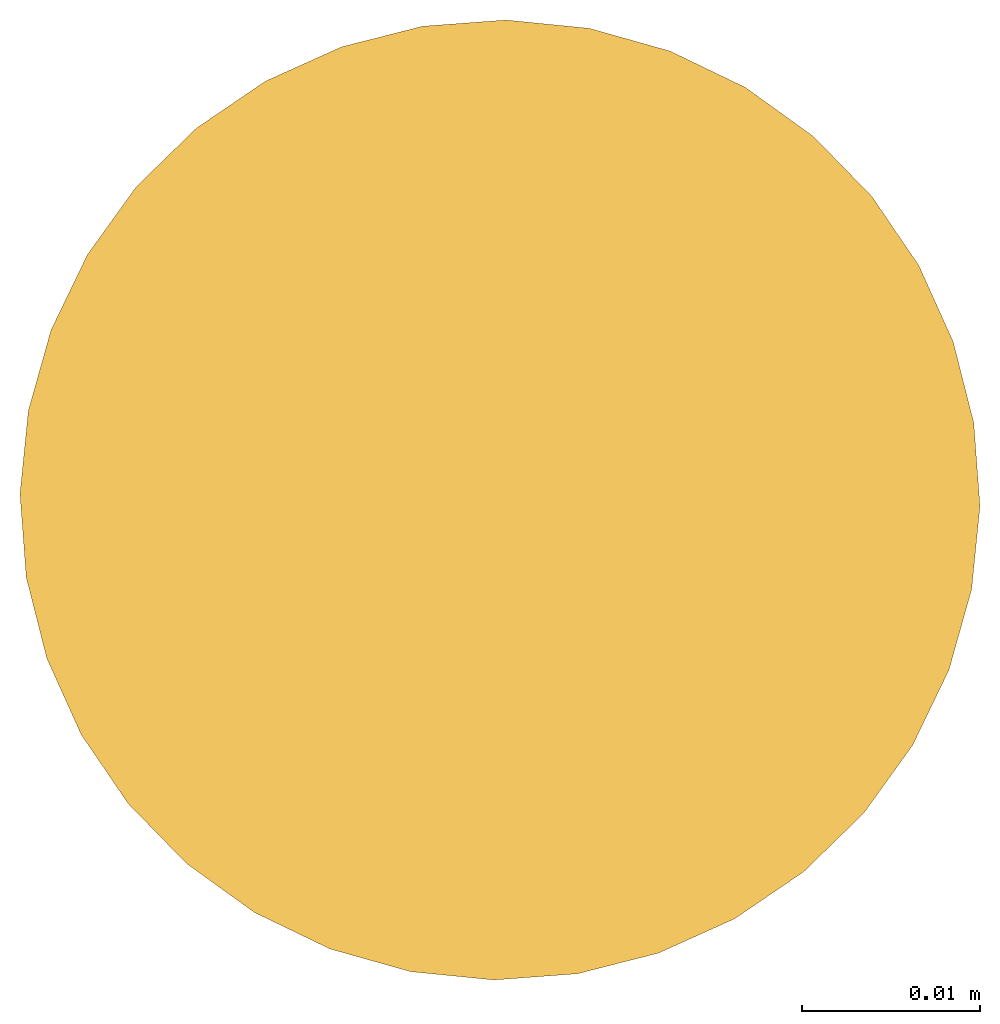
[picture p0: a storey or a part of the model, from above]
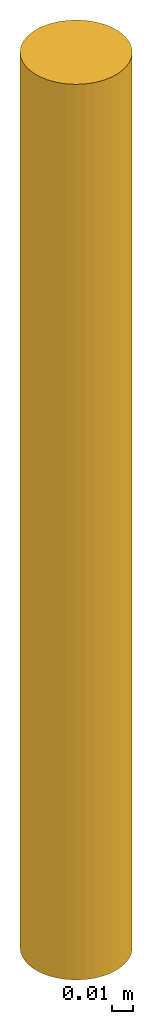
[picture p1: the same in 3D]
Properties of the parts of a building model (IFC2X3), part 1 of 3

# File
Description: ViewDefinition [CoordinationView_V2.0]
File name: BR001-350-202.1 (EDITED).ifc (Edited by Naviate Simple BIM 2022 version 6)
Time: 2026-03-27T10:06:01+01:00
Written by: ODA SDAI 24.12
Made in: Autodesk Revit 25.4.41.14 (ENU) - IFC 25.4.0.27

# IfcProject, 01. Avinor Drift
LongName: Terminal 2 . Satellitt; Phase: Som Bygget

# IfcSite (5)
RefElevation: 0 mm
Name | RefLatitude | RefLongitude
4 x Default | 60, 17, 20, 899658 | 5, 13, 37, 654037
Default | 42, 24, 53, 508911 | -71, -15, -29, -58837

# IfcBuilding (5)
Name | LongName
br001-a-200-1-0001 | br001-a-200-1-0001

3 x Bygning (endres i Project Information) | Bygning (endres i Project Information)

# IfcBuildingStorey: Level:Level - BR001_ARK (3)
In: br001-a-200-1-0001
Name | LongName | Elevation (mm)
H01-Nivå D+0,36 | H01-Nivå D+0,36 | 51360
H02-Nivå F-3,5 m | H02-Nivå F-3,5 m | 55500
H03-Nivå G-5m | H03-Nivå G-5m | 59000

# IfcBuildingStorey: Level:Level Elektro, H01-Nivå D+0,36
In: Bygning (endres i Project Information)
LongName: H01-Nivå D+0,36; Elevation: 51360 mm

# IfcBuildingStorey: Level:NO_Nivå_Meter-VVS (4)
In: Bygning (endres i Project Information)
Name | LongName | Elevation (mm)
2 x H01-Nivå D+0,36 | H01-Nivå D+0,36 | 51360
H02-Nivå F-3,5 m | H02-Nivå F-3,5 m | 55500
U01-Nivå B+3,1m | U01-Nivå B+3,1m | 47800

# IfcBuildingStorey: Level:NSW Kote - Triangel med navn og kote, Arial 2 mm KP (3)
Name | LongName | Elevation (mm)
U01-Nivå B+3,1m | U01-Nivå B+3,1m | 47800
H01-Nivå D+0,36 | H01-Nivå D+0,36 | 51360
H02-Nivå F-3,5 m | H02-Nivå F-3,5 m | 55500

# IfcBeam: 315*100, PLASSTØPTDEKKE
In: H01-Nivå D+0,36
Description: 315*100
ePset_Simplebim - Assembly Level: Leaf
ePset_LocationTool - Splitting: RESULT
ePset_SimplebimBasicQuantities - Weight, as steel (Simplebim): 629.389 kg; Volume, net (Simplebim): 0.0801769 m3; Area, sides, net (Simplebim): 2.20169 m2; Height (Simplebim): 315 mm; Width (Simplebim): 1800 mm; Length (Simplebim): 1941 mm
Pset_BeamCommon - Reference: 315*100

# IfcBeam: 500*250, PLASSTØPTBJELKE
In: H01-Nivå D+0,36
Description: 500*250
ePset_SimplebimBasicQuantities - Volume, net (Simplebim): 0.0735892 m3; Weight, as steel (Simplebim): 577.675 kg; Area, sides, net (Simplebim): 1.13307 m2; Width (Simplebim): 250 mm; Height (Simplebim): 500 mm; Length (Simplebim): 589 mm
Pset_BeamCommon - Reference: 500*250
ePset_Simplebim - Assembly Level: Leaf
ePset_LocationTool - Splitting: RESULT

# IfcBeam: 650*400 (13)
Description: 650*400
ePset_Simplebim - Assembly Level: Leaf
Pset_BeamCommon - Reference: 650*400
Name | In | Material | Width (Simplebim) (mm) | Volume, net (Simplebim) (m3) | Weight, as steel (Simplebim) (kg) | Area, sides, net (Simplebim) (m2) | Length (Simplebim) (mm) | Height (Simplebim) (mm) | Splitting
4 x PLASSTØPTBJELKE | H02-Nivå F-3,5 m | CONCRETE/C55/67 171016 | 400.026 | 1.56 | 12246 | 13.12 | 6000 | 650 | ORIGINAL
PLASSTØPTBJELKE | H01-Nivå D+0,36 | CONCRETE/C55/67 171016 | 400.024 | 1.456 | 11429.6 | 12.28 | 5600 | 650 | ORIGINAL
PLASSTØPTBJELKE | H02-Nivå F-3,5 m | CONCRETE/C55/67 171016 | 6282.82 | 2.20617 | 17318.5 | 18.3391 | 6282.87 | 650 | ORIGINAL
PLASSTØPTBJELKE | H01-Nivå D+0,36 | CONCRETE/C55/67 171016 | 400.024 | 1.4294 | 11220.8 | 12.139 | 5590 | 650 | ORIGINAL
PLASSTØPTBJELKE | H01-Nivå D+0,36 | CONCRETE/C55/67 171016 | 400.023 | 1.4034 | 11016.7 | 11.929 | 5490 | 650 | ORIGINAL
PLASSTØPTBJELKE | H01-Nivå D+0,36 | CONCRETE/C55/67 171016 | 400.025 | 1.508 | 11837.8 | 12.7 | 5800 | 650 | ORIGINAL
PLASSTØPTBJELKE | H02-Nivå F-3,5 m |  | 328 | 0.0854129 | 670.492 | 1.20987 | 400 | 650 | RESULT
PLASSTØPTBJELKE | H02-Nivå F-3,5 m |  | 340 | 0.0731105 | 573.917 | 1.2182 | 623 | 650 | RESULT
PLASSTØPTBJELKE | H02-Nivå F-3,5 m |  | 328 | 0.0854267 | 670.6 | 1.20999 | 400 | 650 | RESULT
PLASSTØPTBJELKE | H01-Nivå D+0,36 |  | 5922 | 1.24086 | 9740.74 | 12.8968 | 5922 | 390 | RESULT

# IfcBeam: DT450*2400-100-50-1200-0-200-0.3 (12)
In: H01-Nivå D+0,36
Description: DT450*2400-100-50-1200-0-200-0.3
ePset_Simplebim - Assembly Level: Leaf
ePset_SimplebimBasicQuantities - Height (Simplebim): 450 mm
Pset_BeamCommon - Reference: DT450*2400-100-50-1200-0-200-0.3
Name | Volume, net (Simplebim) (m3) | Weight, as steel (Simplebim) (kg) | Area, sides, net (Simplebim) (m2) | Length (Simplebim) (mm) | Width (Simplebim) (mm) | Splitting
2 x DT | 2.80784 | 22041.5 | 79.3586 | 12535 | 2400.06 | ORIGINAL | Material: CONCRETE/C45/55
DT | 2.52784 | 19843.5 | 71.5824 | 12485 | 2400.06 | ORIGINAL | Material: CONCRETE/C45/55
2 x DT | 2.79475 | 21938.8 | 78.8674 | 12535 | 2400.06 | ORIGINAL | Material: CONCRETE/C45/55
DT | 1.52352 | 11959.6 | 45.8835 | 11985 | 1529 | RESULT
DT | 2.6846 | 21074.1 | 75.8952 | 11984 | 2400 | RESULT
2 x DT | 2.67679 | 21012.8 | 75.5827 | 11985 | 2400 | RESULT
DT | 1.58364 | 12431.6 | 47.6803 | 12535 | 1529 | RESULT
DT | 1.12787 | 8853.78 | 33.2882 | 10085 | 1399 | RESULT
DT | 1.44633 | 11353.7 | 42.7471 | 11970 | 1399 | RESULT

# IfcBeam: HD265 (2)
In: H01-Nivå D+0,36
Description: HD265
ePset_Simplebim - Assembly Level: Leaf
Pset_BeamCommon - Reference: HD265
ePset_SimplebimBasicQuantities - Height (Simplebim): 265 mm
Name | Splitting | Volume, net (Simplebim) (m3) | Width (Simplebim) (mm) | Area, sides, net (Simplebim) (m2) | Length (Simplebim) (mm) | Weight, as steel (Simplebim) (kg)
HULLDEKKE | ORIGINAL | 0.302374 | 1196.01 | 10.5438 | 2346.58 | 2373.64 | Material: CONCRETE/C45/55 4257
HULLDEKKE | RESULT | 0.225103 | 598 | 7.971 | 2948 | 1767.06

# IfcBeam: IPE400 (2)
In: H01-Nivå D+0,36
Description: IPE400
ePset_Simplebim - Assembly Level: Leaf
ePset_LocationTool - Splitting: RESULT
Pset_BeamCommon - Reference: IPE400
Name | Volume, net (Simplebim) (m3) | Weight, as steel (Simplebim) (kg) | Area, sides, net (Simplebim) (m2) | Width (Simplebim) (mm) | Height (Simplebim) (mm) | Length (Simplebim) (mm)
STÅLBJELKE | 0.00207902 | 16.3203 | 0.425815 | 120 | 235 | 590
STÅLBJELKE | 0.0461678 | 362.417 | 8.64705 | 180 | 400 | 6173

# IfcBuildingElementProxy: LKR-600:LKR-160-600, LKR-600:LKR-160-600:5845895
In: H01-Nivå D+0,36
Type - Material: 3601.001 Avtrekk
ePset_SimplebimBasicQuantities - Area, largest surface, net (Simplebim): 0.126 m2; Length (Simplebim): 630 mm; Volume, net (Simplebim): 0.000116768 m3; Thickness (Simplebim): 200.2 mm; Height (Simplebim): 200.2 mm
ePset_Simplebim - Assembly Level: Leaf
ePset_LocationTool - Splitting: ORIGINAL
Pset_BuildingElementProxyCommon - Reference: LKR-600:LKR-160-600
Group: 36.02 Avtrekk 1.etg syd og vest: 5

# IfcBuildingElementProxy: LKR-600:LKR-160-600, LKR-600:LKR-160-600:5846157
In: H01-Nivå D+0,36
Type - Material: 3601.001 Tilluft
ePset_LocationTool - Splitting: ORIGINAL
ePset_SimplebimBasicQuantities - Area, largest surface, net (Simplebim): 0.126 m2; Length (Simplebim): 630 mm; Volume, net (Simplebim): 0.000116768 m3; Thickness (Simplebim): 200.2 mm; Height (Simplebim): 200.2 mm
ePset_Simplebim - Assembly Level: Leaf
Pset_BuildingElementProxyCommon - Reference: LKR-600:LKR-160-600
Group: 36.02 Tilluft 1.etg syd og vest: 9

# IfcBuildingElementProxy: RA4303 Dome Kamera SNC-RZ25P i tak:RA4303, RA4303 Dome Kamera SNC-RZ25P i tak:RA4303:2982597
In: H01-Nivå D+0,36
Type - Material: Plastic - White
Classification: RA001 (Uniformat)
ePset_LocationTool - Splitting: ORIGINAL
ePset_SimplebimBasicQuantities - Volume, net (Simplebim): 0.00247107 m3; Thickness (Simplebim): 140 mm; Length (Simplebim): 148 mm; Height (Simplebim): 206 mm; Area, largest surface, net (Simplebim): 0.0438648 m2
Pset_BuildingElementProxyCommon - Reference: RA4303 Dome Kamera SNC-RZ25P i tak:RA4303
ePset_Simplebim - Assembly Level: Leaf

# IfcBuildingElementProxy: REACT V-SR GMBa VAV:REACT V-SR GMBa-160 (2)
In: H01-Nivå D+0,36
Type - Material: MC_255_255_255_0_50, MC_0_0_0_0_50, MC_191_191_191_0_50
Pset_BuildingElementProxyCommon - Reference: REACT V-SR GMBa VAV:REACT V-SR GMBa-160
ePset_Simplebim - Assembly Level: Leaf
ePset_SimplebimBasicQuantities - Volume, net (Simplebim): 0.00126622 m3; Area, largest surface, net (Simplebim): 0.189784 m2
ePset_LocationTool - Splitting: ORIGINAL
Name (REACT V-SR GMBa VAV:REACT V-SR GMBa-160:...) | Height (Simplebim) (mm) | Length (Simplebim) (mm) | Thickness (Simplebim) (mm) | Group
5845898 | 290.687 | 398.724 | 197.261 | 36.02 Avtrekk 1.etg syd og vest: 5
5846158 | 253.772 | 396.977 | 247.819 | 36.02 Tilluft 1.etg syd og vest: 9

# IfcColumn: 120*190, STÅLSØYLE
In: H01-Nivå D+0,36
Description: 120*190
ePset_SimplebimBasicQuantities - Area, sides, net (Simplebim): 0.00992928 m2; Depth (Simplebim): 120.001 mm; Width (Simplebim): 16 mm; Volume, net (Simplebim): 0.0003648 m3; Weight, as steel (Simplebim): 2.86368 kg; Height (Simplebim): 190.001 mm
ePset_Simplebim - Assembly Level: Leaf
ePset_LocationTool - Splitting: ORIGINAL
Pset_ColumnCommon - Reference: 120*190

# IfcColumn: 185*300 (2)
In: H01-Nivå D+0,36
Description: 185*300
Pset_ColumnCommon - Reference: 185*300
ePset_Simplebim - Assembly Level: Leaf
ePset_SimplebimBasicQuantities - Weight, as steel (Simplebim): 4.35675 kg; Width (Simplebim): 10 mm; Height (Simplebim): 342.947 mm; Depth (Simplebim): 342.946 mm; Area, sides, net (Simplebim): 0.00971243 m2; Volume, net (Simplebim): 0.000555 m3
ePset_LocationTool - Splitting: ORIGINAL

# IfcColumn: 20*860, STÅLSØYLE
In: H01-Nivå D+0,36
Description: 20*860
ePset_SimplebimBasicQuantities - Area, sides, net (Simplebim): 0.527981 m2; Volume, net (Simplebim): 0.00516 m3; Weight, as steel (Simplebim): 40.506 kg; Depth (Simplebim): 300 mm; Width (Simplebim): 20.0038 mm; Height (Simplebim): 860 mm
ePset_Simplebim - Assembly Level: Leaf
Pset_ColumnCommon - Reference: 20*860
ePset_LocationTool - Splitting: ORIGINAL

# IfcColumn: 200*150, STÅLSØYLE
In: H02-Nivå F-3,5 m
Description: 200*150
ePset_SimplebimBasicQuantities - Height (Simplebim): 247.488 mm; Area, sides, net (Simplebim): 0.00701916 m2; Depth (Simplebim): 247.487 mm; Volume, net (Simplebim): 0.0003 m3; Width (Simplebim): 10 mm; Weight, as steel (Simplebim): 2.355 kg
ePset_Simplebim - Assembly Level: Leaf
Pset_ColumnCommon - Reference: 200*150
ePset_LocationTool - Splitting: ORIGINAL

# IfcColumn: 300*400 (2)
In: H02-Nivå F-3,5 m
Description: 300*400
ePset_LocationTool - Splitting: ORIGINAL
ePset_Simplebim - Assembly Level: Leaf
Pset_ColumnCommon - Reference: 300*400
ePset_SimplebimBasicQuantities - Volume, net (Simplebim): 0.036 m3; Weight, as steel (Simplebim): 282.6 kg; Height (Simplebim): 400.002 mm; Depth (Simplebim): 300.002 mm; Width (Simplebim): 300 mm
Name | Area, sides, net (Simplebim) (m2)
PLASSTØPTSØYLE | 0.419997
PLASSTØPTSØYLE | 0.419989

# IfcColumn: 400*400 (6)
Description: 400*400
ePset_LocationTool - Splitting: RESULT
ePset_Simplebim - Assembly Level: Leaf
ePset_SimplebimBasicQuantities - Depth (Simplebim): 400 mm; Width (Simplebim): 400 mm
Pset_ColumnCommon - Reference: 400*400
Name | In | Volume, net (Simplebim) (m3) | Weight, as steel (Simplebim) (kg) | Area, sides, net (Simplebim) (m2) | Height (Simplebim) (mm)
2 x PLASSTØPTSØYLE | H02-Nivå F-3,5 m | 0.6192 | 4860.72 | 6.19199 | 3870
PLASSTØPTSØYLE | H02-Nivå F-3,5 m | 0.6192 | 4860.72 | 6.19198 | 3870
2 x PLASSTØPTSØYLE | U01-Nivå B+3,1m | 0.1488 | 1168.08 | 1.48799 | 930
PLASSTØPTSØYLE | U01-Nivå B+3,1m | 0.1488 | 1168.08 | 1.48798 | 930

# IfcColumn: Columns T10:Columns T2, Columns T10:Columns T2:11666152
In: H02-Nivå F-3,5 m
Type - PredefinedType: COLUMN; Material: <Unnamed>
ePset_Simplebim - Assembly Level: Leaf
ePset_SimplebimBasicQuantities - Area, sides, net (Simplebim): 8.43072 m2; Width (Simplebim): 400 mm; Weight, as steel (Simplebim): 1413 kg; Height (Simplebim): 3000 mm; Depth (Simplebim): 949.317 mm; Volume, net (Simplebim): 0.18 m3
ePset_LocationTool - Splitting: ORIGINAL
Pset_ColumnCommon - Reference: Columns T10:Columns T2

# IfcColumn: Columns T11:Columns T2, Columns T11:Columns T2:11666168
In: H02-Nivå F-3,5 m
Type - PredefinedType: COLUMN; Material: <Unnamed>
Pset_ColumnCommon - Reference: Columns T11:Columns T2
ePset_Simplebim - Assembly Level: Leaf
ePset_SimplebimBasicQuantities - Area, sides, net (Simplebim): 8.43072 m2; Width (Simplebim): 400 mm; Weight, as steel (Simplebim): 1413 kg; Height (Simplebim): 3000 mm; Depth (Simplebim): 949.317 mm; Volume, net (Simplebim): 0.18 m3
ePset_LocationTool - Splitting: ORIGINAL

# IfcColumn: D500 (4)
In: H02-Nivå F-3,5 m
Description: D500
ePset_LocationTool - Splitting: ORIGINAL
ePset_Simplebim - Assembly Level: Leaf
ePset_SimplebimBasicQuantities - Weight, as steel (Simplebim): 4620.39 kg; Volume, net (Simplebim): 0.588585 m3; Height (Simplebim): 3010 mm; Width (Simplebim): 500 mm; Depth (Simplebim): 500 mm
Pset_ColumnCommon - Reference: D500
Name | Area, sides, net (Simplebim) (m2)
2 x PLASSTØPTSØYLE | 4.72324
PLASSTØPTSØYLE | 4.72326
PLASSTØPTSØYLE | 4.72323

# IfcColumn: D600 (8)
Description: D600
ePset_SimplebimBasicQuantities - Width (Simplebim): 600 mm; Depth (Simplebim): 600 mm
ePset_Simplebim - Assembly Level: Leaf
Pset_ColumnCommon - Reference: D600
Name | In | Area, sides, net (Simplebim) (m2) | Height (Simplebim) (mm) | Weight, as steel (Simplebim) (kg) | Volume, net (Simplebim) (m3) | Splitting
3 x PLASSTØPTSØYLE | H01-Nivå D+0,36 | 2.24079 | 1190 | 2630.4 | 0.335083 | ORIGINAL
PLASSTØPTSØYLE | H01-Nivå D+0,36 | 2.24078 | 1190 | 2630.4 | 0.335083 | ORIGINAL
2 x PLASSTØPTSØYLE | H02-Nivå F-3,5 m | 1.61939 | 860 | 1900.96 | 0.242161 | RESULT
2 x PLASSTØPTSØYLE | H02-Nivå F-3,5 m | 1.6194 | 860 | 1900.96 | 0.242161 | RESULT

# IfcColumn: NSW Søyle - Betong rektangulær:300 x 300 mm, NSW Søyle - Betong rektangulær:300 x 300 mm:1708831
In: H01-Nivå D+0,36
Type - PredefinedType: COLUMN; Material: _NSW Betong
ePset_SimplebimBasicQuantities - Volume, net (Simplebim): 0.08082 m3; Weight, as steel (Simplebim): 634.437 kg; Depth (Simplebim): 300 mm; Width (Simplebim): 300 mm; Height (Simplebim): 900 mm; Area, sides, net (Simplebim): 1.05891 m2
ePset_LocationTool - Splitting: RESULT
ePset_Simplebim - Assembly Level: Leaf
Pset_ColumnCommon - Reference: NSW Søyle - Betong rektangulær:300 x 300 mm

# IfcColumn: NSW Søyle - Betong rektangulær:400 x 400 mm (6)
Type - PredefinedType: COLUMN; Material: _NSW Betong
ePset_Simplebim - Assembly Level: Leaf
ePset_SimplebimBasicQuantities - Depth (Simplebim): 400 mm
Pset_ColumnCommon - Reference: NSW Søyle - Betong rektangulær:400 x 400 mm
Name (NSW Søyle - Betong rektangulær:400 x 400 mm:...) | In | Splitting | Volume, net (Simplebim) (m3) | Area, sides, net (Simplebim) (m2) | Width (Simplebim) (mm) | Height (Simplebim) (mm) | Weight, as steel (Simplebim) (kg)
865032 | H02-Nivå F-3,5 m | ORIGINAL | 0.01598 | 0.157657 | 100 | 400 | 125.443
865033 | H02-Nivå F-3,5 m | ORIGINAL | 0.01598 | 0.157657 | 100 | 400 | 125.443
865034 | H02-Nivå F-3,5 m | ORIGINAL | 0.01598 | 0.157657 | 100 | 400 | 125.443
263693 | H01-Nivå D+0,36 | RESULT | 0.1598 | 1.57657 | 400 | 1000 | 1254.43
263692 | H01-Nivå D+0,36 | RESULT | 0.1598 | 1.57657 | 400 | 1000 | 1254.43
263691 | H01-Nivå D+0,36 | RESULT | 0.1598 | 1.57657 | 400 | 1000 | 1254.43

# IfcColumn: NSW Søyle - Betong rund:ø500 mm (10)
Type - PredefinedType: COLUMN; Material: _NSW Betong
ePset_Simplebim - Assembly Level: Leaf
Pset_ColumnCommon - Reference: NSW Søyle - Betong rund:ø500 mm
ePset_SimplebimBasicQuantities - Depth (Simplebim): 500 mm
Name (NSW Søyle - Betong rund:ø500 mm:...) | In | Splitting | Area, sides, net (Simplebim) (m2) | Height (Simplebim) (mm) | Volume, net (Simplebim) (m3) | Width (Simplebim) (mm) | Weight, as steel (Simplebim) (kg)
865003 | H02-Nivå F-3,5 m | ORIGINAL | 0.15688 | 500 | 0.0195354 | 100 | 153.353
865016 | H02-Nivå F-3,5 m | ORIGINAL | 0.15688 | 500 | 0.0195354 | 100 | 153.353
865017 | H02-Nivå F-3,5 m | ORIGINAL | 0.15688 | 500 | 0.0195354 | 100 | 153.353
2017729 | H02-Nivå F-3,5 m | ORIGINAL | 5.56925 | 3550 | 0.693507 | 500 | 5444.03
263734 | H01-Nivå D+0,36 | RESULT | 1.5688 | 1000 | 0.195354 | 500 | 1533.53
263733 | H01-Nivå D+0,36 | RESULT | 1.5688 | 1000 | 0.195354 | 500 | 1533.53
263735 | H01-Nivå D+0,36 | RESULT | 1.5688 | 1000 | 0.195354 | 500 | 1533.53
263675 | H01-Nivå D+0,36 | RESULT | 1.5688 | 1000 | 0.195354 | 500 | 1533.53
263676 | H01-Nivå D+0,36 | RESULT | 1.5688 | 1000 | 0.195354 | 500 | 1533.53
263662 | H01-Nivå D+0,36 | RESULT | 1.5688 | 1000 | 0.195354 | 500 | 1533.53

# IfcColumn: RHS100*60*5, STÅLSØYLE
In: H01-Nivå D+0,36
Description: RHS100*60*5
ePset_LocationTool - Splitting: ORIGINAL
ePset_Simplebim - Assembly Level: Leaf
ePset_SimplebimBasicQuantities - Volume, net (Simplebim): 0.000882 m3; Depth (Simplebim): 100 mm; Weight, as steel (Simplebim): 6.9237 kg; Area, sides, net (Simplebim): 0.352791 m2; Width (Simplebim): 60.0004 mm; Height (Simplebim): 588 mm
Pset_ColumnCommon - Reference: RHS100*60*5

# IfcColumn: RHS150*100*6.3 (3)
Description: RHS150*100*6.3
ePset_Simplebim - Assembly Level: Leaf
Pset_ColumnCommon - Reference: RHS150*100*6.3
Name | In | Depth (Simplebim) (mm) | Area, sides, net (Simplebim) (m2) | Weight, as steel (Simplebim) (kg) | Volume, net (Simplebim) (m3) | Width (Simplebim) (mm) | Height (Simplebim) (mm) | Splitting
STÅLSØYLE | H02-Nivå F-3,5 m | 176.777 | 3.78417 | 93.5727 | 0.0119201 | 176.777 | 3985 | ORIGINAL
STÅLSØYLE | H01-Nivå D+0,36 | 177 | 0.612506 | 15.1454 | 0.00192935 | 177 | 645 | RESULT
STÅLSØYLE | H01-Nivå D+0,36 | 177 | 0.612506 | 15.1454 | 0.00192935 | 176 | 645 | RESULT

# IfcCovering: Pipe Insulation:GLAVA Rørskål ClimPipe Alu2, isol.kl.4, 45°C (12)
In: H01-Nivå D+0,36
Type - PredefinedType: INSULATION
ePset_Simplebim - Assembly Level: Leaf
Pset_CoveringCommon - Reference: Pipe Insulation:GLAVA Rørskål ClimPipe Alu2, isol.kl.4, 45°C
Name (Pipe Insulation:GLAVA Rørskål ClimPipe Alu2, isol.kl.4, 45°C:...) | Material | Splitting | Length (Simplebim) (mm) | Volume, net (Simplebim) (m3) | Area, largest surface, net (Simplebim) (m2) | Width (Simplebim) (mm) = Height (Simplebim) (mm)
5647646 | 3200.002 Retur | ORIGINAL | 381.468 | 0.00532851 | 0.160131 | 134
5647676 | 3200.003 Tur | ORIGINAL | 380 | 0.005308 | 0.159514 | 134
5647769 | 3200.003 Tur | ORIGINAL | 1563.5 | 0.0218573 | 0.656431 | 134
5647965 | 3200.003 Tur | ORIGINAL | 137 | 0.00398234 | 0.0545841 | 133.5
5647966 |  | ORIGINAL | 170 | 0.00237909 | 0.0713168 | 134
5647971 | 3200.003 Tur | ORIGINAL | 137 | 0.00398234 | 0.0545841 | 133.5
5648007 | 3200.002 Retur | ORIGINAL | 137 | 0.00398234 | 0.0545841 | 133.5
5648008 |  | ORIGINAL | 170 | 0.00237909 | 0.0713168 | 134
5648013 | 3200.002 Retur | ORIGINAL | 137 | 0.00398234 | 0.0545841 | 133.5
5648832 |  | RESULT | 10492 | 0.146559 | 0.0139787 | 134
5648856 |  | RESULT | 10502 | 0.146736 | 0.0139844 | 134
5647727 |  | RESULT | 1321 | 0.0184776 | 0.0139749 | 134

# IfcCovering: Pipe Insulation:GLAVA avløpsisol. slange økende 19mm (15,5-25,0) (18)
In: H01-Nivå D+0,36
Type - PredefinedType: INSULATION
ePset_Simplebim - Assembly Level: Leaf
Pset_CoveringCommon - Reference: Pipe Insulation:GLAVA avløpsisol. slange økende 19mm (15,5-25,0)
Name (Pipe Insulation:GLAVA avløpsisol. slange økende 19mm (15,5-25,0):...) | Material | Splitting | Length (Simplebim) (mm) | Area, largest surface, net (Simplebim) (m2) | Volume, net (Simplebim) (m3) | Height (Simplebim) (mm) | Width (Simplebim) (mm)
5597703 | 3700.001 Retur | ORIGINAL | 657.357 | 0.247394 | 0.0073879 | 120.1 | 120.1
5598242 | 3700.001 Retur | ORIGINAL | 186.738 | 0.0542593 | 0.00162291 | 186.738 | 120.1
5598259 | 3700.001 Retur | ORIGINAL | 131.604 | 0.0293422 | 0.000870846 | 120.1 | 112.698
5598268 | 3700.001 Retur | ORIGINAL | 131.604 | 0.0293422 | 0.000870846 | 120.1 | 112.698
5598296 | 3700.001 Retur | ORIGINAL | 156.55 | 0.057121 | 0.00169602 | 156.55 | 120.1
5598297 | 3700.001 Retur | ORIGINAL | 120.1 | 0.0403207 | 0.00120602 | 107.001 | 120.1
5598306 | 3700.001 Retur | ORIGINAL | 156.55 | 0.057121 | 0.00169602 | 156.55 | 120.1
5598397 | 3700.001 Tur | ORIGINAL | 630.858 | 0.237421 | 0.00709001 | 120.1 | 120.1
5598681 | 3700.001 Tur | ORIGINAL | 120.1 | 0.0542593 | 0.00162291 | 186.738 | 186.738
5598707 | 3700.001 Tur | ORIGINAL | 131.604 | 0.0293422 | 0.000870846 | 120.1 | 112.698
5598803 | 3700.001 Tur | ORIGINAL | 120.1 | 0.0403207 | 0.00120602 | 107.001 | 120.1
5598821 | 3700.001 Tur | ORIGINAL | 131.604 | 0.0293422 | 0.000870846 | 120.1 | 112.698
5598830 | 3700.001 Tur | ORIGINAL | 156.55 | 0.057121 | 0.00169602 | 156.55 | 120.1
5598928 | 3700.001 Tur | ORIGINAL | 156.55 | 0.057121 | 0.00169602 | 156.55 | 120.1
5598130 |  | RESULT | 10623 | 0.0112268 | 0.119131 | 120 | 120
5598526 |  | RESULT | 10608 | 0.0112312 | 0.119026 | 120 | 120
5595826 |  | RESULT | 812 | 0.0112529 | 0.00912295 | 120 | 120
5596265 |  | RESULT | 853 | 0.0112316 | 0.00958401 | 120 | 120

# IfcCovering: Pipe Insulation:GLAVA kondensisol. slange økende 13mm (11,0-16,0) (5)
Type - PredefinedType: INSULATION
Pset_CoveringCommon - Reference: Pipe Insulation:GLAVA kondensisol. slange økende 13mm (11,0-16,0)
ePset_Simplebim - Assembly Level: Leaf
Name (Pipe Insulation:GLAVA kondensisol. slange økende 13mm (11,0-16,0):...) | In | Material | Splitting | Area, largest surface, net (Simplebim) (m2) | Volume, net (Simplebim) (m3) | Width (Simplebim) (mm) | Height (Simplebim) (mm) | Length (Simplebim) (mm)
5642019 | H01-Nivå D+0,36 | 3103.001 KV | ORIGINAL | 1.91816 | 0.0257409 | 54 | 54 | 11332
5642043 | H01-Nivå D+0,36 | 3103.001 KV | ORIGINAL | 0.00920124 | 0.00014901 | 57 | 62.5 | 62.5
5642102 | H01-Nivå D+0,36 | 3103.001 KV | ORIGINAL | 0.00920124 | 0.00014901 | 57 | 62.5 | 62.5
5642042 | U01-Nivå B+3,1m |  | RESULT | 0.00249899 | 0.00119855 | 54 | 54 | 526
5642101 | H01-Nivå D+0,36 |  | RESULT | 0.00249899 | 0.00119855 | 54 | 54 | 526

# IfcCurtainWall: Curtain Wall:A243 Innvendig glassvegg, Curtain Wall:A243 Innvendig glassvegg:12073057
In: H02-Nivå F-3,5 m
ePset_SimplebimBasicQuantities - Width: 136 mm; Height: 3200 mm; Length: 11270 mm; Volume, net (Simplebim): 1.0263 m3
ePset_Simplebim - Assembly Level: Topmost
Pset_CurtainWallCommon - Reference: Curtain Wall:A243 Innvendig glassvegg

# IfcCurtainWall: Curtain Wall:Flesland int curt wall (2)
In: H02-Nivå F-3,5 m
Pset_CurtainWallCommon - Reference: Curtain Wall:Flesland int curt wall
ePset_Simplebim - Assembly Level: Topmost
ePset_SimplebimBasicQuantities - Width: 125 mm; Height: 10690 mm
Name (Curtain Wall:Flesland int curt wall:...) | Length (mm) | Volume, net (Simplebim) (m3)
867524 | 34825 | 20.2489
2090176 | 23124.5 | 12.09

# IfcDistributionPort (732)
Description: Flow
ePset_Simplebim - Assembly Level: Leaf
Name | FlowDirection | Group
Port_2982597_1 | SOURCEANDSINK
Port_2982597_2 | SOURCEANDSINK
Port_2982597_3 | SOURCEANDSINK
Port_2982597_4 | SOURCEANDSINK
Port_3027100_1 | SOURCEANDSINK
Port_5596789_1 | SOURCEANDSINK | 36.03 Tilluft 1.etg nord og øst + nordfløy: 1
Port_5560016_1 | SOURCEANDSINK | 36.03 Tilluft 1.etg nord og øst + nordfløy: 1
Port_5476159_0 | SOURCEANDSINK | 36.03 Tilluft 1.etg nord og øst + nordfløy: 1
Port_5559984_1 | SOURCEANDSINK | 36.03 Tilluft 1.etg nord og øst + nordfløy: 1
Port_5476159_1 | SOURCEANDSINK | 36.03 Tilluft 1.etg nord og øst + nordfløy: 1
Port_5480154_0 | SOURCEANDSINK | 36.01 Tilluft Passasjerhall og kjeller: 2
Port_5553866_1 | SOURCEANDSINK | 36.01 Tilluft Passasjerhall og kjeller: 2
Port_5480154_1 | SOURCEANDSINK | 36.01 Tilluft Passasjerhall og kjeller: 2
Port_5480172_0 | SOURCEANDSINK | 36.01 Tilluft Passasjerhall og kjeller: 2
Port_5553873_1 | SOURCEANDSINK | 36.01 Tilluft Passasjerhall og kjeller: 2
Port_5480172_1 | SOURCEANDSINK | 36.01 Tilluft Passasjerhall og kjeller: 2
Port_5480190_0 | SOURCEANDSINK | 36.01 Tilluft Passasjerhall og kjeller: 2
Port_5553880_1 | SOURCEANDSINK | 36.01 Tilluft Passasjerhall og kjeller: 2
Port_5480190_1 | SOURCEANDSINK | 36.01 Tilluft Passasjerhall og kjeller: 2
Port_5480208_0 | SOURCEANDSINK | 36.01 Tilluft Passasjerhall og kjeller: 2
Port_5553887_1 | SOURCEANDSINK | 36.01 Tilluft Passasjerhall og kjeller: 2
Port_5480208_1 | SOURCEANDSINK | 36.01 Tilluft Passasjerhall og kjeller: 2
Port_5480226_0 | SOURCEANDSINK | 36.01 Tilluft Passasjerhall og kjeller: 2
Port_5553894_1 | SOURCEANDSINK | 36.01 Tilluft Passasjerhall og kjeller: 2
Port_5480226_1 | SOURCEANDSINK | 36.01 Tilluft Passasjerhall og kjeller: 2
Port_5480244_0 | SOURCEANDSINK | 36.01 Tilluft Passasjerhall og kjeller: 2
Port_5553901_1 | SOURCEANDSINK | 36.01 Tilluft Passasjerhall og kjeller: 2
Port_5480244_1 | SOURCEANDSINK | 36.01 Tilluft Passasjerhall og kjeller: 2
Port_5480262_0 | SOURCEANDSINK | 36.01 Tilluft Passasjerhall og kjeller: 2
Port_5553908_1 | SOURCEANDSINK | 36.01 Tilluft Passasjerhall og kjeller: 2
Port_5480262_1 | SOURCEANDSINK | 36.01 Tilluft Passasjerhall og kjeller: 2
Port_5480280_0 | SOURCEANDSINK | 36.01 Tilluft Passasjerhall og kjeller: 2
Port_5553915_1 | SOURCEANDSINK | 36.01 Tilluft Passasjerhall og kjeller: 2
Port_5480280_1 | SOURCEANDSINK | 36.01 Tilluft Passasjerhall og kjeller: 2
Port_5553958_1 | SOURCEANDSINK | 36.01 Tilluft Passasjerhall og kjeller: 2
Port_5553961_1 | SOURCEANDSINK | 36.01 Tilluft Passasjerhall og kjeller: 2
Port_5553964_1 | SOURCEANDSINK | 36.01 Tilluft Passasjerhall og kjeller: 2
Port_5553967_1 | SOURCEANDSINK | 36.01 Tilluft Passasjerhall og kjeller: 2
Port_5553970_1 | SOURCEANDSINK | 36.01 Tilluft Passasjerhall og kjeller: 2
Port_5553973_1 | SOURCEANDSINK | 36.01 Tilluft Passasjerhall og kjeller: 2
Port_5553976_1 | SOURCEANDSINK | 36.01 Tilluft Passasjerhall og kjeller: 2
Port_5553979_1 | SOURCEANDSINK | 36.01 Tilluft Passasjerhall og kjeller: 2
Port_5490934_0 | SOURCEANDSINK | 36.03 Avtrekk 1.etg nord og øst + nordfløy: 1
Port_5553194_1 | SOURCEANDSINK | 36.03 Avtrekk 1.etg nord og øst + nordfløy: 1
Port_5490934_1 | SOURCEANDSINK | 36.03 Avtrekk 1.etg nord og øst + nordfløy: 1
Port_5490944_2 | SOURCEANDSINK | 36.03 Avtrekk 1.etg nord og øst + nordfløy: 1
Port_5490944_3 | SOURCEANDSINK | 36.03 Avtrekk 1.etg nord og øst + nordfløy: 1
Port_5490944_1 | SOURCEANDSINK | 36.03 Avtrekk 1.etg nord og øst + nordfløy: 1
Port_5490950_1 | SOURCEANDSINK | 36.03 Avtrekk 1.etg nord og øst + nordfløy: 1
Port_5490948_3 | SOURCEANDSINK | 36.03 Avtrekk 1.etg nord og øst + nordfløy: 1
InPort_5490948_1 | SINK | 36.03 Avtrekk 1.etg nord og øst + nordfløy: 1
OutPort_5490952_0 | SOURCE | 36.03 Avtrekk 1.etg nord og øst + nordfløy: 1
Port_5490948_2 | SOURCEANDSINK | 36.03 Avtrekk 1.etg nord og øst + nordfløy: 1
Port_5490950_0 | SOURCEANDSINK | 36.03 Avtrekk 1.etg nord og øst + nordfløy: 1
InPort_5490952_1 | SINK | 36.03 Avtrekk 1.etg nord og øst + nordfløy: 1
OutPort_5490954_1 | SOURCE | 36.03 Avtrekk 1.etg nord og øst + nordfløy: 1
Port_5490967_0 | SOURCEANDSINK | 36.03 Avtrekk 1.etg nord og øst + nordfløy: 1
Port_5553133_1 | SOURCEANDSINK | 36.03 Avtrekk 1.etg nord og øst + nordfløy: 1
Port_5490967_1 | SOURCEANDSINK | 36.03 Avtrekk 1.etg nord og øst + nordfløy: 1
Port_5490977_2 | SOURCEANDSINK | 36.03 Avtrekk 1.etg nord og øst + nordfløy: 1
Port_5490977_3 | SOURCEANDSINK | 36.03 Avtrekk 1.etg nord og øst + nordfløy: 1
Port_5490977_1 | SOURCEANDSINK | 36.03 Avtrekk 1.etg nord og øst + nordfløy: 1
Port_5490983_1 | SOURCEANDSINK | 36.03 Avtrekk 1.etg nord og øst + nordfløy: 1
Port_5490981_3 | SOURCEANDSINK | 36.03 Avtrekk 1.etg nord og øst + nordfløy: 1
InPort_5490981_1 | SINK | 36.03 Avtrekk 1.etg nord og øst + nordfløy: 1
OutPort_5490985_0 | SOURCE | 36.03 Avtrekk 1.etg nord og øst + nordfløy: 1
Port_5490981_2 | SOURCEANDSINK | 36.03 Avtrekk 1.etg nord og øst + nordfløy: 1
Port_5490983_0 | SOURCEANDSINK | 36.03 Avtrekk 1.etg nord og øst + nordfløy: 1
InPort_5490985_1 | SINK | 36.03 Avtrekk 1.etg nord og øst + nordfløy: 1
OutPort_5490987_1 | SOURCE | 36.03 Avtrekk 1.etg nord og øst + nordfløy: 1
Port_5596818_1 | SOURCEANDSINK | 36.03 Avtrekk 1.etg nord og øst + nordfløy: 1
Port_5510923_1 | SOURCEANDSINK | 36.26 Tilluft Bagasjehall 1.etg: 1
Port_5510921_0 | SOURCEANDSINK | 36.26 Tilluft Bagasjehall 1.etg: 1
Port_5510923_3 | SOURCEANDSINK | 36.26 Tilluft Bagasjehall 1.etg: 1
Port_5510921_1 | SOURCEANDSINK | 36.26 Tilluft Bagasjehall 1.etg: 1
Port_5510927_1 | SOURCEANDSINK | 36.26 Tilluft Bagasjehall 1.etg: 1
Port_5510923_2 | SOURCEANDSINK | 36.26 Tilluft Bagasjehall 1.etg: 1
Port_5510929_0 | SOURCEANDSINK | 36.26 Tilluft Bagasjehall 1.etg: 1
Port_5510925_0 | SOURCEANDSINK | 36.26 Tilluft Bagasjehall 1.etg: 1
Port_5510927_2 | SOURCEANDSINK | 36.26 Tilluft Bagasjehall 1.etg: 1
Port_5510925_1 | SOURCEANDSINK | 36.26 Tilluft Bagasjehall 1.etg: 1
Port_5510929_1 | SOURCEANDSINK | 36.26 Tilluft Bagasjehall 1.etg: 1
Port_5510931_1 | SOURCEANDSINK | 36.26 Tilluft Bagasjehall 1.etg: 1
Port_5510931_2 | SOURCEANDSINK | 36.26 Tilluft Bagasjehall 1.etg: 1
Port_5510933_0 | SOURCEANDSINK | 36.26 Tilluft Bagasjehall 1.etg: 1
Port_5510933_1 | SOURCEANDSINK | 36.26 Tilluft Bagasjehall 1.etg: 1
Port_5510937_1 | SOURCEANDSINK | 36.26 Tilluft Bagasjehall 1.etg: 1
Port_5510935_0 | SOURCEANDSINK | 36.26 Tilluft Bagasjehall 1.etg: 1
Port_5510937_2 | SOURCEANDSINK | 36.26 Tilluft Bagasjehall 1.etg: 1
Port_5510935_1 | SOURCEANDSINK | 36.26 Tilluft Bagasjehall 1.etg: 1
Port_5510941_1 | SOURCEANDSINK | 36.26 Tilluft Bagasjehall 1.etg: 1
Port_5510939_0 | SOURCEANDSINK | 36.26 Tilluft Bagasjehall 1.etg: 1
Port_5510941_2 | SOURCEANDSINK | 36.26 Tilluft Bagasjehall 1.etg: 1
Port_5510939_1 | SOURCEANDSINK | 36.26 Tilluft Bagasjehall 1.etg: 1
Port_5510945_1 | SOURCEANDSINK | 36.26 Tilluft Bagasjehall 1.etg: 1
Port_5510943_0 | SOURCEANDSINK | 36.26 Tilluft Bagasjehall 1.etg: 1
Port_5510945_2 | SOURCEANDSINK | 36.26 Tilluft Bagasjehall 1.etg: 1
Port_5510943_1 | SOURCEANDSINK | 36.26 Tilluft Bagasjehall 1.etg: 1
Port_5512122_1 | SOURCEANDSINK | 36.26 Tilluft Bagasjehall 1.etg: 1
Port_5511035_0 | SOURCEANDSINK | 36.26 Tilluft Bagasjehall 1.etg: 1
Port_5512118_1 | SOURCEANDSINK | 36.26 Tilluft Bagasjehall 1.etg: 1
Port_5511035_1 | SOURCEANDSINK | 36.26 Tilluft Bagasjehall 1.etg: 1
Port_5511043_1 | SOURCEANDSINK | 36.26 Tilluft Bagasjehall 1.etg: 1
Port_5511041_0 | SOURCEANDSINK | 36.26 Tilluft Bagasjehall 1.etg: 1
Port_5511043_2 | SOURCEANDSINK | 36.26 Tilluft Bagasjehall 1.etg: 1
Port_5511041_1 | SOURCEANDSINK | 36.26 Tilluft Bagasjehall 1.etg: 1
Port_5511047_1 | SOURCEANDSINK | 36.26 Tilluft Bagasjehall 1.etg: 1
Port_5511045_0 | SOURCEANDSINK | 36.26 Tilluft Bagasjehall 1.etg: 1
Port_5511047_2 | SOURCEANDSINK | 36.26 Tilluft Bagasjehall 1.etg: 1
Port_5511045_1 | SOURCEANDSINK | 36.26 Tilluft Bagasjehall 1.etg: 1
Port_5511051_1 | SOURCEANDSINK | 36.26 Tilluft Bagasjehall 1.etg: 1
Port_5511049_0 | SOURCEANDSINK | 36.26 Tilluft Bagasjehall 1.etg: 1
Port_5511051_2 | SOURCEANDSINK | 36.26 Tilluft Bagasjehall 1.etg: 1
Port_5511049_1 | SOURCEANDSINK | 36.26 Tilluft Bagasjehall 1.etg: 1
Port_5512103_0 | SOURCEANDSINK | 36.26 Tilluft Bagasjehall 1.etg: 1
Port_5512118_2 | SOURCEANDSINK | 36.26 Tilluft Bagasjehall 1.etg: 1
Port_5512103_1 | SOURCEANDSINK | 36.26 Tilluft Bagasjehall 1.etg: 1
Port_5512122_2 | SOURCEANDSINK | 36.26 Tilluft Bagasjehall 1.etg: 1
Port_5513688_1 | SOURCEANDSINK | 36.26 Tilluft Bagasjehall 1.etg: 1
Port_5513688_3 | SOURCEANDSINK | 36.26 Tilluft Bagasjehall 1.etg: 1
Port_5513688_2 | SOURCEANDSINK | 36.26 Tilluft Bagasjehall 1.etg: 1
Port_5513786_0 | SOURCEANDSINK | 36.26 Tilluft Bagasjehall 1.etg: 1
Port_5513786_1 | SOURCEANDSINK | 36.26 Tilluft Bagasjehall 1.etg: 1
Port_5513817_1 | SOURCEANDSINK | 36.26 Tilluft Bagasjehall 1.etg: 1
Port_5513796_0 | SOURCEANDSINK | 36.26 Tilluft Bagasjehall 1.etg: 1
Port_5513817_2 | SOURCEANDSINK | 36.26 Tilluft Bagasjehall 1.etg: 1
Port_5513796_1 | SOURCEANDSINK | 36.26 Tilluft Bagasjehall 1.etg: 1
Port_5513827_1 | SOURCEANDSINK | 36.26 Tilluft Bagasjehall 1.etg: 1
Port_5513827_2 | SOURCEANDSINK | 36.26 Tilluft Bagasjehall 1.etg: 1
Port_5553130_0 | SOURCEANDSINK | 36.03 Avtrekk 1.etg nord og øst + nordfløy: 1
Port_5596836_2 | SOURCEANDSINK | 36.03 Avtrekk 1.etg nord og øst + nordfløy: 1
Port_5553130_1 | SOURCEANDSINK | 36.03 Avtrekk 1.etg nord og øst + nordfløy: 1
Port_5553133_2 | SOURCEANDSINK | 36.03 Avtrekk 1.etg nord og øst + nordfløy: 1
Port_5553191_0 | SOURCEANDSINK | 36.03 Avtrekk 1.etg nord og øst + nordfløy: 1
Port_5596834_2 | SOURCEANDSINK | 36.03 Avtrekk 1.etg nord og øst + nordfløy: 1
Port_5553191_1 | SOURCEANDSINK | 36.03 Avtrekk 1.etg nord og øst + nordfløy: 1
Port_5553194_2 | SOURCEANDSINK | 36.03 Avtrekk 1.etg nord og øst + nordfløy: 1
Port_5553863_0 | SOURCEANDSINK | 36.01 Tilluft Passasjerhall og kjeller: 2
Port_5553958_2 | SOURCEANDSINK | 36.01 Tilluft Passasjerhall og kjeller: 2
Port_5553863_1 | SOURCEANDSINK | 36.01 Tilluft Passasjerhall og kjeller: 2
Port_5553866_2 | SOURCEANDSINK | 36.01 Tilluft Passasjerhall og kjeller: 2
Port_5553870_0 | SOURCEANDSINK | 36.01 Tilluft Passasjerhall og kjeller: 2
Port_5553961_2 | SOURCEANDSINK | 36.01 Tilluft Passasjerhall og kjeller: 2
Port_5553870_1 | SOURCEANDSINK | 36.01 Tilluft Passasjerhall og kjeller: 2
Port_5553873_2 | SOURCEANDSINK | 36.01 Tilluft Passasjerhall og kjeller: 2
Port_5553877_0 | SOURCEANDSINK | 36.01 Tilluft Passasjerhall og kjeller: 2
Port_5553964_2 | SOURCEANDSINK | 36.01 Tilluft Passasjerhall og kjeller: 2
Port_5553877_1 | SOURCEANDSINK | 36.01 Tilluft Passasjerhall og kjeller: 2
Port_5553880_2 | SOURCEANDSINK | 36.01 Tilluft Passasjerhall og kjeller: 2
Port_5553884_0 | SOURCEANDSINK | 36.01 Tilluft Passasjerhall og kjeller: 2
Port_5553967_2 | SOURCEANDSINK | 36.01 Tilluft Passasjerhall og kjeller: 2
Port_5553884_1 | SOURCEANDSINK | 36.01 Tilluft Passasjerhall og kjeller: 2
Port_5553887_2 | SOURCEANDSINK | 36.01 Tilluft Passasjerhall og kjeller: 2
Port_5553891_0 | SOURCEANDSINK | 36.01 Tilluft Passasjerhall og kjeller: 2
Port_5553970_2 | SOURCEANDSINK | 36.01 Tilluft Passasjerhall og kjeller: 2
Port_5553891_1 | SOURCEANDSINK | 36.01 Tilluft Passasjerhall og kjeller: 2
Port_5553894_2 | SOURCEANDSINK | 36.01 Tilluft Passasjerhall og kjeller: 2
Port_5553898_0 | SOURCEANDSINK | 36.01 Tilluft Passasjerhall og kjeller: 2
Port_5553973_2 | SOURCEANDSINK | 36.01 Tilluft Passasjerhall og kjeller: 2
Port_5553898_1 | SOURCEANDSINK | 36.01 Tilluft Passasjerhall og kjeller: 2
Port_5553901_2 | SOURCEANDSINK | 36.01 Tilluft Passasjerhall og kjeller: 2
Port_5553905_0 | SOURCEANDSINK | 36.01 Tilluft Passasjerhall og kjeller: 2
Port_5553976_2 | SOURCEANDSINK | 36.01 Tilluft Passasjerhall og kjeller: 2
Port_5553905_1 | SOURCEANDSINK | 36.01 Tilluft Passasjerhall og kjeller: 2
Port_5553908_2 | SOURCEANDSINK | 36.01 Tilluft Passasjerhall og kjeller: 2
Port_5553912_0 | SOURCEANDSINK | 36.01 Tilluft Passasjerhall og kjeller: 2
Port_5553979_2 | SOURCEANDSINK | 36.01 Tilluft Passasjerhall og kjeller: 2
Port_5553912_1 | SOURCEANDSINK | 36.01 Tilluft Passasjerhall og kjeller: 2
Port_5553915_2 | SOURCEANDSINK | 36.01 Tilluft Passasjerhall og kjeller: 2
Port_5559981_0 | SOURCEANDSINK | 36.03 Tilluft 1.etg nord og øst + nordfløy: 1
Port_5560016_2 | SOURCEANDSINK | 36.03 Tilluft 1.etg nord og øst + nordfløy: 1
Port_5559981_1 | SOURCEANDSINK | 36.03 Tilluft 1.etg nord og øst + nordfløy: 1
Port_5559984_2 | SOURCEANDSINK | 36.03 Tilluft 1.etg nord og øst + nordfløy: 1
Port_5596789_0 | SOURCEANDSINK | 36.03 Tilluft 1.etg nord og øst + nordfløy: 1
Port_5596818_0 | SOURCEANDSINK | 36.03 Avtrekk 1.etg nord og øst + nordfløy: 1
Port_5596834_1 | SOURCEANDSINK | 36.03 Avtrekk 1.etg nord og øst + nordfløy: 1
Port_5596836_1 | SOURCEANDSINK | 36.03 Avtrekk 1.etg nord og øst + nordfløy: 1
OutPort_5847477_1 | SOURCE | 360.041 Avtrekk Nytt system Nord: 6
OutPort_5846023_1 | SOURCE | 360.041 Avtrekk Nytt system Nord: 6
InPort_5847465_1 | SINK | 360.041 Tilluft Nytt system Nord: 4
InPort_5846449_1 | SINK | 36.02 Tilluft 1.etg syd og vest: 9
InPort_5612071_0 | SINK | 360.041 Tilluft Nytt system Nord: 3
OutPort_5848615_2 | SOURCE | 360.041 Tilluft Nytt system Nord: 3
InPort_5848617_1 | SINK | 360.041 Tilluft Nytt system Nord: 3
OutPort_5612071_1 | SOURCE | 360.041 Tilluft Nytt system Nord: 3
InPort_5845893_1 | SINK | 36.02 Avtrekk 1.etg syd og vest: 5
InPort_5845895_2 | SINK | 36.02 Avtrekk 1.etg syd og vest: 5
OutPort_5845893_0 | SOURCE | 36.02 Avtrekk 1.etg syd og vest: 5
InPort_5845896_1 | SINK | 36.02 Avtrekk 1.etg syd og vest: 5
OutPort_5845895_1 | SOURCE | 36.02 Avtrekk 1.etg syd og vest: 5
InPort_5845898_1 | SINK | 36.02 Avtrekk 1.etg syd og vest: 5
OutPort_5845896_0 | SOURCE | 36.02 Avtrekk 1.etg syd og vest: 5
InPort_5845899_0 | SINK | 36.02 Avtrekk 1.etg syd og vest: 5
OutPort_5845898_2 | SOURCE | 36.02 Avtrekk 1.etg syd og vest: 5
Port_5845898_3 | SOURCEANDSINK
InPort_5846025_1 | SINK | 36.02 Avtrekk 1.etg syd og vest: 5
OutPort_5845899_1 | SOURCE | 36.02 Avtrekk 1.etg syd og vest: 5
InPort_5846023_2 | SINK | 36.02 Avtrekk 1.etg syd og vest: 5
OutPort_5846010_0 | SOURCE | 36.02 Avtrekk 1.etg syd og vest: 5
InPort_5846010_1 | SINK | 36.02 Avtrekk 1.etg syd og vest: 5
OutPort_5846025_2 | SOURCE | 36.02 Avtrekk 1.etg syd og vest: 5
OutPort_5846144_0 | SOURCE | 36.02 Tilluft 1.etg syd og vest: 9
InPort_5846144_1 | SINK | 36.02 Tilluft 1.etg syd og vest: 9
OutPort_5846368_2 | SOURCE | 36.02 Tilluft 1.etg syd og vest: 9
OutPort_5846147_0 | SOURCE | 36.02 Tilluft 1.etg syd og vest: 9
InPort_5846147_0 | SINK | 36.02 Tilluft 1.etg syd og vest: 9
InPort_5846400_2 | SINK | 36.02 Tilluft 1.etg syd og vest: 9
OutPort_5846147_1 | SOURCE | 36.02 Tilluft 1.etg syd og vest: 9
InPort_5846159_2 | SINK | 36.02 Tilluft 1.etg syd og vest: 9
OutPort_5846149_0 | SOURCE | 36.02 Tilluft 1.etg syd og vest: 9
InPort_5846151_1 | SINK | 36.02 Tilluft 1.etg syd og vest: 9
OutPort_5846149_1 | SOURCE | 36.02 Tilluft 1.etg syd og vest: 9
InPort_5846368_1 | SINK | 36.02 Tilluft 1.etg syd og vest: 9
OutPort_5846149_2 | SOURCE | 36.02 Tilluft 1.etg syd og vest: 9
InPort_5846149_3 | SINK | 36.02 Tilluft 1.etg syd og vest: 9
OutPort_5846400_1 | SOURCE | 36.02 Tilluft 1.etg syd og vest: 9
InPort_5846153_0 | SINK | 36.02 Tilluft 1.etg syd og vest: 9
OutPort_5846157_2 | SOURCE | 36.02 Tilluft 1.etg syd og vest: 9
InPort_5846158_2 | SINK | 36.02 Tilluft 1.etg syd og vest: 9
OutPort_5846153_1 | SOURCE | 36.02 Tilluft 1.etg syd og vest: 9
InPort_5846155_0 | SINK | 36.02 Tilluft 1.etg syd og vest: 9
OutPort_5846159_1 | SOURCE | 36.02 Tilluft 1.etg syd og vest: 9
InPort_5846157_1 | SINK | 36.02 Tilluft 1.etg syd og vest: 9
OutPort_5846155_1 | SOURCE | 36.02 Tilluft 1.etg syd og vest: 9
InPort_5846161_0 | SINK | 36.02 Tilluft 1.etg syd og vest: 9
OutPort_5846158_1 | SOURCE | 36.02 Tilluft 1.etg syd og vest: 9
Port_5846158_3 | SOURCEANDSINK
InPort_5846451_2 | SINK | 36.02 Tilluft 1.etg syd og vest: 9
OutPort_5846161_1 | SOURCE | 36.02 Tilluft 1.etg syd og vest: 9
InPort_5846449_2 | SINK | 36.02 Tilluft 1.etg syd og vest: 9
OutPort_5846441_0 | SOURCE | 36.02 Tilluft 1.etg syd og vest: 9
InPort_5846441_1 | SINK | 36.02 Tilluft 1.etg syd og vest: 9
OutPort_5846451_1 | SOURCE | 36.02 Tilluft 1.etg syd og vest: 9
OutPort_5847973_1 | SOURCE | 36.02 Tilluft 1.etg syd og vest: 14
InPort_5847794_2 | SINK | 360.041 Tilluft Nytt system Nord: 3
OutPort_5847791_0 | SOURCE | 360.041 Tilluft Nytt system Nord: 3
InPort_5847791_1 | SINK | 360.041 Tilluft Nytt system Nord: 3
InPort_5848581_0 | SINK | 360.041 Tilluft Nytt system Nord: 3
OutPort_5847794_1 | SOURCE | 360.041 Tilluft Nytt system Nord: 3
InPort_5848617_2 | SINK | 360.041 Tilluft Nytt system Nord: 3
OutPort_5847973_0 | SOURCE | 360.041 Tilluft Nytt system Nord: 3
OutPort_5848035_0 | SOURCE | 36.02 Tilluft 1.etg syd og vest: 16
InPort_5848035_0 | SINK | 36.02 Tilluft 1.etg syd og vest: 16
InPort_5848537_2 | SINK | 36.02 Tilluft 1.etg syd og vest: 16
OutPort_5848035_1 | SOURCE | 36.02 Tilluft 1.etg syd og vest: 16
InPort_5848581_2 | SINK | 360.041 Tilluft Nytt system Nord: 3
OutPort_5848537_1 | SOURCE | 360.041 Tilluft Nytt system Nord: 3
InPort_5848615_1 | SINK | 360.041 Tilluft Nytt system Nord: 3
OutPort_5848581_1 | SOURCE | 360.041 Tilluft Nytt system Nord: 3
InPort_5514180_1 | SINK | 3320.001.01 Brannslokking Sprinkler våt 182
OutPort_5514183_2 | SOURCE | 3320.001.01 Brannslokking Sprinkler våt 182
Port_5514181_0 | SOURCEANDSINK | 3320.001.01 Brannslokking Sprinkler våt 182
Port_5514200_2 | SOURCEANDSINK | 3320.001.01 Brannslokking Sprinkler våt 182
Port_5514181_1 | SOURCEANDSINK | 3320.001.01 Brannslokking Sprinkler våt 182
Port_5514183_1 | SOURCEANDSINK | 3320.001.01 Brannslokking Sprinkler våt 182
Port_5514202_2 | SOURCEANDSINK | 3320.001.01 Brannslokking Sprinkler våt 182
Port_5514198_2 | SOURCEANDSINK | 3320.001.01 Brannslokking Sprinkler våt 182
Port_5514202_1 | SOURCEANDSINK | 3320.001.01 Brannslokking Sprinkler våt 182
Port_5514198_3 | SOURCEANDSINK | 3320.001.01 Brannslokking Sprinkler våt 182
Port_5514200_1 | SOURCEANDSINK | 3320.001.01 Brannslokking Sprinkler våt 182
Port_5514198_4 | SOURCEANDSINK | 3320.001.01 Brannslokking Sprinkler våt 182
Port_5514230_1 | SOURCEANDSINK | 3320.001.01 Brannslokking Sprinkler våt 182
InPort_5514204_1 | SINK | 3320.001.01 Brannslokking Sprinkler våt 182
OutPort_5514207_2 | SOURCE | 3320.001.01 Brannslokking Sprinkler våt 182
Port_5514205_0 | SOURCEANDSINK | 3320.001.01 Brannslokking Sprinkler våt 182
Port_5514228_2 | SOURCEANDSINK | 3320.001.01 Brannslokking Sprinkler våt 182
Port_5514205_1 | SOURCEANDSINK | 3320.001.01 Brannslokking Sprinkler våt 182
Port_5514207_1 | SOURCEANDSINK | 3320.001.01 Brannslokking Sprinkler våt 182
Port_5514226_2 | SOURCEANDSINK | 3320.001.01 Brannslokking Sprinkler våt 182
Port_5514222_0 | SOURCEANDSINK | 3320.001.01 Brannslokking Sprinkler våt 182
Port_5514224_4 | SOURCEANDSINK | 3320.001.01 Brannslokking Sprinkler våt 182
Port_5514222_1 | SOURCEANDSINK | 3320.001.01 Brannslokking Sprinkler våt 182
Port_5514250_5 | SOURCEANDSINK | 3320.001.01 Brannslokking Sprinkler våt 182
Port_5514224_1 | SOURCEANDSINK | 3320.001.01 Brannslokking Sprinkler våt 182
Port_5514226_1 | SOURCEANDSINK | 3320.001.01 Brannslokking Sprinkler våt 182
Port_5514224_3 | SOURCEANDSINK | 3320.001.01 Brannslokking Sprinkler våt 182
Port_5514228_1 | SOURCEANDSINK | 3320.001.01 Brannslokking Sprinkler våt 182
Port_5514224_5 | SOURCEANDSINK | 3320.001.01 Brannslokking Sprinkler våt 182
Port_5514230_0 | SOURCEANDSINK | 3320.001.01 Brannslokking Sprinkler våt 182
InPort_5514232_1 | SINK | 3320.001.01 Brannslokking Sprinkler våt 182
OutPort_5514235_2 | SOURCE | 3320.001.01 Brannslokking Sprinkler våt 182
Port_5514233_0 | SOURCEANDSINK | 3320.001.01 Brannslokking Sprinkler våt 182
Port_5514254_2 | SOURCEANDSINK | 3320.001.01 Brannslokking Sprinkler våt 182
Port_5514233_1 | SOURCEANDSINK | 3320.001.01 Brannslokking Sprinkler våt 182
Port_5514235_1 | SOURCEANDSINK | 3320.001.01 Brannslokking Sprinkler våt 182
Port_5514252_2 | SOURCEANDSINK | 3320.001.01 Brannslokking Sprinkler våt 182
Port_5514250_1 | SOURCEANDSINK | 3320.001.01 Brannslokking Sprinkler våt 182
Port_5514252_1 | SOURCEANDSINK | 3320.001.01 Brannslokking Sprinkler våt 182
Port_5514250_3 | SOURCEANDSINK | 3320.001.01 Brannslokking Sprinkler våt 182
Port_5514254_1 | SOURCEANDSINK | 3320.001.01 Brannslokking Sprinkler våt 182
Port_5514250_4 | SOURCEANDSINK | 3320.001.01 Brannslokking Sprinkler våt 182
Port_5514266_0 | SOURCEANDSINK | 3320.001.01 Brannslokking Sprinkler våt 182
Port_5514589_2 | SOURCEANDSINK | 3320.001.01 Brannslokking Sprinkler våt 182
Port_5514261_0 | SOURCEANDSINK | 3320.001.01 Brannslokking Sprinkler våt 182
Port_5514589_1 | SOURCEANDSINK | 3320.001.01 Brannslokking Sprinkler våt 182
Port_5514261_1 | SOURCEANDSINK | 3320.001.01 Brannslokking Sprinkler våt 182
Port_5514265_4 | SOURCEANDSINK | 3320.001.01 Brannslokking Sprinkler våt 182
Port_5514265_2 | SOURCEANDSINK | 3320.001.01 Brannslokking Sprinkler våt 182
Port_5514290_0 | SOURCEANDSINK | 3320.001.01 Brannslokking Sprinkler våt 182
Port_5514265_3 | SOURCEANDSINK | 3320.001.01 Brannslokking Sprinkler våt 182
Port_5514273_1 | SOURCEANDSINK | 3320.001.01 Brannslokking Sprinkler våt 182
Port_5514266_1 | SOURCEANDSINK | 3320.001.01 Brannslokking Sprinkler våt 182
Port_5514273_2 | SOURCEANDSINK | 3320.001.01 Brannslokking Sprinkler våt 182
Port_5514670_2 | SOURCEANDSINK | 3320.001.01 Brannslokking Sprinkler våt 182
Port_5514280_0 | SOURCEANDSINK | 3320.001.01 Brannslokking Sprinkler våt 182
Port_5514670_1 | SOURCEANDSINK | 3320.001.01 Brannslokking Sprinkler våt 182
Port_5514280_1 | SOURCEANDSINK | 3320.001.01 Brannslokking Sprinkler våt 182
Port_5514284_4 | SOURCEANDSINK | 3320.001.01 Brannslokking Sprinkler våt 182
Port_5514284_2 | SOURCEANDSINK | 3320.001.01 Brannslokking Sprinkler våt 182
Port_5514292_0 | SOURCEANDSINK | 3320.001.01 Brannslokking Sprinkler våt 182
Port_5514284_3 | SOURCEANDSINK | 3320.001.01 Brannslokking Sprinkler våt 182
Port_5514290_1 | SOURCEANDSINK | 3320.001.01 Brannslokking Sprinkler våt 182
Port_5514292_1 | SOURCEANDSINK | 3320.001.01 Brannslokking Sprinkler våt 182
Port_5514309_2 | SOURCEANDSINK | 3320.001.01 Brannslokking Sprinkler våt 191
Port_5514307_0 | SOURCEANDSINK | 3320.001.01 Brannslokking Sprinkler våt 191
Port_5514309_1 | SOURCEANDSINK | 3320.001.01 Brannslokking Sprinkler våt 191
Port_5514307_1 | SOURCEANDSINK | 3320.001.01 Brannslokking Sprinkler våt 191
InPort_5514732_1 | SINK | 3320.001.01 Brannslokking Sprinkler våt 183
OutPort_5514735_2 | SOURCE | 3320.001.01 Brannslokking Sprinkler våt 183
Port_5514733_0 | SOURCEANDSINK | 3320.001.01 Brannslokking Sprinkler våt 183
Port_5514752_2 | SOURCEANDSINK | 3320.001.01 Brannslokking Sprinkler våt 183
Port_5514733_1 | SOURCEANDSINK | 3320.001.01 Brannslokking Sprinkler våt 183
Port_5514735_1 | SOURCEANDSINK | 3320.001.01 Brannslokking Sprinkler våt 183
Port_5514754_2 | SOURCEANDSINK | 3320.001.01 Brannslokking Sprinkler våt 183
Port_5514750_2 | SOURCEANDSINK | 3320.001.01 Brannslokking Sprinkler våt 183
Port_5514754_1 | SOURCEANDSINK | 3320.001.01 Brannslokking Sprinkler våt 183
Port_5514750_3 | SOURCEANDSINK | 3320.001.01 Brannslokking Sprinkler våt 183
Port_5514752_1 | SOURCEANDSINK | 3320.001.01 Brannslokking Sprinkler våt 183
Port_5514750_4 | SOURCEANDSINK | 3320.001.01 Brannslokking Sprinkler våt 183
Port_5514782_1 | SOURCEANDSINK | 3320.001.01 Brannslokking Sprinkler våt 183
InPort_5514756_1 | SINK | 3320.001.01 Brannslokking Sprinkler våt 183
OutPort_5514759_2 | SOURCE | 3320.001.01 Brannslokking Sprinkler våt 183
Port_5514757_0 | SOURCEANDSINK | 3320.001.01 Brannslokking Sprinkler våt 183
Port_5514780_2 | SOURCEANDSINK | 3320.001.01 Brannslokking Sprinkler våt 183
Port_5514757_1 | SOURCEANDSINK | 3320.001.01 Brannslokking Sprinkler våt 183
Port_5514759_1 | SOURCEANDSINK | 3320.001.01 Brannslokking Sprinkler våt 183
Port_5514778_2 | SOURCEANDSINK | 3320.001.01 Brannslokking Sprinkler våt 183
Port_5514774_0 | SOURCEANDSINK | 3320.001.01 Brannslokking Sprinkler våt 183
Port_5514776_4 | SOURCEANDSINK | 3320.001.01 Brannslokking Sprinkler våt 183
Port_5514774_1 | SOURCEANDSINK | 3320.001.01 Brannslokking Sprinkler våt 183
Port_5514802_5 | SOURCEANDSINK | 3320.001.01 Brannslokking Sprinkler våt 183
Port_5514776_1 | SOURCEANDSINK | 3320.001.01 Brannslokking Sprinkler våt 183
Port_5514778_1 | SOURCEANDSINK | 3320.001.01 Brannslokking Sprinkler våt 183
Port_5514776_3 | SOURCEANDSINK | 3320.001.01 Brannslokking Sprinkler våt 183
Port_5514780_1 | SOURCEANDSINK | 3320.001.01 Brannslokking Sprinkler våt 183
Port_5514776_5 | SOURCEANDSINK | 3320.001.01 Brannslokking Sprinkler våt 183
Port_5514782_0 | SOURCEANDSINK | 3320.001.01 Brannslokking Sprinkler våt 183
InPort_5514784_1 | SINK | 3320.001.01 Brannslokking Sprinkler våt 183
OutPort_5514787_2 | SOURCE | 3320.001.01 Brannslokking Sprinkler våt 183
Port_5514785_0 | SOURCEANDSINK | 3320.001.01 Brannslokking Sprinkler våt 183
Port_5514806_2 | SOURCEANDSINK | 3320.001.01 Brannslokking Sprinkler våt 183
Port_5514785_1 | SOURCEANDSINK | 3320.001.01 Brannslokking Sprinkler våt 183
Port_5514787_1 | SOURCEANDSINK | 3320.001.01 Brannslokking Sprinkler våt 183
Port_5514804_2 | SOURCEANDSINK | 3320.001.01 Brannslokking Sprinkler våt 183
Port_5514802_1 | SOURCEANDSINK | 3320.001.01 Brannslokking Sprinkler våt 183
Port_5514804_1 | SOURCEANDSINK | 3320.001.01 Brannslokking Sprinkler våt 183
Port_5514802_3 | SOURCEANDSINK | 3320.001.01 Brannslokking Sprinkler våt 183
Port_5514806_1 | SOURCEANDSINK | 3320.001.01 Brannslokking Sprinkler våt 183
Port_5514802_4 | SOURCEANDSINK | 3320.001.01 Brannslokking Sprinkler våt 183
Port_5514816_0 | SOURCEANDSINK | 3320.001.01 Brannslokking Sprinkler våt 183
Port_5514851_2 | SOURCEANDSINK | 3320.001.01 Brannslokking Sprinkler våt 183
Port_5514813_0 | SOURCEANDSINK | 3320.001.01 Brannslokking Sprinkler våt 183
Port_5514851_1 | SOURCEANDSINK | 3320.001.01 Brannslokking Sprinkler våt 183
Port_5514813_1 | SOURCEANDSINK | 3320.001.01 Brannslokking Sprinkler våt 183
Port_5514815_4 | SOURCEANDSINK | 3320.001.01 Brannslokking Sprinkler våt 183
Port_5514815_2 | SOURCEANDSINK | 3320.001.01 Brannslokking Sprinkler våt 183
Port_5514830_0 | SOURCEANDSINK | 3320.001.01 Brannslokking Sprinkler våt 183
Port_5514815_3 | SOURCEANDSINK | 3320.001.01 Brannslokking Sprinkler våt 183
Port_5514819_1 | SOURCEANDSINK | 3320.001.01 Brannslokking Sprinkler våt 183
Port_5514816_1 | SOURCEANDSINK | 3320.001.01 Brannslokking Sprinkler våt 183
Port_5514819_2 | SOURCEANDSINK | 3320.001.01 Brannslokking Sprinkler våt 183
Port_5514853_2 | SOURCEANDSINK | 3320.001.01 Brannslokking Sprinkler våt 183
Port_5514826_0 | SOURCEANDSINK | 3320.001.01 Brannslokking Sprinkler våt 183
Port_5514853_1 | SOURCEANDSINK | 3320.001.01 Brannslokking Sprinkler våt 183
Port_5514826_1 | SOURCEANDSINK | 3320.001.01 Brannslokking Sprinkler våt 183
Port_5514828_4 | SOURCEANDSINK | 3320.001.01 Brannslokking Sprinkler våt 183
Port_5514828_2 | SOURCEANDSINK | 3320.001.01 Brannslokking Sprinkler våt 183
Port_5514832_0 | SOURCEANDSINK | 3320.001.01 Brannslokking Sprinkler våt 183
Port_5514828_3 | SOURCEANDSINK | 3320.001.01 Brannslokking Sprinkler våt 183
Port_5514830_1 | SOURCEANDSINK | 3320.001.01 Brannslokking Sprinkler våt 183
Port_5514832_1 | SOURCEANDSINK | 3320.001.01 Brannslokking Sprinkler våt 183
Port_5514849_2 | SOURCEANDSINK | 3320.001.01 Brannslokking Sprinkler våt 193
Port_5514847_0 | SOURCEANDSINK | 3320.001.01 Brannslokking Sprinkler våt 193
Port_5514849_1 | SOURCEANDSINK | 3320.001.01 Brannslokking Sprinkler våt 193
Port_5514847_1 | SOURCEANDSINK | 3320.001.01 Brannslokking Sprinkler våt 193
InPort_5514875_1 | SINK | 3320.001.01 Brannslokking Sprinkler våt 184
OutPort_5514878_2 | SOURCE | 3320.001.01 Brannslokking Sprinkler våt 184
Port_5514876_0 | SOURCEANDSINK | 3320.001.01 Brannslokking Sprinkler våt 184
Port_5514895_2 | SOURCEANDSINK | 3320.001.01 Brannslokking Sprinkler våt 184
Port_5514876_1 | SOURCEANDSINK | 3320.001.01 Brannslokking Sprinkler våt 184
Port_5514878_1 | SOURCEANDSINK | 3320.001.01 Brannslokking Sprinkler våt 184
Port_5514897_2 | SOURCEANDSINK | 3320.001.01 Brannslokking Sprinkler våt 184
Port_5514893_2 | SOURCEANDSINK | 3320.001.01 Brannslokking Sprinkler våt 184
Port_5514897_1 | SOURCEANDSINK | 3320.001.01 Brannslokking Sprinkler våt 184
Port_5514893_3 | SOURCEANDSINK | 3320.001.01 Brannslokking Sprinkler våt 184
Port_5514895_1 | SOURCEANDSINK | 3320.001.01 Brannslokking Sprinkler våt 184
Port_5514893_4 | SOURCEANDSINK | 3320.001.01 Brannslokking Sprinkler våt 184
Port_5514925_1 | SOURCEANDSINK | 3320.001.01 Brannslokking Sprinkler våt 184
InPort_5514899_1 | SINK | 3320.001.01 Brannslokking Sprinkler våt 184
OutPort_5514902_2 | SOURCE | 3320.001.01 Brannslokking Sprinkler våt 184
Port_5514900_0 | SOURCEANDSINK | 3320.001.01 Brannslokking Sprinkler våt 184
Port_5514923_2 | SOURCEANDSINK | 3320.001.01 Brannslokking Sprinkler våt 184
Port_5514900_1 | SOURCEANDSINK | 3320.001.01 Brannslokking Sprinkler våt 184
Port_5514902_1 | SOURCEANDSINK | 3320.001.01 Brannslokking Sprinkler våt 184
Port_5514921_2 | SOURCEANDSINK | 3320.001.01 Brannslokking Sprinkler våt 184
Port_5514917_0 | SOURCEANDSINK | 3320.001.01 Brannslokking Sprinkler våt 184
Port_5514919_4 | SOURCEANDSINK | 3320.001.01 Brannslokking Sprinkler våt 184
Port_5514917_1 | SOURCEANDSINK | 3320.001.01 Brannslokking Sprinkler våt 184
Port_5514945_5 | SOURCEANDSINK | 3320.001.01 Brannslokking Sprinkler våt 184
Port_5514919_1 | SOURCEANDSINK | 3320.001.01 Brannslokking Sprinkler våt 184
Port_5514921_1 | SOURCEANDSINK | 3320.001.01 Brannslokking Sprinkler våt 184
Port_5514919_3 | SOURCEANDSINK | 3320.001.01 Brannslokking Sprinkler våt 184
Port_5514923_1 | SOURCEANDSINK | 3320.001.01 Brannslokking Sprinkler våt 184
Port_5514919_5 | SOURCEANDSINK | 3320.001.01 Brannslokking Sprinkler våt 184
Port_5514925_0 | SOURCEANDSINK | 3320.001.01 Brannslokking Sprinkler våt 184
InPort_5514927_1 | SINK | 3320.001.01 Brannslokking Sprinkler våt 184
OutPort_5514930_2 | SOURCE | 3320.001.01 Brannslokking Sprinkler våt 184
Port_5514928_0 | SOURCEANDSINK | 3320.001.01 Brannslokking Sprinkler våt 184
Port_5514949_2 | SOURCEANDSINK | 3320.001.01 Brannslokking Sprinkler våt 184
Port_5514928_1 | SOURCEANDSINK | 3320.001.01 Brannslokking Sprinkler våt 184
Port_5514930_1 | SOURCEANDSINK | 3320.001.01 Brannslokking Sprinkler våt 184
Port_5514947_2 | SOURCEANDSINK | 3320.001.01 Brannslokking Sprinkler våt 184
Port_5514945_1 | SOURCEANDSINK | 3320.001.01 Brannslokking Sprinkler våt 184
Port_5514947_1 | SOURCEANDSINK | 3320.001.01 Brannslokking Sprinkler våt 184
Port_5514945_3 | SOURCEANDSINK | 3320.001.01 Brannslokking Sprinkler våt 184
Port_5514949_1 | SOURCEANDSINK | 3320.001.01 Brannslokking Sprinkler våt 184
Port_5514945_4 | SOURCEANDSINK | 3320.001.01 Brannslokking Sprinkler våt 184
Port_5514959_0 | SOURCEANDSINK | 3320.001.01 Brannslokking Sprinkler våt 184
Port_5514994_2 | SOURCEANDSINK | 3320.001.01 Brannslokking Sprinkler våt 184
Port_5514956_0 | SOURCEANDSINK | 3320.001.01 Brannslokking Sprinkler våt 184
Port_5514994_1 | SOURCEANDSINK | 3320.001.01 Brannslokking Sprinkler våt 184
Port_5514956_1 | SOURCEANDSINK | 3320.001.01 Brannslokking Sprinkler våt 184
Port_5514958_4 | SOURCEANDSINK | 3320.001.01 Brannslokking Sprinkler våt 184
Port_5514958_2 | SOURCEANDSINK | 3320.001.01 Brannslokking Sprinkler våt 184
Port_5514973_0 | SOURCEANDSINK | 3320.001.01 Brannslokking Sprinkler våt 184
Port_5514958_3 | SOURCEANDSINK | 3320.001.01 Brannslokking Sprinkler våt 184
Port_5514962_1 | SOURCEANDSINK | 3320.001.01 Brannslokking Sprinkler våt 184
Port_5514959_1 | SOURCEANDSINK | 3320.001.01 Brannslokking Sprinkler våt 184
Port_5514962_2 | SOURCEANDSINK | 3320.001.01 Brannslokking Sprinkler våt 184
Port_5514996_2 | SOURCEANDSINK | 3320.001.01 Brannslokking Sprinkler våt 184
Port_5514969_0 | SOURCEANDSINK | 3320.001.01 Brannslokking Sprinkler våt 184
Port_5514996_1 | SOURCEANDSINK | 3320.001.01 Brannslokking Sprinkler våt 184
Port_5514969_1 | SOURCEANDSINK | 3320.001.01 Brannslokking Sprinkler våt 184
Port_5514971_4 | SOURCEANDSINK | 3320.001.01 Brannslokking Sprinkler våt 184
Port_5514971_2 | SOURCEANDSINK | 3320.001.01 Brannslokking Sprinkler våt 184
Port_5514975_0 | SOURCEANDSINK | 3320.001.01 Brannslokking Sprinkler våt 184
Port_5514971_3 | SOURCEANDSINK | 3320.001.01 Brannslokking Sprinkler våt 184
Port_5514973_1 | SOURCEANDSINK | 3320.001.01 Brannslokking Sprinkler våt 184
Port_5514975_1 | SOURCEANDSINK | 3320.001.01 Brannslokking Sprinkler våt 184
Port_5514992_2 | SOURCEANDSINK | 3320.001.01 Brannslokking Sprinkler våt 195
Port_5514990_0 | SOURCEANDSINK | 3320.001.01 Brannslokking Sprinkler våt 195
Port_5514992_1 | SOURCEANDSINK | 3320.001.01 Brannslokking Sprinkler våt 195
Port_5514990_1 | SOURCEANDSINK | 3320.001.01 Brannslokking Sprinkler våt 195
InPort_5515016_1 | SINK | 3320.001.01 Brannslokking Sprinkler våt 185
OutPort_5515019_2 | SOURCE | 3320.001.01 Brannslokking Sprinkler våt 185
Port_5515017_0 | SOURCEANDSINK | 3320.001.01 Brannslokking Sprinkler våt 185
Port_5515036_2 | SOURCEANDSINK | 3320.001.01 Brannslokking Sprinkler våt 185
Port_5515017_1 | SOURCEANDSINK | 3320.001.01 Brannslokking Sprinkler våt 185
Port_5515019_1 | SOURCEANDSINK | 3320.001.01 Brannslokking Sprinkler våt 185
Port_5515038_2 | SOURCEANDSINK | 3320.001.01 Brannslokking Sprinkler våt 185
Port_5515034_2 | SOURCEANDSINK | 3320.001.01 Brannslokking Sprinkler våt 185
Port_5515038_1 | SOURCEANDSINK | 3320.001.01 Brannslokking Sprinkler våt 185
Port_5515034_3 | SOURCEANDSINK | 3320.001.01 Brannslokking Sprinkler våt 185
Port_5515036_1 | SOURCEANDSINK | 3320.001.01 Brannslokking Sprinkler våt 185
Port_5515034_4 | SOURCEANDSINK | 3320.001.01 Brannslokking Sprinkler våt 185
Port_5515066_1 | SOURCEANDSINK | 3320.001.01 Brannslokking Sprinkler våt 185
InPort_5515040_1 | SINK | 3320.001.01 Brannslokking Sprinkler våt 185
OutPort_5515043_2 | SOURCE | 3320.001.01 Brannslokking Sprinkler våt 185
Port_5515041_0 | SOURCEANDSINK | 3320.001.01 Brannslokking Sprinkler våt 185
Port_5515064_2 | SOURCEANDSINK | 3320.001.01 Brannslokking Sprinkler våt 185
Port_5515041_1 | SOURCEANDSINK | 3320.001.01 Brannslokking Sprinkler våt 185
Port_5515043_1 | SOURCEANDSINK | 3320.001.01 Brannslokking Sprinkler våt 185
Port_5515062_2 | SOURCEANDSINK | 3320.001.01 Brannslokking Sprinkler våt 185
Port_5515058_0 | SOURCEANDSINK | 3320.001.01 Brannslokking Sprinkler våt 185
Port_5515060_4 | SOURCEANDSINK | 3320.001.01 Brannslokking Sprinkler våt 185
Port_5515058_1 | SOURCEANDSINK | 3320.001.01 Brannslokking Sprinkler våt 185
Port_5515086_5 | SOURCEANDSINK | 3320.001.01 Brannslokking Sprinkler våt 185
Port_5515060_1 | SOURCEANDSINK | 3320.001.01 Brannslokking Sprinkler våt 185
Port_5515062_1 | SOURCEANDSINK | 3320.001.01 Brannslokking Sprinkler våt 185
Port_5515060_3 | SOURCEANDSINK | 3320.001.01 Brannslokking Sprinkler våt 185
Port_5515064_1 | SOURCEANDSINK | 3320.001.01 Brannslokking Sprinkler våt 185
Port_5515060_5 | SOURCEANDSINK | 3320.001.01 Brannslokking Sprinkler våt 185
Port_5515066_0 | SOURCEANDSINK | 3320.001.01 Brannslokking Sprinkler våt 185
InPort_5515068_1 | SINK | 3320.001.01 Brannslokking Sprinkler våt 185
OutPort_5515071_2 | SOURCE | 3320.001.01 Brannslokking Sprinkler våt 185
Port_5515069_0 | SOURCEANDSINK | 3320.001.01 Brannslokking Sprinkler våt 185
Port_5515090_2 | SOURCEANDSINK | 3320.001.01 Brannslokking Sprinkler våt 185
Port_5515069_1 | SOURCEANDSINK | 3320.001.01 Brannslokking Sprinkler våt 185
Port_5515071_1 | SOURCEANDSINK | 3320.001.01 Brannslokking Sprinkler våt 185
Port_5515088_2 | SOURCEANDSINK | 3320.001.01 Brannslokking Sprinkler våt 185
Port_5515086_1 | SOURCEANDSINK | 3320.001.01 Brannslokking Sprinkler våt 185
Port_5515088_1 | SOURCEANDSINK | 3320.001.01 Brannslokking Sprinkler våt 185
Port_5515086_3 | SOURCEANDSINK | 3320.001.01 Brannslokking Sprinkler våt 185
Port_5515090_1 | SOURCEANDSINK | 3320.001.01 Brannslokking Sprinkler våt 185
Port_5515086_4 | SOURCEANDSINK | 3320.001.01 Brannslokking Sprinkler våt 185
Port_5515100_0 | SOURCEANDSINK | 3320.001.01 Brannslokking Sprinkler våt 185
Port_5515135_2 | SOURCEANDSINK | 3320.001.01 Brannslokking Sprinkler våt 185
Port_5515097_0 | SOURCEANDSINK | 3320.001.01 Brannslokking Sprinkler våt 185
Port_5515135_1 | SOURCEANDSINK | 3320.001.01 Brannslokking Sprinkler våt 185
Port_5515097_1 | SOURCEANDSINK | 3320.001.01 Brannslokking Sprinkler våt 185
Port_5515099_4 | SOURCEANDSINK | 3320.001.01 Brannslokking Sprinkler våt 185
Port_5515099_2 | SOURCEANDSINK | 3320.001.01 Brannslokking Sprinkler våt 185
Port_5515114_0 | SOURCEANDSINK | 3320.001.01 Brannslokking Sprinkler våt 185
Port_5515099_3 | SOURCEANDSINK | 3320.001.01 Brannslokking Sprinkler våt 185
Port_5515103_1 | SOURCEANDSINK | 3320.001.01 Brannslokking Sprinkler våt 185
Port_5515100_1 | SOURCEANDSINK | 3320.001.01 Brannslokking Sprinkler våt 185
Port_5515103_2 | SOURCEANDSINK | 3320.001.01 Brannslokking Sprinkler våt 185
Port_5515137_2 | SOURCEANDSINK | 3320.001.01 Brannslokking Sprinkler våt 185
Port_5515110_0 | SOURCEANDSINK | 3320.001.01 Brannslokking Sprinkler våt 185
Port_5515137_1 | SOURCEANDSINK | 3320.001.01 Brannslokking Sprinkler våt 185
Port_5515110_1 | SOURCEANDSINK | 3320.001.01 Brannslokking Sprinkler våt 185
Port_5515112_4 | SOURCEANDSINK | 3320.001.01 Brannslokking Sprinkler våt 185
Port_5515112_2 | SOURCEANDSINK | 3320.001.01 Brannslokking Sprinkler våt 185
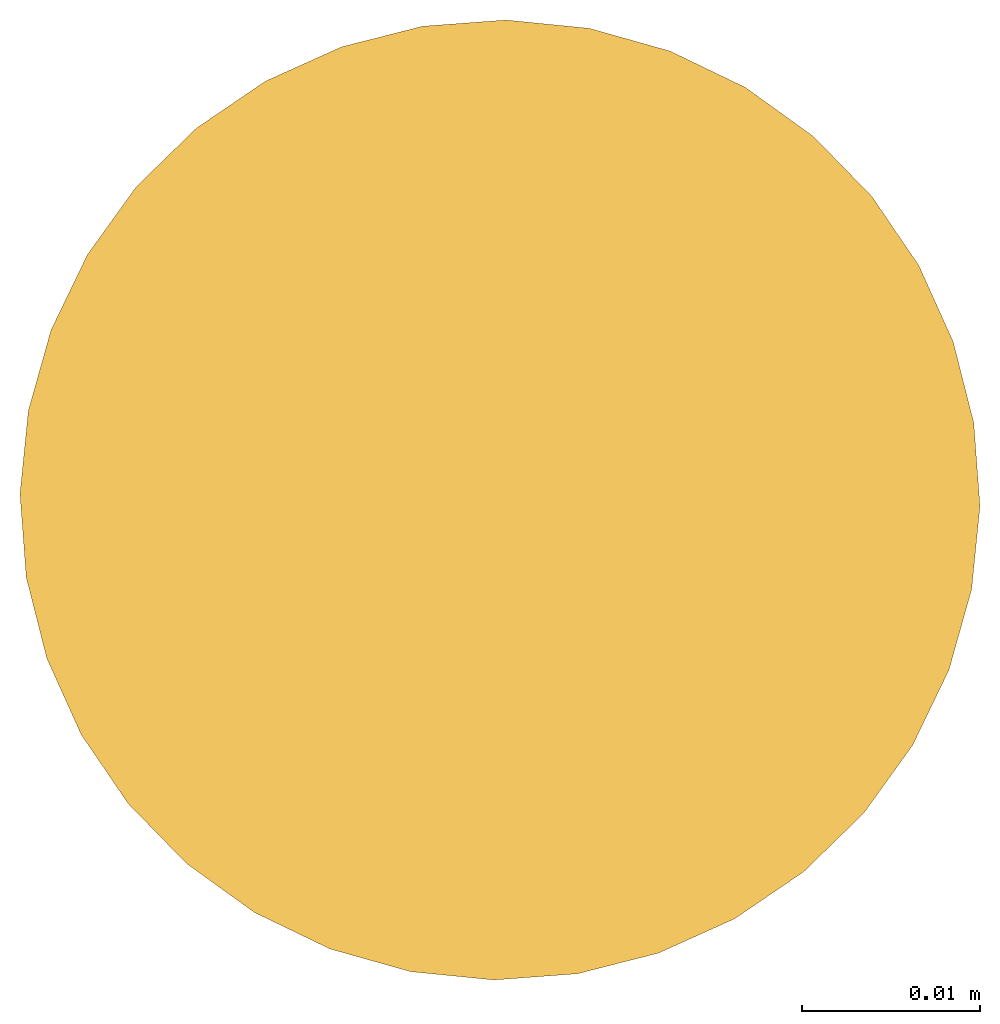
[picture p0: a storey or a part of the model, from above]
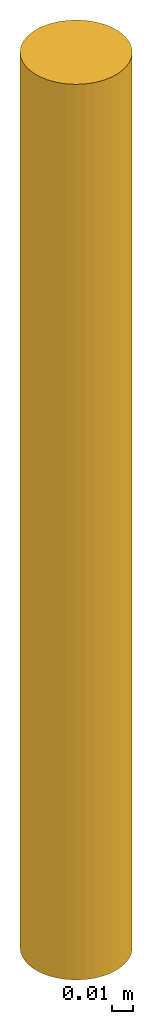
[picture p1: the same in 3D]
Properties of the parts of a building model (IFC2X3), part 2 of 3

# IfcDistributionPort (732)
Name | FlowDirection | Group
Port_5515116_0 | SOURCEANDSINK | 3320.001.01 Brannslokking Sprinkler våt 185
Port_5515112_3 | SOURCEANDSINK | 3320.001.01 Brannslokking Sprinkler våt 185
Port_5515114_1 | SOURCEANDSINK | 3320.001.01 Brannslokking Sprinkler våt 185
Port_5515116_1 | SOURCEANDSINK | 3320.001.01 Brannslokking Sprinkler våt 185
Port_5515133_2 | SOURCEANDSINK | 3320.001.01 Brannslokking Sprinkler våt 197
Port_5515131_0 | SOURCEANDSINK | 3320.001.01 Brannslokking Sprinkler våt 197
Port_5515133_1 | SOURCEANDSINK | 3320.001.01 Brannslokking Sprinkler våt 197
Port_5515131_1 | SOURCEANDSINK | 3320.001.01 Brannslokking Sprinkler våt 197
Port_5517237_2 | SOURCEANDSINK | 3320.001.01 Brannslokking Sprinkler våt 2
Port_5517231_0 | SOURCEANDSINK | 3320.001.01 Brannslokking Sprinkler våt 2
Port_5517237_1 | SOURCEANDSINK | 3320.001.01 Brannslokking Sprinkler våt 2
Port_5517231_1 | SOURCEANDSINK | 3320.001.01 Brannslokking Sprinkler våt 2
Port_5517251_1 | SOURCEANDSINK | 3320.001.01 Brannslokking Sprinkler våt 2
Port_5517251_2 | SOURCEANDSINK | 3320.001.01 Brannslokking Sprinkler våt 2
Port_5520873_2 | SOURCEANDSINK | 3320.001.01 Brannslokking Sprinkler våt 210
Port_5520869_0 | SOURCEANDSINK | 3320.001.01 Brannslokking Sprinkler våt 210
Port_5520871_4 | SOURCEANDSINK | 3320.001.01 Brannslokking Sprinkler våt 210
Port_5520869_1 | SOURCEANDSINK | 3320.001.01 Brannslokking Sprinkler våt 210
Port_5520873_1 | SOURCEANDSINK | 3320.001.01 Brannslokking Sprinkler våt 210
Port_5520871_2 | SOURCEANDSINK | 3320.001.01 Brannslokking Sprinkler våt 210
Port_5520916_1 | SOURCEANDSINK | 3320.001.01 Brannslokking Sprinkler våt 210
Port_5520871_3 | SOURCEANDSINK | 3320.001.01 Brannslokking Sprinkler våt 210
Port_5521235_0 | SOURCEANDSINK | 3320.001.01 Brannslokking Sprinkler våt 210
Port_5520886_2 | SOURCEANDSINK | 3320.001.01 Brannslokking Sprinkler våt 210
Port_5520882_0 | SOURCEANDSINK | 3320.001.01 Brannslokking Sprinkler våt 210
Port_5520884_4 | SOURCEANDSINK | 3320.001.01 Brannslokking Sprinkler våt 210
Port_5520882_1 | SOURCEANDSINK | 3320.001.01 Brannslokking Sprinkler våt 210
Port_5520886_1 | SOURCEANDSINK | 3320.001.01 Brannslokking Sprinkler våt 210
Port_5520884_2 | SOURCEANDSINK | 3320.001.01 Brannslokking Sprinkler våt 210
Port_5521225_1 | SOURCEANDSINK | 3320.001.01 Brannslokking Sprinkler våt 210
Port_5520884_3 | SOURCEANDSINK | 3320.001.01 Brannslokking Sprinkler våt 210
Port_5520916_0 | SOURCEANDSINK | 3320.001.01 Brannslokking Sprinkler våt 210
Port_5521225_2 | SOURCEANDSINK | 3320.001.01 Brannslokking Sprinkler våt 210
Port_5521235_1 | SOURCEANDSINK | 3320.001.01 Brannslokking Sprinkler våt 210
Port_5521252_2 | SOURCEANDSINK | 3320.001.01 Brannslokking Sprinkler våt 210
Port_5521241_0 | SOURCEANDSINK | 3320.001.01 Brannslokking Sprinkler våt 210
Port_5521252_1 | SOURCEANDSINK | 3320.001.01 Brannslokking Sprinkler våt 210
Port_5521241_1 | SOURCEANDSINK | 3320.001.01 Brannslokking Sprinkler våt 210
Port_5521336_2 | SOURCEANDSINK | 3320.001.01 Brannslokking Sprinkler våt 212
Port_5521332_0 | SOURCEANDSINK | 3320.001.01 Brannslokking Sprinkler våt 212
Port_5521334_4 | SOURCEANDSINK | 3320.001.01 Brannslokking Sprinkler våt 212
Port_5521332_1 | SOURCEANDSINK | 3320.001.01 Brannslokking Sprinkler våt 212
Port_5521336_1 | SOURCEANDSINK | 3320.001.01 Brannslokking Sprinkler våt 212
Port_5521334_2 | SOURCEANDSINK | 3320.001.01 Brannslokking Sprinkler våt 212
Port_5521375_1 | SOURCEANDSINK | 3320.001.01 Brannslokking Sprinkler våt 212
Port_5521334_3 | SOURCEANDSINK | 3320.001.01 Brannslokking Sprinkler våt 212
Port_5521409_0 | SOURCEANDSINK | 3320.001.01 Brannslokking Sprinkler våt 212
Port_5521347_2 | SOURCEANDSINK | 3320.001.01 Brannslokking Sprinkler våt 212
Port_5521343_0 | SOURCEANDSINK | 3320.001.01 Brannslokking Sprinkler våt 212
Port_5521345_4 | SOURCEANDSINK | 3320.001.01 Brannslokking Sprinkler våt 212
Port_5521343_1 | SOURCEANDSINK | 3320.001.01 Brannslokking Sprinkler våt 212
Port_5521347_1 | SOURCEANDSINK | 3320.001.01 Brannslokking Sprinkler våt 212
Port_5521345_2 | SOURCEANDSINK | 3320.001.01 Brannslokking Sprinkler våt 212
Port_5521407_1 | SOURCEANDSINK | 3320.001.01 Brannslokking Sprinkler våt 212
Port_5521345_3 | SOURCEANDSINK | 3320.001.01 Brannslokking Sprinkler våt 212
Port_5521375_0 | SOURCEANDSINK | 3320.001.01 Brannslokking Sprinkler våt 212
Port_5521407_2 | SOURCEANDSINK | 3320.001.01 Brannslokking Sprinkler våt 212
Port_5521409_1 | SOURCEANDSINK | 3320.001.01 Brannslokking Sprinkler våt 212
Port_5521413_2 | SOURCEANDSINK | 3320.001.01 Brannslokking Sprinkler våt 212
Port_5521411_0 | SOURCEANDSINK | 3320.001.01 Brannslokking Sprinkler våt 212
Port_5521413_1 | SOURCEANDSINK | 3320.001.01 Brannslokking Sprinkler våt 212
Port_5521411_1 | SOURCEANDSINK | 3320.001.01 Brannslokking Sprinkler våt 212
Port_5521488_2 | SOURCEANDSINK | 3320.001.01 Brannslokking Sprinkler våt 214
Port_5521484_0 | SOURCEANDSINK | 3320.001.01 Brannslokking Sprinkler våt 214
Port_5521586_2 | SOURCEANDSINK | 3320.001.01 Brannslokking Sprinkler våt 214
Port_5521484_1 | SOURCEANDSINK | 3320.001.01 Brannslokking Sprinkler våt 214
Port_5521488_1 | SOURCEANDSINK | 3320.001.01 Brannslokking Sprinkler våt 214
Port_5521499_2 | SOURCEANDSINK | 3320.001.01 Brannslokking Sprinkler våt 214
Port_5521495_0 | SOURCEANDSINK | 3320.001.01 Brannslokking Sprinkler våt 214
Port_5521497_4 | SOURCEANDSINK | 3320.001.01 Brannslokking Sprinkler våt 214
Port_5521495_1 | SOURCEANDSINK | 3320.001.01 Brannslokking Sprinkler våt 214
Port_5521499_1 | SOURCEANDSINK | 3320.001.01 Brannslokking Sprinkler våt 214
Port_5521497_2 | SOURCEANDSINK | 3320.001.01 Brannslokking Sprinkler våt 214
Port_5521497_3 | SOURCEANDSINK | 3320.001.01 Brannslokking Sprinkler våt 214
Port_5521608_1 | SOURCEANDSINK | 3320.001.01 Brannslokking Sprinkler våt 214
Port_5521527_0 | SOURCEANDSINK | 3320.001.01 Brannslokking Sprinkler våt 214
Port_5521608_2 | SOURCEANDSINK | 3320.001.01 Brannslokking Sprinkler våt 214
Port_5521527_1 | SOURCEANDSINK | 3320.001.01 Brannslokking Sprinkler våt 214
Port_5521586_1 | SOURCEANDSINK | 3320.001.01 Brannslokking Sprinkler våt 214
Port_5521705_2 | SOURCEANDSINK | 3320.001.01 Brannslokking Sprinkler våt 215
Port_5521703_0 | SOURCEANDSINK | 3320.001.01 Brannslokking Sprinkler våt 215
Port_5521772_2 | SOURCEANDSINK | 3320.001.01 Brannslokking Sprinkler våt 215
Port_5521703_1 | SOURCEANDSINK | 3320.001.01 Brannslokking Sprinkler våt 215
Port_5521705_1 | SOURCEANDSINK | 3320.001.01 Brannslokking Sprinkler våt 215
Port_5521716_2 | SOURCEANDSINK | 3320.001.01 Brannslokking Sprinkler våt 215
Port_5521712_0 | SOURCEANDSINK | 3320.001.01 Brannslokking Sprinkler våt 215
Port_5521714_4 | SOURCEANDSINK | 3320.001.01 Brannslokking Sprinkler våt 215
Port_5521712_1 | SOURCEANDSINK | 3320.001.01 Brannslokking Sprinkler våt 215
Port_5521716_1 | SOURCEANDSINK | 3320.001.01 Brannslokking Sprinkler våt 215
Port_5521714_2 | SOURCEANDSINK | 3320.001.01 Brannslokking Sprinkler våt 215
Port_5521714_3 | SOURCEANDSINK | 3320.001.01 Brannslokking Sprinkler våt 215
Port_5521774_1 | SOURCEANDSINK | 3320.001.01 Brannslokking Sprinkler våt 215
Port_5521744_0 | SOURCEANDSINK | 3320.001.01 Brannslokking Sprinkler våt 215
Port_5521774_2 | SOURCEANDSINK | 3320.001.01 Brannslokking Sprinkler våt 215
Port_5521744_1 | SOURCEANDSINK | 3320.001.01 Brannslokking Sprinkler våt 215
Port_5521772_1 | SOURCEANDSINK | 3320.001.01 Brannslokking Sprinkler våt 215
Port_5598298_2 | SOURCEANDSINK | 3700.001.05 Kjøle Retur 18° 2
Port_5598128_0 | SOURCEANDSINK | 3700.001.05 Kjøle Retur 18° 2
Port_5598288_1 | SOURCEANDSINK | 3700.001.05 Kjøle Retur 18° 2
Port_5598128_1 | SOURCEANDSINK | 3700.001.05 Kjøle Retur 18° 2
Port_5598251_1 | SOURCEANDSINK | 3700.001.05 Kjøle Retur 18° 2
Port_5598226_0 | SOURCEANDSINK | 3700.001.05 Kjøle Retur 18° 2
Port_5598251_2 | SOURCEANDSINK | 3700.001.05 Kjøle Retur 18° 2
Port_5598226_1 | SOURCEANDSINK | 3700.001.05 Kjøle Retur 18° 2
Port_5598260_2 | SOURCEANDSINK | 3700.001.05 Kjøle Retur 18° 2
Port_5598260_1 | SOURCEANDSINK | 3700.001.05 Kjøle Retur 18° 2
Port_5598286_0 | SOURCEANDSINK | 3700.001.05 Kjøle Retur 18° 2
Port_5598288_2 | SOURCEANDSINK | 3700.001.05 Kjøle Retur 18° 2
Port_5598286_1 | SOURCEANDSINK | 3700.001.05 Kjøle Retur 18° 2
Port_5598298_1 | SOURCEANDSINK | 3700.001.05 Kjøle Retur 18° 2
Port_5598920_2 | SOURCEANDSINK | 3700.001.04 Kjøle Tur 14° 1
Port_5598524_0 | SOURCEANDSINK | 3700.001.04 Kjøle Tur 14° 1
Port_5598813_2 | SOURCEANDSINK | 3700.001.04 Kjøle Tur 14° 1
Port_5598524_1 | SOURCEANDSINK | 3700.001.04 Kjøle Tur 14° 1
Port_5598822_2 | SOURCEANDSINK | 3700.001.04 Kjøle Tur 14° 1
Port_5598665_0 | SOURCEANDSINK | 3700.001.04 Kjøle Tur 14° 1
Port_5598813_1 | SOURCEANDSINK | 3700.001.04 Kjøle Tur 14° 1
Port_5598665_1 | SOURCEANDSINK | 3700.001.04 Kjøle Tur 14° 1
Port_5598699_2 | SOURCEANDSINK | 3700.001.04 Kjøle Tur 14° 1
Port_5598699_1 | SOURCEANDSINK | 3700.001.04 Kjøle Tur 14° 1
Port_5598792_0 | SOURCEANDSINK | 3700.001.04 Kjøle Tur 14° 1
Port_5598920_1 | SOURCEANDSINK | 3700.001.04 Kjøle Tur 14° 1
Port_5598792_1 | SOURCEANDSINK | 3700.001.04 Kjøle Tur 14° 1
Port_5598822_1 | SOURCEANDSINK | 3700.001.04 Kjøle Tur 14° 1
Port_5627301_1 | SOURCEANDSINK | 3200.005.01 Varme Tur 50° 13
Port_5627301_2 | SOURCEANDSINK | 3200.005.01 Varme Tur 50° 13
Port_5627305_1 | SOURCEANDSINK | 3200.005.01 Varme Tur 50° 13
Port_5627303_0 | SOURCEANDSINK | 3200.005.01 Varme Retur 40° 14
Port_5627315_2 | SOURCEANDSINK | 3200.005.01 Varme Retur 40° 14
Port_5627303_1 | SOURCEANDSINK | 3200.005.01 Varme Retur 40° 14
Port_5627305_0 | SOURCEANDSINK | 3200.005.01 Varme Tur 50° 13
Port_5627310_2 | SOURCEANDSINK | 3200.005.01 Varme Tur 50° 13
Port_5627307_1 | SOURCEANDSINK | 3200.005.01 Varme Tur 50° 13
Port_5627308_1 | SOURCEANDSINK | 3200.005.01 Varme Tur 50° 13
Port_5627307_2 | SOURCEANDSINK | 3200.005.01 Varme Tur 50° 13
Port_5627310_1 | SOURCEANDSINK | 3200.005.01 Varme Tur 50° 13
Port_5627308_2 | SOURCEANDSINK | 3200.005.01 Varme Tur 50° 13
Port_5627317_0 | SOURCEANDSINK | 3200.005.01 Varme Tur 50° 13
Port_5627312_0 | SOURCEANDSINK | 3200.005.01 Varme Retur 40° 14
Port_5627362_2 | SOURCEANDSINK | 3200.005.01 Varme Retur 40° 14
Port_5627312_1 | SOURCEANDSINK | 3200.005.01 Varme Retur 40° 14
Port_5627364_1 | SOURCEANDSINK | 3200.005.01 Varme Retur 40° 14
Port_5627314_1 | SOURCEANDSINK | 3200.005.01 Varme Retur 40° 14
Port_5627315_1 | SOURCEANDSINK | 3200.005.01 Varme Retur 40° 14
Port_5627314_2 | SOURCEANDSINK | 3200.005.01 Varme Retur 40° 14
Port_5627364_2 | SOURCEANDSINK | 3200.005.01 Varme Retur 40° 14
Port_5627317_1 | SOURCEANDSINK | 3200.005.01 Varme Tur 50° 13
Port_5627336_1 | SOURCEANDSINK | 3200.005.01 Varme Tur 50° 16
Port_5627338_1 | SOURCEANDSINK | 3200.005.01 Varme Retur 40° 17
Port_5627336_2 | SOURCEANDSINK | 3200.005.01 Varme Tur 50° 16
Port_5627340_1 | SOURCEANDSINK | 3200.005.01 Varme Tur 50° 16
Port_5627338_2 | SOURCEANDSINK | 3200.005.01 Varme Retur 40° 17
Port_5627347_1 | SOURCEANDSINK | 3200.005.01 Varme Retur 40° 17
Port_5627340_0 | SOURCEANDSINK | 3200.005.01 Varme Tur 50° 16
Port_5627345_2 | SOURCEANDSINK | 3200.005.01 Varme Tur 50° 16
Port_5627342_1 | SOURCEANDSINK | 3200.005.01 Varme Tur 50° 16
Port_5627343_1 | SOURCEANDSINK | 3200.005.01 Varme Tur 50° 16
Port_5627342_2 | SOURCEANDSINK | 3200.005.01 Varme Tur 50° 16
Port_5627345_1 | SOURCEANDSINK | 3200.005.01 Varme Tur 50° 16
Port_5627343_2 | SOURCEANDSINK | 3200.005.01 Varme Tur 50° 16
Port_5627352_0 | SOURCEANDSINK | 3200.005.01 Varme Tur 50° 16
Port_5627347_0 | SOURCEANDSINK | 3200.005.01 Varme Retur 40° 17
Port_5627350_2 | SOURCEANDSINK | 3200.005.01 Varme Retur 40° 17
Port_5627349_1 | SOURCEANDSINK | 3200.005.01 Varme Retur 40° 17
Port_5627356_1 | SOURCEANDSINK | 3200.005.01 Varme Retur 40° 17
Port_5627349_2 | SOURCEANDSINK | 3200.005.01 Varme Retur 40° 17
Port_5627350_1 | SOURCEANDSINK | 3200.005.01 Varme Retur 40° 17
Port_5627352_1 | SOURCEANDSINK | 3200.005.01 Varme Tur 50° 16
Port_5627354_0 | SOURCEANDSINK | 3200.005.01 Varme Retur 40° 17
Port_5627356_2 | SOURCEANDSINK | 3200.005.01 Varme Retur 40° 17
Port_5627354_1 | SOURCEANDSINK | 3200.005.01 Varme Retur 40° 17
Port_5627362_1 | SOURCEANDSINK | 3200.005.01 Varme Retur 40° 14
Port_5627781_1 | SOURCEANDSINK | 3200.005.01 Varme Tur 50° 15
Port_5627783_1 | SOURCEANDSINK | 3200.005.01 Varme Retur 40° 16
Port_5627781_2 | SOURCEANDSINK | 3200.005.01 Varme Tur 50° 15
Port_5627785_1 | SOURCEANDSINK | 3200.005.01 Varme Tur 50° 15
Port_5627783_2 | SOURCEANDSINK | 3200.005.01 Varme Retur 40° 16
Port_5627792_1 | SOURCEANDSINK | 3200.005.01 Varme Retur 40° 16
Port_5627785_0 | SOURCEANDSINK | 3200.005.01 Varme Tur 50° 15
Port_5627790_2 | SOURCEANDSINK | 3200.005.01 Varme Tur 50° 15
Port_5627787_1 | SOURCEANDSINK | 3200.005.01 Varme Tur 50° 15
Port_5627788_1 | SOURCEANDSINK | 3200.005.01 Varme Tur 50° 15
Port_5627787_2 | SOURCEANDSINK | 3200.005.01 Varme Tur 50° 15
Port_5627790_1 | SOURCEANDSINK | 3200.005.01 Varme Tur 50° 15
Port_5627788_2 | SOURCEANDSINK | 3200.005.01 Varme Tur 50° 15
Port_5627797_0 | SOURCEANDSINK | 3200.005.01 Varme Tur 50° 15
Port_5627792_0 | SOURCEANDSINK | 3200.005.01 Varme Retur 40° 16
Port_5627795_2 | SOURCEANDSINK | 3200.005.01 Varme Retur 40° 16
Port_5627794_1 | SOURCEANDSINK | 3200.005.01 Varme Retur 40° 16
Port_5627801_1 | SOURCEANDSINK | 3200.005.01 Varme Retur 40° 16
Port_5627794_2 | SOURCEANDSINK | 3200.005.01 Varme Retur 40° 16
Port_5627795_1 | SOURCEANDSINK | 3200.005.01 Varme Retur 40° 16
Port_5627797_1 | SOURCEANDSINK | 3200.005.01 Varme Tur 50° 15
Port_5627799_0 | SOURCEANDSINK | 3200.005.01 Varme Retur 40° 16
Port_5627801_2 | SOURCEANDSINK | 3200.005.01 Varme Retur 40° 16
Port_5627799_1 | SOURCEANDSINK | 3200.005.01 Varme Retur 40° 16
Port_5648003_1 | SOURCEANDSINK | 3200.00x.xx Varme Retur 35° 3
Port_5637678_0 | SOURCEANDSINK | 3200.00x.xx Varme Tur 55° 4
Port_5647961_1 | SOURCEANDSINK | 3200.00x.xx Varme Tur 55° 4
Port_5642011_0 | SOURCEANDSINK | 3103.001.01 KV Forbruksvann 3
Port_5642038_1 | SOURCEANDSINK | 3103.001.01 KV Forbruksvann 3
Port_5642011_1 | SOURCEANDSINK | 3103.001.01 KV Forbruksvann 3
Port_5642097_1 | SOURCEANDSINK | 3103.001.01 KV Forbruksvann 3
Port_5642038_2 | SOURCEANDSINK | 3103.001.01 KV Forbruksvann 3
Port_5642097_2 | SOURCEANDSINK | 3103.001.01 KV Forbruksvann 3
Port_5647725_0 | SOURCEANDSINK | 3200.00x.xx Varme Retur 35° 3
Port_5648009_2 | SOURCEANDSINK | 3200.00x.xx Varme Retur 35° 3
Port_5647725_1 | SOURCEANDSINK | 3200.00x.xx Varme Retur 35° 3
Port_5647767_0 | SOURCEANDSINK | 3200.00x.xx Varme Tur 55° 4
Port_5647967_2 | SOURCEANDSINK | 3200.00x.xx Varme Tur 55° 4
Port_5647767_1 | SOURCEANDSINK | 3200.00x.xx Varme Tur 55° 4
Port_5647959_0 | SOURCEANDSINK | 3200.00x.xx Varme Tur 55° 1
Port_5647961_2 | SOURCEANDSINK | 3200.00x.xx Varme Tur 55° 1
Port_5647959_1 | SOURCEANDSINK | 3200.00x.xx Varme Tur 55° 4
Port_5647967_1 | SOURCEANDSINK | 3200.00x.xx Varme Tur 55° 4
Port_5648001_0 | SOURCEANDSINK | 3200.00x.xx Varme Retur 35° 1
Port_5648003_2 | SOURCEANDSINK | 3200.00x.xx Varme Retur 35° 1
Port_5648001_1 | SOURCEANDSINK | 3200.00x.xx Varme Retur 35° 3
Port_5648009_1 | SOURCEANDSINK | 3200.00x.xx Varme Retur 35° 3

# IfcDoor: NSW Innvendig slagdør, enkel:9M x 21M (3)
In: H02-Nivå F-3,5 m
Type - ParameterTakesPrecedence: no; Sizeable: no; Material: <Unnamed>, _NSW Dør - dørblad, hvit, _NSW Dør - terskel, tre, _NSW Dør - listverk, hvit
OverallHeight: 2100 mm; OverallWidth: 910 mm
ePset_Simplebim - Assembly Level: Leaf
ePset_LocationTool - Splitting: ORIGINAL
Pset_DoorCommon - Reference: NSW Innvendig slagdør, enkel:9M x 21M
ePset_SimplebimBasicQuantities - Area (Simplebim): 2.05826 m2; Area, opening (Simplebim): 1.911 m2; Width, opening (Simplebim): 910 mm; Width (Simplebim): 967 mm; Height (Simplebim): 2128.5 mm; Height, opening (Simplebim): 2100 mm; Length, frame (Simplebim): 5224 mm
Name (NSW Innvendig slagdør, enkel:9M x 21M:...) | 05_ID-nummer
11871154 | +BR001=244.02096
11871209 | +BR001=244.02098
11871268 | +BR001=244.02094

# IfcDoor: NSW Innvendig slagdør, par:15M x 21M, NSW Innvendig slagdør, par:15M x 21M:12073371
In: H02-Nivå F-3,5 m
Type - OperationType: DOUBLE_DOOR_SINGLE_SWING; ParameterTakesPrecedence: no; Sizeable: no; Material: <Unnamed>, _NSW Dør - dørblad, hvit, _NSW Dør - terskel, tre, _NSW Dør - listverk, hvit
Type - IfcDoorPanelProperties - PanelOperation: SWINGING
OverallHeight: 2100 mm; OverallWidth: 1510 mm
Pset_DoorCommon - Reference: NSW Innvendig slagdør, par:15M x 21M
ePset_Simplebim - Assembly Level: Leaf
ePset_SimplebimBasicQuantities - Area (Simplebim): 3.33536 m2; Width, opening (Simplebim): 1510 mm; Width (Simplebim): 1567 mm; Height (Simplebim): 2128.5 mm; Height, opening (Simplebim): 2100 mm; Length, frame (Simplebim): 5824 mm; Area, opening (Simplebim): 3.171 m2
ePset_LocationTool - Splitting: ORIGINAL

# IfcDoor: Sgl Glass (1):IDG 11x21 M, Sgl Glass (1):IDG 11x21 M:12568215
In: H02-Nivå F-3,5 m
Type - ParameterTakesPrecedence: no; Sizeable: no; Material: Metal - Aluminum, Glass
OverallHeight: 2480 mm; OverallWidth: 1060 mm
ePset_SimplebimBasicQuantities - Area (Simplebim): 2.6288 m2; Width (Simplebim): 1060 mm; Height (Simplebim): 2480 mm; Length, frame (Simplebim): 6020 mm
ePset_Simplebim - Assembly Level: Leaf
ePset_LocationTool - Splitting: ORIGINAL
Pset_DoorCommon - Reference: Sgl Glass (1):IDG 11x21 M

# IfcFlowController: BALL-VALVE-THREAD:ball-valve-thead-DN15 (6)
In: H01-Nivå D+0,36
Type - Material: 3200.005 Tur
ePset_LocationTool - Splitting: ORIGINAL
ePset_Simplebim - Assembly Level: Leaf
Name (BALL-VALVE-THREAD:ball-valve-thead-DN15:...) | Group
5627307 | 3200.005.01 Varme Tur 50° 13
5627314 | 3200.005.01 Varme Retur 40° 14
5627342 | 3200.005.01 Varme Tur 50° 16
5627349 | 3200.005.01 Varme Retur 40° 17
5627787 | 3200.005.01 Varme Tur 50° 15
5627794 | 3200.005.01 Varme Retur 40° 16

# IfcFlowFitting: Bend sveist:EN 10253-1 S235 3D ISO (2)
In: H01-Nivå D+0,36
Type - Material: 3320.001
ePset_LocationTool - Splitting: ORIGINAL
ePset_Simplebim - Assembly Level: Leaf
Group: 3320.001.01 Brannslokking Sprinkler våt 2
Name (Bend sveist:EN 10253-1 S235 3D ISO:...)
5517237
5517251

# IfcFlowFitting: Bend sveist:EN 10253-1 S235 3D ISO (8)
In: H01-Nivå D+0,36
Type - Material: 3700.001 Retur
ePset_LocationTool - Splitting: ORIGINAL
ePset_Simplebim - Assembly Level: Leaf
Name (Bend sveist:EN 10253-1 S235 3D ISO:...) | Group
5598251 | 3700.001.05 Kjøle Retur 18° 2
5598260 | 3700.001.05 Kjøle Retur 18° 2
5598288 | 3700.001.05 Kjøle Retur 18° 2
5598298 | 3700.001.05 Kjøle Retur 18° 2
5598699 | 3700.001.04 Kjøle Tur 14° 1
5598813 | 3700.001.04 Kjøle Tur 14° 1
5598822 | 3700.001.04 Kjøle Tur 14° 1
5598920 | 3700.001.04 Kjøle Tur 14° 1

# IfcFlowFitting: Lindab ESU:ESU (5)
In: H01-Nivå D+0,36
Type - Material: DF_Material1
ePset_Simplebim - Assembly Level: Leaf
ePset_LocationTool - Splitting: ORIGINAL
Name (Lindab ESU:ESU:...) | Group
5490954 | 36.03 Avtrekk 1.etg nord og øst + nordfløy: 1
5490987 | 36.03 Avtrekk 1.etg nord og øst + nordfløy: 1
5846151 | 36.02 Tilluft 1.etg syd og vest: 9
5847465 | 360.041 Tilluft Nytt system Nord: 4
5847477 | 360.041 Avtrekk Nytt system Nord: 6

# IfcFlowFitting: Lindab NPU:NPU (2)
In: H01-Nivå D+0,36
Type - Material: DF_Material1
ePset_LocationTool - Splitting: ORIGINAL
ePset_Simplebim - Assembly Level: Leaf
Name (Lindab NPU:NPU:...) | Group
5596789 | 36.03 Tilluft 1.etg nord og øst + nordfløy: 1
5596818 | 36.03 Avtrekk 1.etg nord og øst + nordfløy: 1

# IfcFlowFitting: Lindab TCPU:TCPU (6)
In: H01-Nivå D+0,36
Type - Material: DF_Material1
ePset_LocationTool - Splitting: ORIGINAL
ePset_Simplebim - Assembly Level: Leaf
Name (Lindab TCPU:TCPU:...) | Group
5490944 | 36.03 Avtrekk 1.etg nord og øst + nordfløy: 1
5490948 | 36.03 Avtrekk 1.etg nord og øst + nordfløy: 1
5490977 | 36.03 Avtrekk 1.etg nord og øst + nordfløy: 1
5490981 | 36.03 Avtrekk 1.etg nord og øst + nordfløy: 1
5510923 | 36.26 Tilluft Bagasjehall 1.etg: 1
5513688 | 36.26 Tilluft Bagasjehall 1.etg: 1

# IfcFlowFitting: PRO_103183:DN10-100 / d12-108 - OD (12)
In: H01-Nivå D+0,36
Type - Description: Geberit Mapress El-Forsinket Stål reduksjon med spissende; PredefinedType: TRANSITION; Material: Geberit_Plastic_Red, Geberit_Mapress_C-Steel
ePset_LocationTool - Splitting: ORIGINAL
ePset_Simplebim - Assembly Level: Leaf
Name (PRO_103183:DN10-100 / d12-108 - OD:...) | Group
5627308 | 3200.005.01 Varme Tur 50° 13
5627310 | 3200.005.01 Varme Tur 50° 13
5627315 | 3200.005.01 Varme Retur 40° 14
5627343 | 3200.005.01 Varme Tur 50° 16
5627345 | 3200.005.01 Varme Tur 50° 16
5627350 | 3200.005.01 Varme Retur 40° 17
5627356 | 3200.005.01 Varme Retur 40° 17
5627364 | 3200.005.01 Varme Retur 40° 14
5627788 | 3200.005.01 Varme Tur 50° 15
5627790 | 3200.005.01 Varme Tur 50° 15
5627795 | 3200.005.01 Varme Retur 40° 16
5627801 | 3200.005.01 Varme Retur 40° 16

# IfcFlowFitting: PRO_103184:DN10-100 / d12-108 - OD (10)
In: H01-Nivå D+0,36
Type - Description: Geberit Mapress El-Forsinket Stål bend; PredefinedType: BEND; Material: Geberit_Plastic_Red, Geberit_Mapress_C-Steel
ePset_Simplebim - Assembly Level: Leaf
ePset_LocationTool - Splitting: ORIGINAL
Name (PRO_103184:DN10-100 / d12-108 - OD:...) | Group
5627301 | 3200.005.01 Varme Tur 50° 13
5627336 | 3200.005.01 Varme Tur 50° 16
5627338 | 3200.005.01 Varme Retur 40° 17
5627362 | 3200.005.01 Varme Retur 40° 14
5627781 | 3200.005.01 Varme Tur 50° 15
5627783 | 3200.005.01 Varme Retur 40° 16
5647961 | 3200.00x.xx Varme Tur 55° 4; 3200.00x.xx Varme Tur 55° 1
5647967 | 3200.00x.xx Varme Tur 55° 4
5648003 | 3200.00x.xx Varme Retur 35° 3; 3200.00x.xx Varme Retur 35° 1
5648009 | 3200.00x.xx Varme Retur 35° 3

# IfcFlowFitting: RS_53_PF_UN_Bend-Mapress-Cu-In_gen_MC:Mapress Bend (2)
In: H01-Nivå D+0,36
Type - Material: 3103.001 KV
ePset_LocationTool - Splitting: ORIGINAL
ePset_Simplebim - Assembly Level: Leaf
Group: 3103.001.01 KV Forbruksvann 3
Name (RS_53_PF_UN_Bend-Mapress-Cu-In_gen_MC:Mapress Bend:...)
5642038
5642097

# IfcFlowFitting: RS_53_PIF_UN_Cross-EN10241_MC_gen:RS_53_PIF_UN_Cross-EN10241_MC_gen (8)
In: H01-Nivå D+0,36
Type - Material: 3320.001
ePset_LocationTool - Splitting: ORIGINAL
ePset_Simplebim - Assembly Level: Leaf
Name (RS_53_PIF_UN_Cross-EN10241_MC_gen:RS_53_PIF_UN_Cross-EN10241_MC_gen:...) | Group
5514224 | 3320.001.01 Brannslokking Sprinkler våt 182
5514250 | 3320.001.01 Brannslokking Sprinkler våt 182
5514776 | 3320.001.01 Brannslokking Sprinkler våt 183
5514802 | 3320.001.01 Brannslokking Sprinkler våt 183
5514919 | 3320.001.01 Brannslokking Sprinkler våt 184
5514945 | 3320.001.01 Brannslokking Sprinkler våt 184
5515060 | 3320.001.01 Brannslokking Sprinkler våt 185
5515086 | 3320.001.01 Brannslokking Sprinkler våt 185

# IfcFlowFitting: RS_53_PIF_UN_Elbow-EN10241_NOR:RS_53_PIF_UN_Elbow-EN10241_NOR (24)
In: H01-Nivå D+0,36
Type - Material: 3320.001
ePset_LocationTool - Splitting: ORIGINAL
ePset_Simplebim - Assembly Level: Leaf
Name (RS_53_PIF_UN_Elbow-EN10241_NOR:RS_53_PIF_UN_Elbow-EN10241_NOR:...) | Group
5514309 | 3320.001.01 Brannslokking Sprinkler våt 191
5514589 | 3320.001.01 Brannslokking Sprinkler våt 182
5514670 | 3320.001.01 Brannslokking Sprinkler våt 182
5514849 | 3320.001.01 Brannslokking Sprinkler våt 193
5514851 | 3320.001.01 Brannslokking Sprinkler våt 183
5514853 | 3320.001.01 Brannslokking Sprinkler våt 183
5514992 | 3320.001.01 Brannslokking Sprinkler våt 195
5514994 | 3320.001.01 Brannslokking Sprinkler våt 184
5514996 | 3320.001.01 Brannslokking Sprinkler våt 184
5515133 | 3320.001.01 Brannslokking Sprinkler våt 197
5515135 | 3320.001.01 Brannslokking Sprinkler våt 185
5515137 | 3320.001.01 Brannslokking Sprinkler våt 185
5520873 | 3320.001.01 Brannslokking Sprinkler våt 210
5520886 | 3320.001.01 Brannslokking Sprinkler våt 210
5521252 | 3320.001.01 Brannslokking Sprinkler våt 210
5521336 | 3320.001.01 Brannslokking Sprinkler våt 212
5521347 | 3320.001.01 Brannslokking Sprinkler våt 212
5521413 | 3320.001.01 Brannslokking Sprinkler våt 212
5521488 | 3320.001.01 Brannslokking Sprinkler våt 214
5521499 | 3320.001.01 Brannslokking Sprinkler våt 214
5521586 | 3320.001.01 Brannslokking Sprinkler våt 214
5521705 | 3320.001.01 Brannslokking Sprinkler våt 215
5521716 | 3320.001.01 Brannslokking Sprinkler våt 215
5521772 | 3320.001.01 Brannslokking Sprinkler våt 215

# IfcFlowFitting: RS_53_PIF_UN_Reducing-Socket-EN10241_MC_gen:RS_53_PIF_UN_Reducing-Socket-EN10241_MC_gen (44)
In: H01-Nivå D+0,36
Type - Material: 3320.001
ePset_LocationTool - Splitting: ORIGINAL
ePset_Simplebim - Assembly Level: Leaf
Name (RS_53_PIF_UN_Reducing-Socket-EN10241_MC_gen:RS_53_PIF_UN_Reducing-Socket-EN10241_MC_gen:...) | Group
5514183 | 3320.001.01 Brannslokking Sprinkler våt 182
5514200 | 3320.001.01 Brannslokking Sprinkler våt 182
5514202 | 3320.001.01 Brannslokking Sprinkler våt 182
5514207 | 3320.001.01 Brannslokking Sprinkler våt 182
5514226 | 3320.001.01 Brannslokking Sprinkler våt 182
5514228 | 3320.001.01 Brannslokking Sprinkler våt 182
5514235 | 3320.001.01 Brannslokking Sprinkler våt 182
5514252 | 3320.001.01 Brannslokking Sprinkler våt 182
5514254 | 3320.001.01 Brannslokking Sprinkler våt 182
5514273 | 3320.001.01 Brannslokking Sprinkler våt 182
5514735 | 3320.001.01 Brannslokking Sprinkler våt 183
5514752 | 3320.001.01 Brannslokking Sprinkler våt 183
5514754 | 3320.001.01 Brannslokking Sprinkler våt 183
5514759 | 3320.001.01 Brannslokking Sprinkler våt 183
5514778 | 3320.001.01 Brannslokking Sprinkler våt 183
5514780 | 3320.001.01 Brannslokking Sprinkler våt 183
5514787 | 3320.001.01 Brannslokking Sprinkler våt 183
5514804 | 3320.001.01 Brannslokking Sprinkler våt 183
5514806 | 3320.001.01 Brannslokking Sprinkler våt 183
5514819 | 3320.001.01 Brannslokking Sprinkler våt 183
5514878 | 3320.001.01 Brannslokking Sprinkler våt 184
5514895 | 3320.001.01 Brannslokking Sprinkler våt 184
5514897 | 3320.001.01 Brannslokking Sprinkler våt 184
5514902 | 3320.001.01 Brannslokking Sprinkler våt 184
5514921 | 3320.001.01 Brannslokking Sprinkler våt 184
5514923 | 3320.001.01 Brannslokking Sprinkler våt 184
5514930 | 3320.001.01 Brannslokking Sprinkler våt 184
5514947 | 3320.001.01 Brannslokking Sprinkler våt 184
5514949 | 3320.001.01 Brannslokking Sprinkler våt 184
5514962 | 3320.001.01 Brannslokking Sprinkler våt 184
5515019 | 3320.001.01 Brannslokking Sprinkler våt 185
5515036 | 3320.001.01 Brannslokking Sprinkler våt 185
5515038 | 3320.001.01 Brannslokking Sprinkler våt 185
5515043 | 3320.001.01 Brannslokking Sprinkler våt 185
5515062 | 3320.001.01 Brannslokking Sprinkler våt 185
5515064 | 3320.001.01 Brannslokking Sprinkler våt 185
5515071 | 3320.001.01 Brannslokking Sprinkler våt 185
5515088 | 3320.001.01 Brannslokking Sprinkler våt 185
5515090 | 3320.001.01 Brannslokking Sprinkler våt 185
5515103 | 3320.001.01 Brannslokking Sprinkler våt 185
5521225 | 3320.001.01 Brannslokking Sprinkler våt 210
5521407 | 3320.001.01 Brannslokking Sprinkler våt 212
5521608 | 3320.001.01 Brannslokking Sprinkler våt 214
5521774 | 3320.001.01 Brannslokking Sprinkler våt 215

# IfcFlowFitting: RS_53_PIF_UN_Tee-Reduced-EN10241_MC_gen:RS_53_PIF_UN_Tee-Reduced-EN10241_MC_gen (18)
In: H01-Nivå D+0,36
Type - Material: 3320.001
ePset_LocationTool - Splitting: ORIGINAL
ePset_Simplebim - Assembly Level: Leaf
Name (RS_53_PIF_UN_Tee-Reduced-EN10241_MC_gen:RS_53_PIF_UN_Tee-Reduced-EN10241_MC_gen:...) | Group
5514198 | 3320.001.01 Brannslokking Sprinkler våt 182
5514265 | 3320.001.01 Brannslokking Sprinkler våt 182
5514284 | 3320.001.01 Brannslokking Sprinkler våt 182
5514750 | 3320.001.01 Brannslokking Sprinkler våt 183
5514815 | 3320.001.01 Brannslokking Sprinkler våt 183
5514828 | 3320.001.01 Brannslokking Sprinkler våt 183
5514893 | 3320.001.01 Brannslokking Sprinkler våt 184
5514958 | 3320.001.01 Brannslokking Sprinkler våt 184
5514971 | 3320.001.01 Brannslokking Sprinkler våt 184
5515034 | 3320.001.01 Brannslokking Sprinkler våt 185
5515099 | 3320.001.01 Brannslokking Sprinkler våt 185
5515112 | 3320.001.01 Brannslokking Sprinkler våt 185
5520871 | 3320.001.01 Brannslokking Sprinkler våt 210
5520884 | 3320.001.01 Brannslokking Sprinkler våt 210
5521334 | 3320.001.01 Brannslokking Sprinkler våt 212
5521345 | 3320.001.01 Brannslokking Sprinkler våt 212
5521497 | 3320.001.01 Brannslokking Sprinkler våt 214
5521714 | 3320.001.01 Brannslokking Sprinkler våt 215

# IfcFlowFitting: Sveis:Sveis (20)
In: H01-Nivå D+0,36
Type - Material: <Unnamed>
ePset_Simplebim - Assembly Level: Leaf
ePset_LocationTool - Splitting: ORIGINAL
Name (Sveis:Sveis:...)
5517239
5517241
5517253
5517255
5598253
5598255
5598262
5598264
5598290
5598292
5598300
5598302
5598701
5598703
5598815
5598817
5598824
5598826
5598922
5598924

# IfcFlowFitting: magicirc_elbow_full_radius_NOR:magicirc_elbow_full_radius_NOR (10)
In: H01-Nivå D+0,36
Type - Material: 3601.001 Avtrekk
ePset_LocationTool - Splitting: ORIGINAL
ePset_Simplebim - Assembly Level: Leaf
Name (magicirc_elbow_full_radius_NOR:magicirc_elbow_full_radius_NOR:...) | Group
5553133 | 36.03 Avtrekk 1.etg nord og øst + nordfløy: 1
5553194 | 36.03 Avtrekk 1.etg nord og øst + nordfløy: 1
5553866 | 36.01 Tilluft Passasjerhall og kjeller: 2
5553873 | 36.01 Tilluft Passasjerhall og kjeller: 2
5553880 | 36.01 Tilluft Passasjerhall og kjeller: 2
5553887 | 36.01 Tilluft Passasjerhall og kjeller: 2
5553894 | 36.01 Tilluft Passasjerhall og kjeller: 2
5553901 | 36.01 Tilluft Passasjerhall og kjeller: 2
5553908 | 36.01 Tilluft Passasjerhall og kjeller: 2
5553915 | 36.01 Tilluft Passasjerhall og kjeller: 2

# IfcFlowFitting: magicirc_elbow_full_radius_NOR:magicirc_elbow_full_radius_NOR (16)
In: H01-Nivå D+0,36
Type - Material: 3601.001 Tilluft
ePset_Simplebim - Assembly Level: Leaf
ePset_LocationTool - Splitting: ORIGINAL
Name (magicirc_elbow_full_radius_NOR:magicirc_elbow_full_radius_NOR:...) | Group
5510927 | 36.26 Tilluft Bagasjehall 1.etg: 1
5510937 | 36.26 Tilluft Bagasjehall 1.etg: 1
5510941 | 36.26 Tilluft Bagasjehall 1.etg: 1
5510945 | 36.26 Tilluft Bagasjehall 1.etg: 1
5511043 | 36.26 Tilluft Bagasjehall 1.etg: 1
5511047 | 36.26 Tilluft Bagasjehall 1.etg: 1
5511051 | 36.26 Tilluft Bagasjehall 1.etg: 1
5512118 | 36.26 Tilluft Bagasjehall 1.etg: 1
5512122 | 36.26 Tilluft Bagasjehall 1.etg: 1
5513827 | 36.26 Tilluft Bagasjehall 1.etg: 1
5559984 | 36.03 Tilluft 1.etg nord og øst + nordfløy: 1
5846025 | 36.02 Avtrekk 1.etg syd og vest: 5
5846159 | 36.02 Tilluft 1.etg syd og vest: 9
5846451 | 36.02 Tilluft 1.etg syd og vest: 9
5847794 | 360.041 Tilluft Nytt system Nord: 3
5848617 | 360.041 Tilluft Nytt system Nord: 3

# IfcFlowFitting: magicirc_reduction_NOR:magicirc_reduction_NOR (3)
In: H01-Nivå D+0,36
Type - Material: Material_Duct
ePset_LocationTool - Splitting: ORIGINAL
ePset_Simplebim - Assembly Level: Leaf
Name (magicirc_reduction_NOR:magicirc_reduction_NOR:...) | Group
5510931 | 36.26 Tilluft Bagasjehall 1.etg: 1
5513817 | 36.26 Tilluft Bagasjehall 1.etg: 1
5848615 | 360.041 Tilluft Nytt system Nord: 3

# IfcFlowFitting: magicirc_tapoutlet_001:magicirc_tapoutlet_001 (3)
In: H01-Nivå D+0,36
Type - Material: 3601.001 Avtrekk
ePset_Simplebim - Assembly Level: Leaf
ePset_LocationTool - Splitting: ORIGINAL
Name (magicirc_tapoutlet_001:magicirc_tapoutlet_001:...) | Group
5596834 | 36.03 Avtrekk 1.etg nord og øst + nordfløy: 1
5596836 | 36.03 Avtrekk 1.etg nord og øst + nordfløy: 1
5846023 | 360.041 Avtrekk Nytt system Nord: 6; 36.02 Avtrekk 1.etg syd og vest: 5

# IfcFlowFitting: magicirc_tapoutlet_001:magicirc_tapoutlet_001 (13)
In: H01-Nivå D+0,36
Type - Material: 3601.001 Tilluft
ePset_LocationTool - Splitting: ORIGINAL
ePset_Simplebim - Assembly Level: Leaf
Name (magicirc_tapoutlet_001:magicirc_tapoutlet_001:...) | Group
5553958 | 36.01 Tilluft Passasjerhall og kjeller: 2
5553961 | 36.01 Tilluft Passasjerhall og kjeller: 2
5553964 | 36.01 Tilluft Passasjerhall og kjeller: 2
5553967 | 36.01 Tilluft Passasjerhall og kjeller: 2
5553970 | 36.01 Tilluft Passasjerhall og kjeller: 2
5553973 | 36.01 Tilluft Passasjerhall og kjeller: 2
5553976 | 36.01 Tilluft Passasjerhall og kjeller: 2
5553979 | 36.01 Tilluft Passasjerhall og kjeller: 2
5560016 | 36.03 Tilluft 1.etg nord og øst + nordfløy: 1
5846368 | 36.02 Tilluft 1.etg syd og vest: 9
5846400 | 36.02 Tilluft 1.etg syd og vest: 9
5846449 | 36.02 Tilluft 1.etg syd og vest: 9
5848537 | 360.041 Tilluft Nytt system Nord: 3; 36.02 Tilluft 1.etg syd og vest: 16

# IfcFlowSegment: Cable Tray with Fittings:Kabelstige (5)
In: H01-Nivå D+0,36
Type - PredefinedType: CABLETRAYSEGMENT; Material: Kabelstige
ePset_LocationTool - Splitting: RESULT
ePset_Simplebim - Assembly Level: Leaf
ePset_SimplebimBasicQuantities - Height (Simplebim): 25 mm
Name (Cable Tray with Fittings:Kabelstige:...) | Width (Simplebim) (mm) | Length (Simplebim) (mm)
2734880 | 400 | 12527
2735034 | 600 | 12527
2735200 | 600 | 12527
2797427 | 600 | 7949
2855874 | 600 | 7880

# IfcFlowSegment: Pipe Types:Kobberrør (3)
In: H01-Nivå D+0,36
Type - Material: 3103.001 KV
ePset_Simplebim - Assembly Level: Leaf
ePset_SimplebimBasicQuantities - Width (Simplebim): 28 mm; Height (Simplebim): 28 mm
Group: 3103.001.01 KV Forbruksvann 3
Name (Pipe Types:Kobberrør:...) | Splitting | Length (Simplebim) (mm)
5642011 | ORIGINAL | 11332
5642035 | RESULT | 526
5642094 | RESULT | 526

# IfcFlowSegment: Pipe Types:Pressfittingssystem MM (20)
In: H01-Nivå D+0,36
Type - Material: 3200.005 Tur
ePset_Simplebim - Assembly Level: Leaf
Name (Pipe Types:Pressfittingssystem MM:...) | Length (Simplebim) (mm) | Width (Simplebim) (mm) | Height (Simplebim) (mm) | Splitting | Group
5627303 | 437.578 | 18 | 18 | ORIGINAL | 3200.005.01 Varme Retur 40° 14
5627305 | 446.63 | 18 | 18 | ORIGINAL | 3200.005.01 Varme Tur 50° 13
5627312 | 447.921 | 18.206 | 18 | ORIGINAL | 3200.005.01 Varme Retur 40° 14
5627317 | 478.861 | 18 | 18 | ORIGINAL | 3200.005.01 Varme Tur 50° 13
5627340 | 447.913 | 18 | 18 | ORIGINAL | 3200.005.01 Varme Tur 50° 16
5627347 | 447.913 | 18 | 18 | ORIGINAL | 3200.005.01 Varme Retur 40° 17
5627352 | 478.861 | 18 | 18 | ORIGINAL | 3200.005.01 Varme Tur 50° 16
5627354 | 355.003 | 18 | 18.05 | ORIGINAL | 3200.005.01 Varme Retur 40° 17
5627785 | 447.913 | 18 | 18 | ORIGINAL | 3200.005.01 Varme Tur 50° 15
5627792 | 447.913 | 18 | 18 | ORIGINAL | 3200.005.01 Varme Retur 40° 16
5627797 | 478.861 | 18 | 18 | ORIGINAL | 3200.005.01 Varme Tur 50° 15
5627799 | 355.003 | 18 | 18.05 | ORIGINAL | 3200.005.01 Varme Retur 40° 16
5637678 | 1563.5 | 54 | 54 | ORIGINAL | 3200.00x.xx Varme Tur 55° 4
5647725 | 381.468 | 54 | 54 | ORIGINAL | 3200.00x.xx Varme Retur 35° 3
5647767 | 380 | 54 | 54 | ORIGINAL | 3200.00x.xx Varme Tur 55° 4
5647959 | 170 | 54 | 54 | ORIGINAL | 3200.00x.xx Varme Tur 55° 4; 3200.00x.xx Varme Tur 55° 1
5648001 | 170 | 54 | 54 | ORIGINAL | 3200.00x.xx Varme Retur 35° 3; 3200.00x.xx Varme Retur 35° 1
5647644 | 10492 | 54 | 54 | RESULT | 3200.00x.xx Varme Retur 35° 1
5647674 | 10502 | 54 | 54 | RESULT | 3200.00x.xx Varme Tur 55° 1
5636228 | 1321 | 54 | 54 | RESULT | 3200.00x.xx Varme Retur 35° 3

# IfcFlowSegment: Pipe Types:Stålrør sveist og gjenget (78)
In: H01-Nivå D+0,36
Type - Material: 3320.001
ePset_Simplebim - Assembly Level: Leaf
Name (Pipe Types:Stålrør sveist og gjenget:...) | Width (Simplebim) (mm) | Height (Simplebim) (mm) | Length (Simplebim) (mm) | Splitting | Group
5514181 | 33.7 | 33.7 | 306.733 | ORIGINAL | 3320.001.01 Brannslokking Sprinkler våt 182
5514205 | 33.7 | 33.7 | 306.733 | ORIGINAL | 3320.001.01 Brannslokking Sprinkler våt 182
5514222 | 42.4 | 42.4 | 2940.8 | ORIGINAL | 3320.001.01 Brannslokking Sprinkler våt 182
5514230 | 42.4 | 42.4 | 2940.8 | ORIGINAL | 3320.001.01 Brannslokking Sprinkler våt 182
5514233 | 33.7 | 33.7 | 306.733 | ORIGINAL | 3320.001.01 Brannslokking Sprinkler våt 182
5514261 | 33.7 | 33.7 | 298.846 | ORIGINAL | 3320.001.01 Brannslokking Sprinkler våt 182
5514266 | 42.4 | 42.4 | 2568.47 | ORIGINAL | 3320.001.01 Brannslokking Sprinkler våt 182
5514280 | 33.7 | 33.7 | 298.846 | ORIGINAL | 3320.001.01 Brannslokking Sprinkler våt 182
5514290 | 48.3 | 48.3 | 2846.8 | ORIGINAL | 3320.001.01 Brannslokking Sprinkler våt 182
5514292 | 48.3 | 48.3 | 1537.36 | ORIGINAL | 3320.001.01 Brannslokking Sprinkler våt 182
5514307 | 33.7 | 33.7 | 476.1 | ORIGINAL | 3320.001.01 Brannslokking Sprinkler våt 191
5514733 | 33.7 | 33.7 | 306.733 | ORIGINAL | 3320.001.01 Brannslokking Sprinkler våt 183
5514757 | 33.7 | 33.7 | 306.733 | ORIGINAL | 3320.001.01 Brannslokking Sprinkler våt 183
5514774 | 42.4 | 42.4 | 2940.8 | ORIGINAL | 3320.001.01 Brannslokking Sprinkler våt 183
5514782 | 42.4 | 42.4 | 2940.8 | ORIGINAL | 3320.001.01 Brannslokking Sprinkler våt 183
5514785 | 33.7 | 33.7 | 306.733 | ORIGINAL | 3320.001.01 Brannslokking Sprinkler våt 183
5514813 | 33.7 | 33.7 | 298.846 | ORIGINAL | 3320.001.01 Brannslokking Sprinkler våt 183
5514816 | 42.4 | 42.4 | 2568.47 | ORIGINAL | 3320.001.01 Brannslokking Sprinkler våt 183
5514826 | 33.7 | 33.7 | 298.846 | ORIGINAL | 3320.001.01 Brannslokking Sprinkler våt 183
5514830 | 48.3 | 48.3 | 2846.8 | ORIGINAL | 3320.001.01 Brannslokking Sprinkler våt 183
5514832 | 48.3 | 48.3 | 1537.36 | ORIGINAL | 3320.001.01 Brannslokking Sprinkler våt 183
5514847 | 33.7 | 33.7 | 476.1 | ORIGINAL | 3320.001.01 Brannslokking Sprinkler våt 193
5514876 | 33.7 | 33.7 | 306.733 | ORIGINAL | 3320.001.01 Brannslokking Sprinkler våt 184
5514900 | 33.7 | 33.7 | 306.733 | ORIGINAL | 3320.001.01 Brannslokking Sprinkler våt 184
5514917 | 42.4 | 42.4 | 2940.8 | ORIGINAL | 3320.001.01 Brannslokking Sprinkler våt 184
5514925 | 42.4 | 42.4 | 2940.8 | ORIGINAL | 3320.001.01 Brannslokking Sprinkler våt 184
5514928 | 33.7 | 33.7 | 306.733 | ORIGINAL | 3320.001.01 Brannslokking Sprinkler våt 184
5514956 | 33.7 | 33.7 | 298.846 | ORIGINAL | 3320.001.01 Brannslokking Sprinkler våt 184
5514959 | 42.4 | 42.4 | 2568.47 | ORIGINAL | 3320.001.01 Brannslokking Sprinkler våt 184
5514969 | 33.7 | 33.7 | 298.846 | ORIGINAL | 3320.001.01 Brannslokking Sprinkler våt 184
5514973 | 48.3 | 48.3 | 2846.8 | ORIGINAL | 3320.001.01 Brannslokking Sprinkler våt 184
5514975 | 48.3 | 48.3 | 1537.36 | ORIGINAL | 3320.001.01 Brannslokking Sprinkler våt 184
5514990 | 33.7 | 33.7 | 476.1 | ORIGINAL | 3320.001.01 Brannslokking Sprinkler våt 195
5515017 | 33.7 | 33.7 | 306.733 | ORIGINAL | 3320.001.01 Brannslokking Sprinkler våt 185
5515041 | 33.7 | 33.7 | 306.733 | ORIGINAL | 3320.001.01 Brannslokking Sprinkler våt 185
5515058 | 42.4 | 42.4 | 2940.8 | ORIGINAL | 3320.001.01 Brannslokking Sprinkler våt 185
5515066 | 42.4 | 42.4 | 2940.8 | ORIGINAL | 3320.001.01 Brannslokking Sprinkler våt 185
5515069 | 33.7 | 33.7 | 306.733 | ORIGINAL | 3320.001.01 Brannslokking Sprinkler våt 185
5515097 | 33.7 | 33.7 | 298.846 | ORIGINAL | 3320.001.01 Brannslokking Sprinkler våt 185
5515100 | 42.4 | 42.4 | 2568.47 | ORIGINAL | 3320.001.01 Brannslokking Sprinkler våt 185
5515110 | 33.7 | 33.7 | 298.846 | ORIGINAL | 3320.001.01 Brannslokking Sprinkler våt 185
5515114 | 48.3 | 48.3 | 2846.8 | ORIGINAL | 3320.001.01 Brannslokking Sprinkler våt 185
5515116 | 48.3 | 48.3 | 1537.36 | ORIGINAL | 3320.001.01 Brannslokking Sprinkler våt 185
5515131 | 33.7 | 33.7 | 476.1 | ORIGINAL | 3320.001.01 Brannslokking Sprinkler våt 197
5517231 | 114.3 | 114.3 | 4070 | ORIGINAL | 3320.001.01 Brannslokking Sprinkler våt 2
5520869 | 33.7 | 33.7 | 333.614 | ORIGINAL | 3320.001.01 Brannslokking Sprinkler våt 210
5520882 | 33.7 | 33.7 | 333.614 | ORIGINAL | 3320.001.01 Brannslokking Sprinkler våt 210
5520916 | 48.3 | 48.3 | 3554.8 | ORIGINAL | 3320.001.01 Brannslokking Sprinkler våt 210
5521235 | 48.3 | 48.3 | 908.456 | ORIGINAL | 3320.001.01 Brannslokking Sprinkler våt 210
5521241 | 48.3 | 48.3 | 49.4 | ORIGINAL | 3320.001.01 Brannslokking Sprinkler våt 210
5521332 | 33.7 | 33.7 | 333.614 | ORIGINAL | 3320.001.01 Brannslokking Sprinkler våt 212
5521343 | 33.7 | 33.7 | 333.614 | ORIGINAL | 3320.001.01 Brannslokking Sprinkler våt 212
5521375 | 48.3 | 48.3 | 3554.8 | ORIGINAL | 3320.001.01 Brannslokking Sprinkler våt 212
5521409 | 48.3 | 48.3 | 908.456 | ORIGINAL | 3320.001.01 Brannslokking Sprinkler våt 212
5521411 | 48.3 | 48.3 | 49.4 | ORIGINAL | 3320.001.01 Brannslokking Sprinkler våt 212
5521484 | 33.7 | 33.7 | 344.764 | ORIGINAL | 3320.001.01 Brannslokking Sprinkler våt 214
5521495 | 33.7 | 33.7 | 334.614 | ORIGINAL | 3320.001.01 Brannslokking Sprinkler våt 214
5521527 | 33.7 | 33.7 | 3534.83 | ORIGINAL | 3320.001.01 Brannslokking Sprinkler våt 214
5521703 | 33.7 | 33.7 | 344.764 | ORIGINAL | 3320.001.01 Brannslokking Sprinkler våt 215
5521712 | 33.7 | 33.7 | 334.614 | ORIGINAL | 3320.001.01 Brannslokking Sprinkler våt 215
5521744 | 33.7 | 33.7 | 3534.83 | ORIGINAL | 3320.001.01 Brannslokking Sprinkler våt 215
5598128 | 76.1 | 76.1 | 657.357 | ORIGINAL | 3700.001.05 Kjøle Retur 18° 2
5598226 | 76.1 | 155.626 | 155.626 | ORIGINAL | 3700.001.05 Kjøle Retur 18° 2
5598286 | 76.1 | 76.1 | 107.001 | ORIGINAL | 3700.001.05 Kjøle Retur 18° 2
5598524 | 76.1 | 76.1 | 630.858 | ORIGINAL | 3700.001.04 Kjøle Tur 14° 1
5598665 | 76.1 | 155.626 | 155.626 | ORIGINAL | 3700.001.04 Kjøle Tur 14° 1
5598792 | 76.1 | 76.1 | 107.001 | ORIGINAL | 3700.001.04 Kjøle Tur 14° 1
5516883 | 114 | 114 | 12527 | RESULT | 3320.001.01 Brannslokking Sprinkler våt 173
5517243 | 114 | 114 | 5648 | RESULT | 3320.001.01 Brannslokking Sprinkler våt 2
5521525 | 42 | 42 | 1456 | RESULT | 3320.001.01 Brannslokking Sprinkler våt 214
5521742 | 42 | 42 | 1456 | RESULT | 3320.001.01 Brannslokking Sprinkler våt 215
5520914 | 42 | 42 | 1436 | RESULT | 3320.001.01 Brannslokking Sprinkler våt 210
5521373 | 42 | 42 | 1436 | RESULT | 3320.001.01 Brannslokking Sprinkler våt 212
5648770 | 76 | 76 | 10608 | RESULT | 3700.001.04 Kjøle Tur 14° 1
5648800 | 76 | 76 | 10623 | RESULT | 3700.001.05 Kjøle Retur 18° 2
5517218 | 114 | 114 | 6569 | RESULT | 3320.001.01 Brannslokking Sprinkler våt 2
5597701 | 76 | 76 | 812 | RESULT | 3700.001.05 Kjøle Retur 18° 2
5598395 | 76 | 76 | 853 | RESULT | 3700.001.04 Kjøle Tur 14° 1

# IfcFlowSegment: Round Duct:Sirkulær kanal (72)
Type - Material: 3601.001 Tilluft
ePset_Simplebim - Assembly Level: Leaf
Name (Round Duct:Sirkulær kanal:...) | In | Width (Simplebim) (mm) | Height (Simplebim) (mm) | Length (Simplebim) (mm) | Splitting | Group
5476159 | H01-Nivå D+0,36 | 250 | 250 | 455.575 | ORIGINAL | 36.03 Tilluft 1.etg nord og øst + nordfløy: 1
5480154 | H01-Nivå D+0,36 | 200 | 200 | 684.132 | ORIGINAL | 36.01 Tilluft Passasjerhall og kjeller: 2
5480172 | H01-Nivå D+0,36 | 200 | 200 | 684.132 | ORIGINAL | 36.01 Tilluft Passasjerhall og kjeller: 2
5480190 | H01-Nivå D+0,36 | 200 | 200 | 684.132 | ORIGINAL | 36.01 Tilluft Passasjerhall og kjeller: 2
5480208 | H01-Nivå D+0,36 | 200 | 200 | 684.132 | ORIGINAL | 36.01 Tilluft Passasjerhall og kjeller: 2
5480226 | H01-Nivå D+0,36 | 200 | 200 | 684.132 | ORIGINAL | 36.01 Tilluft Passasjerhall og kjeller: 2
5480244 | H01-Nivå D+0,36 | 200 | 200 | 684.132 | ORIGINAL | 36.01 Tilluft Passasjerhall og kjeller: 2
5480262 | H01-Nivå D+0,36 | 200 | 200 | 684.132 | ORIGINAL | 36.01 Tilluft Passasjerhall og kjeller: 2
5480280 | H01-Nivå D+0,36 | 200 | 200 | 684.132 | ORIGINAL | 36.01 Tilluft Passasjerhall og kjeller: 2
5490934 | H01-Nivå D+0,36 | 200 | 200 | 4741.53 | ORIGINAL | 36.03 Avtrekk 1.etg nord og øst + nordfløy: 1
5490950 | H01-Nivå D+0,36 | 200 | 200 | 133.275 | ORIGINAL | 36.03 Avtrekk 1.etg nord og øst + nordfløy: 1
5490952 | H01-Nivå D+0,36 | 200 | 200 | 123.5 | ORIGINAL | 36.03 Avtrekk 1.etg nord og øst + nordfløy: 1
5490967 | H01-Nivå D+0,36 | 200 | 200 | 4741.53 | ORIGINAL | 36.03 Avtrekk 1.etg nord og øst + nordfløy: 1
5490983 | H01-Nivå D+0,36 | 200 | 200 | 133.275 | ORIGINAL | 36.03 Avtrekk 1.etg nord og øst + nordfløy: 1
5490985 | H01-Nivå D+0,36 | 200 | 200 | 123.5 | ORIGINAL | 36.03 Avtrekk 1.etg nord og øst + nordfløy: 1
5510921 | H01-Nivå D+0,36 | 160 | 45.0008 | 160.155 | ORIGINAL | 36.26 Tilluft Bagasjehall 1.etg: 1
5510925 | H01-Nivå D+0,36 | 160 | 160 | 313.081 | ORIGINAL | 36.26 Tilluft Bagasjehall 1.etg: 1
5510929 | H01-Nivå D+0,36 | 200 | 200 | 452.71 | ORIGINAL | 36.26 Tilluft Bagasjehall 1.etg: 1
5510933 | H01-Nivå D+0,36 | 160 | 160 | 3941.02 | ORIGINAL | 36.26 Tilluft Bagasjehall 1.etg: 1
5510935 | H01-Nivå D+0,36 | 160 | 378.051 | 378.051 | ORIGINAL | 36.26 Tilluft Bagasjehall 1.etg: 1
5510939 | H01-Nivå D+0,36 | 160 | 160 | 230.586 | ORIGINAL | 36.26 Tilluft Bagasjehall 1.etg: 1
5510943 | H01-Nivå D+0,36 | 160 | 160 | 220 | ORIGINAL | 36.26 Tilluft Bagasjehall 1.etg: 1
5511035 | H01-Nivå D+0,36 | 160 | 160 | 3747.04 | ORIGINAL | 36.26 Tilluft Bagasjehall 1.etg: 1
5511041 | H01-Nivå D+0,36 | 160 | 378.051 | 378.051 | ORIGINAL | 36.26 Tilluft Bagasjehall 1.etg: 1
5511045 | H01-Nivå D+0,36 | 160 | 160 | 169.481 | ORIGINAL | 36.26 Tilluft Bagasjehall 1.etg: 1
5511049 | H01-Nivå D+0,36 | 160 | 160 | 227.5 | ORIGINAL | 36.26 Tilluft Bagasjehall 1.etg: 1
5512103 | H01-Nivå D+0,36 | 160 | 208.452 | 212.313 | ORIGINAL | 36.26 Tilluft Bagasjehall 1.etg: 1
5513786 | H01-Nivå D+0,36 | 200 | 200 | 520 | ORIGINAL | 36.26 Tilluft Bagasjehall 1.etg: 1
5513796 | H01-Nivå D+0,36 | 160 | 160 | 5413.56 | ORIGINAL | 36.26 Tilluft Bagasjehall 1.etg: 1
5553130 | H01-Nivå D+0,36 | 200 | 461.536 | 461.536 | ORIGINAL | 36.03 Avtrekk 1.etg nord og øst + nordfløy: 1
5553191 | H01-Nivå D+0,36 | 200 | 461.536 | 461.536 | ORIGINAL | 36.03 Avtrekk 1.etg nord og øst + nordfløy: 1
5553863 | H01-Nivå D+0,36 | 200 | 480.943 | 480.943 | ORIGINAL | 36.01 Tilluft Passasjerhall og kjeller: 2
5553870 | H01-Nivå D+0,36 | 200 | 480.943 | 480.943 | ORIGINAL | 36.01 Tilluft Passasjerhall og kjeller: 2
5553877 | H01-Nivå D+0,36 | 200 | 480.943 | 480.943 | ORIGINAL | 36.01 Tilluft Passasjerhall og kjeller: 2
5553884 | H01-Nivå D+0,36 | 200 | 480.943 | 480.943 | ORIGINAL | 36.01 Tilluft Passasjerhall og kjeller: 2
5553891 | H01-Nivå D+0,36 | 200 | 480.943 | 480.943 | ORIGINAL | 36.01 Tilluft Passasjerhall og kjeller: 2
5553898 | H01-Nivå D+0,36 | 200 | 480.943 | 480.943 | ORIGINAL | 36.01 Tilluft Passasjerhall og kjeller: 2
5553905 | H01-Nivå D+0,36 | 200 | 480.943 | 480.943 | ORIGINAL | 36.01 Tilluft Passasjerhall og kjeller: 2
5553912 | H01-Nivå D+0,36 | 200 | 480.943 | 480.943 | ORIGINAL | 36.01 Tilluft Passasjerhall og kjeller: 2
5559981 | H01-Nivå D+0,36 | 250 | 563.994 | 563.994 | ORIGINAL | 36.03 Tilluft 1.etg nord og øst + nordfløy: 1
5612071 | H01-Nivå D+0,36 | 250 | 250 | 8042.55 | ORIGINAL | 360.041 Tilluft Nytt system Nord: 3
5845893 | H01-Nivå D+0,36 | 160 | 160 | 78.5718 | ORIGINAL | 36.02 Avtrekk 1.etg syd og vest: 5
5845896 | H01-Nivå D+0,36 | 160 | 160 | 220 | ORIGINAL | 36.02 Avtrekk 1.etg syd og vest: 5
5845899 | H01-Nivå D+0,36 | 160 | 160 | 67.5 | ORIGINAL | 36.02 Avtrekk 1.etg syd og vest: 5
5846010 | H01-Nivå D+0,36 | 160 | 160 | 80 | ORIGINAL | 36.02 Avtrekk 1.etg syd og vest: 5
5846144 | H01-Nivå D+0,36 | 125 | 125 | 478.75 | ORIGINAL | 36.02 Tilluft 1.etg syd og vest: 9
5846147 | H01-Nivå D+0,36 | 125 | 125 | 456.25 | ORIGINAL | 36.02 Tilluft 1.etg syd og vest: 9
5846149 | H01-Nivå D+0,36 | 160 | 160 | 475.213 | ORIGINAL | 36.02 Tilluft 1.etg syd og vest: 9
5846153 | H01-Nivå D+0,36 | 160 | 160 | 48.9261 | ORIGINAL | 36.02 Tilluft 1.etg syd og vest: 9
5846155 | H01-Nivå D+0,36 | 160 | 160 | 39.5031 | ORIGINAL | 36.02 Tilluft 1.etg syd og vest: 9
5846161 | H01-Nivå D+0,36 | 160 | 160 | 224.041 | ORIGINAL | 36.02 Tilluft 1.etg syd og vest: 9
5846441 | H01-Nivå D+0,36 | 160 | 160 | 609.176 | ORIGINAL | 36.02 Tilluft 1.etg syd og vest: 9
5847791 | H01-Nivå D+0,36 | 244.619 | 315 | 323.096 | ORIGINAL | 360.041 Tilluft Nytt system Nord: 3
5847973 | H01-Nivå D+0,36 | 250 | 250 | 155.12 | ORIGINAL | 360.041 Tilluft Nytt system Nord: 3; 36.02 Tilluft 1.etg syd og vest: 14
5848035 | H01-Nivå D+0,36 | 250 | 250 | 227.62 | ORIGINAL | 36.02 Tilluft 1.etg syd og vest: 16
5848581 | H01-Nivå D+0,36 | 315 | 315 | 4320 | ORIGINAL | 360.041 Tilluft Nytt system Nord: 3
5525111 | H02-Nivå F-3,5 m | 800 | 800 | 12527 | RESULT
5524741 | H02-Nivå F-3,5 m | 800 | 800 | 12527 | RESULT
5610816 | H01-Nivå D+0,36 | 201 | 110 | 2458 | RESULT | 360.041 Avtrekk Nytt system Nord: 6
5474810 | H01-Nivå D+0,36 | 501 | 260 | 12458 | RESULT | 36.03 Tilluft 1.etg nord og øst + nordfløy: 1
5480667 | H01-Nivå D+0,36 | 630 | 340 | 12527 | RESULT | 36.01 Tilluft Passasjerhall og kjeller: 2
5596816 | H01-Nivå D+0,36 | 500 | 360 | 12331 | RESULT | 36.03 Avtrekk 1.etg nord og øst + nordfløy: 1
5510919 | H01-Nivå D+0,36 | 200 | 200 | 2825 | RESULT | 36.26 Tilluft Bagasjehall 1.etg: 1
5511015 | H01-Nivå D+0,36 | 160 | 160 | 3409 | RESULT | 36.26 Tilluft Bagasjehall 1.etg: 1
5512904 | H01-Nivå D+0,36 | 200 | 200 | 2007 | RESULT | 36.26 Tilluft Bagasjehall 1.etg: 1
5610840 | H01-Nivå D+0,36 | 201 | 110 | 2778 | RESULT | 360.041 Tilluft Nytt system Nord: 4; 36.02 Tilluft 1.etg syd og vest: 9
5513686 | H01-Nivå D+0,36 | 160 | 160 | 2683 | RESULT | 36.26 Tilluft Bagasjehall 1.etg: 1
5513819 | H01-Nivå D+0,36 | 160 | 160 | 2648 | RESULT | 36.26 Tilluft Bagasjehall 1.etg: 1
5490942 | H01-Nivå D+0,36 | 160 | 160 | 555 | RESULT | 36.03 Avtrekk 1.etg nord og øst + nordfløy: 1
5490946 | H01-Nivå D+0,36 | 160 | 160 | 555 | RESULT | 36.03 Avtrekk 1.etg nord og øst + nordfløy: 1
5490975 | H01-Nivå D+0,36 | 160 | 160 | 555 | RESULT | 36.03 Avtrekk 1.etg nord og øst + nordfløy: 1
5490979 | H01-Nivå D+0,36 | 160 | 160 | 555 | RESULT | 36.03 Avtrekk 1.etg nord og øst + nordfløy: 1

# IfcFlowTerminal: Orion-LOV-TA+Luna:Orion-LOV-TA-315+Luna-250-315 (2)
In: H01-Nivå D+0,36
Type - Material: 3601.001 Tilluft
ePset_LocationTool - Splitting: RESULT
ePset_Simplebim - Assembly Level: Leaf
Name (Orion-LOV-TA+Luna:Orion-LOV-TA-315+Luna-250-315:...) | Group
5848034 | 36.02 Tilluft 1.etg syd og vest: 16
5847666 | 36.02 Tilluft 1.etg syd og vest: 14

# IfcFlowTerminal: SU-15-K80-68DGR-STD:SU-15-K80-68DGR-STD (12)
In: H01-Nivå D+0,36
Type - Material: 3320.001
ePset_Simplebim - Assembly Level: Leaf
ePset_LocationTool - Splitting: ORIGINAL
Name (SU-15-K80-68DGR-STD:SU-15-K80-68DGR-STD:...) | Group
5514180 | 3320.001.01 Brannslokking Sprinkler våt 182
5514204 | 3320.001.01 Brannslokking Sprinkler våt 182
5514232 | 3320.001.01 Brannslokking Sprinkler våt 182
5514732 | 3320.001.01 Brannslokking Sprinkler våt 183
5514756 | 3320.001.01 Brannslokking Sprinkler våt 183
5514784 | 3320.001.01 Brannslokking Sprinkler våt 183
5514875 | 3320.001.01 Brannslokking Sprinkler våt 184
5514899 | 3320.001.01 Brannslokking Sprinkler våt 184
5514927 | 3320.001.01 Brannslokking Sprinkler våt 184
5515016 | 3320.001.01 Brannslokking Sprinkler våt 185
5515040 | 3320.001.01 Brannslokking Sprinkler våt 185
5515068 | 3320.001.01 Brannslokking Sprinkler våt 185

# IfcFlowTerminal: UD2002 Spredenett - 2 uttak - Påvegg_Vegg:UD2002, UD2002 Spredenett - 2 uttak - Påvegg_Vegg:UD2002:3027100
In: H01-Nivå D+0,36
Type - Material: Plastic - White
Classification: UD002 (Uniformat)
ePset_Simplebim - Assembly Level: Leaf
ePset_LocationTool - Splitting: ORIGINAL

# IfcMember: Rectangular Mullion:80 x 50 mm (71)
In: H02-Nivå F-3,5 m
Type - PredefinedType: MULLION; Material: Metal - Aluminium
ePset_SimplebimBasicQuantities - Width (Simplebim): 50 mm
ePset_Simplebim - Assembly Level: Leaf
Pset_MemberCommon - Reference: Rectangular Mullion:80 x 50 mm
ePset_LocationTool - Splitting: ORIGINAL
Name (Rectangular Mullion:80 x 50 mm:...) | Area, sides, net (Simplebim) (m2) | Volume, net (Simplebim) (m3) | Length (Simplebim) (mm) | Height (Simplebim) (mm) | Weight, as steel (Simplebim) (kg)
12568826 | 0.164 | 0.0024 | 80 | 600 | 18.84
12568827 | 0.3148 | 0.00472 | 1180 | 80 | 37.052
12568828 | 0.2316 | 0.00344 | 80 | 860 | 27.004
12568829 | 0.299633 | 0.00448667 | 1121.67 | 80 | 35.2203
12568830 | 0.2108 | 0.00312 | 80 | 780 | 24.492
12568831 | 0.2108 | 0.00312 | 80 | 780 | 24.492
12568832 | 0.2108 | 0.00312 | 80 | 780 | 24.492
12568833 | 0.2108 | 0.00312 | 80 | 780 | 24.492
12568834 | 0.2108 | 0.00312 | 80 | 780 | 24.492
12568835 | 0.2108 | 0.00312 | 80 | 780 | 24.492
12568836 | 0.2108 | 0.00312 | 80 | 780 | 24.492
12568837 | 0.2108 | 0.00312 | 80 | 780 | 24.492
12568838 | 0.2108 | 0.00312 | 80 | 780 | 24.492
12568839 | 0.268433 | 0.00400667 | 1001.67 | 80 | 31.4523
12568840 | 0.2784 | 0.00416 | 1040 | 80 | 32.656
12568841 | 0.2797 | 0.00418 | 1045 | 80 | 32.813
12568842 | 0.2784 | 0.00416 | 1040 | 80 | 32.656
12568843 | 0.2797 | 0.00418 | 1045 | 80 | 32.813
12568844 | 0.2771 | 0.00414 | 1035 | 80 | 32.499
12568845 | 0.2784 | 0.00416 | 1040 | 80 | 32.656
12568846 | 0.278833 | 0.00416667 | 1041.67 | 80 | 32.7083
12568847 | 0.278833 | 0.00416667 | 1041.67 | 80 | 32.7083
12568848 | 0.268433 | 0.00400667 | 1001.67 | 80 | 31.4523
12568849 | 0.2836 | 0.00424 | 1060 | 80 | 33.284
12568850 | 0.2784 | 0.00416 | 1040 | 80 | 32.656
12568851 | 0.2797 | 0.00418 | 1045 | 80 | 32.813
12568852 | 0.2784 | 0.00416 | 1040 | 80 | 32.656
12568853 | 0.2797 | 0.00418 | 1045 | 80 | 32.813
12568854 | 0.2771 | 0.00414 | 1035 | 80 | 32.499
12568855 | 0.2784 | 0.00416 | 1040 | 80 | 32.656
12568856 | 0.278833 | 0.00416667 | 1041.67 | 80 | 32.7083
12568857 | 0.278833 | 0.00416667 | 1041.67 | 80 | 32.7083
12568859 | 0.3096 | 0.00464 | 1160 | 80 | 36.424
12568860 | 0.3005 | 0.0045 | 1125 | 80 | 35.325
12568861 | 0.2992 | 0.00448 | 1120 | 80 | 35.168
12568862 | 0.3005 | 0.0045 | 1125 | 80 | 35.325
12568863 | 0.2979 | 0.00446 | 1115 | 80 | 35.011
12568864 | 0.2992 | 0.00448 | 1120 | 80 | 35.168
12568865 | 0.299633 | 0.00448667 | 1121.67 | 80 | 35.2203
12568866 | 0.299633 | 0.00448667 | 1121.67 | 80 | 35.2203
12568867 | 0.4396 | 0.00664 | 80 | 1660 | 52.124
12568868 | 0.164 | 0.0024 | 80 | 600 | 18.84
12568869 | 0.2992 | 0.00448 | 1120 | 80 | 35.168
12568870 | 0.3005 | 0.0045 | 1125 | 80 | 35.325
12568871 | 0.2992 | 0.00448 | 1120 | 80 | 35.168
12568872 | 0.3005 | 0.0045 | 1125 | 80 | 35.325
12568873 | 0.2979 | 0.00446 | 1115 | 80 | 35.011
12568874 | 0.2992 | 0.00448 | 1120 | 80 | 35.168
12568875 | 0.299633 | 0.00448667 | 1121.67 | 80 | 35.2203
12568876 | 0.299633 | 0.00448667 | 1121.67 | 80 | 35.2203
12568877 | 0.299633 | 0.00448667 | 1121.67 | 80 | 35.2203
12568878 | 0.2108 | 0.00312 | 80 | 780 | 24.492
12568879 | 0.4396 | 0.00664 | 80 | 1660 | 52.124
12568880 | 0.4396 | 0.00664 | 80 | 1660 | 52.124
12568881 | 0.164 | 0.0024 | 80 | 600 | 18.84
12568882 | 0.4396 | 0.00664 | 80 | 1660 | 52.124
12568883 | 0.164 | 0.0024 | 80 | 600 | 18.84
12568884 | 0.4396 | 0.00664 | 80 | 1660 | 52.124
12568885 | 0.164 | 0.0024 | 80 | 600 | 18.84
12568886 | 0.4396 | 0.00664 | 80 | 1660 | 52.124
12568887 | 0.164 | 0.0024 | 80 | 600 | 18.84
12568888 | 0.4396 | 0.00664 | 80 | 1660 | 52.124
12568889 | 0.164 | 0.0024 | 80 | 600 | 18.84
12568890 | 0.4396 | 0.00664 | 80 | 1660 | 52.124
12568891 | 0.164 | 0.0024 | 80 | 600 | 18.84
12568892 | 0.4396 | 0.00664 | 80 | 1660 | 52.124
12568893 | 0.164 | 0.0024 | 80 | 600 | 18.84
12568894 | 0.4396 | 0.00664 | 80 | 1660 | 52.124
12568895 | 0.164 | 0.0024 | 80 | 600 | 18.84
12568896 | 0.4396 | 0.00664 | 80 | 1660 | 52.124
12568897 | 0.164 | 0.0024 | 80 | 600 | 18.84

# IfcMember: Rectangular Mullion:Flesland Int 25x125 (123)
In: H02-Nivå F-3,5 m
Type - PredefinedType: MULLION; Material: Laminate - Ivory, Matte
ePset_Simplebim - Assembly Level: Leaf
Pset_MemberCommon - Reference: Rectangular Mullion:Flesland Int 25x125
Name (Rectangular Mullion:Flesland Int 25x125:...) | Splitting | Area, sides, net (Simplebim) (m2) | Volume, net (Simplebim) (m3) | Weight, as steel (Simplebim) (kg) | Width (Simplebim) (mm) | Length (Simplebim) (mm) | Height (Simplebim) (mm)
867972 | ORIGINAL | 0.21955 | 0.00222188 | 17.4417 | 25 | 125 | 711
867973 | ORIGINAL | 0.21955 | 0.00222188 | 17.4417 | 25 | 125 | 711
867974 | ORIGINAL | 0.21955 | 0.00222188 | 17.4417 | 25 | 125 | 711
867975 | ORIGINAL | 0.21955 | 0.00222188 | 17.4417 | 25 | 125 | 711
867976 | ORIGINAL | 0.21955 | 0.00222188 | 17.4417 | 25 | 125 | 711
867977 | ORIGINAL | 0.21955 | 0.00222188 | 17.4417 | 25 | 125 | 711
868016 | ORIGINAL | 0.44875 | 0.00460938 | 36.1836 | 125 | 1475 | 25
868017 | ORIGINAL | 0.44875 | 0.00460938 | 36.1836 | 125 | 1475 | 25
868018 | ORIGINAL | 0.44875 | 0.00460938 | 36.1836 | 125 | 1475 | 25
868019 | ORIGINAL | 0.44875 | 0.00460938 | 36.1836 | 125 | 1475 | 25
868020 | ORIGINAL | 0.44875 | 0.00460938 | 36.1836 | 125 | 1475 | 25
868021 | ORIGINAL | 0.44875 | 0.00460938 | 36.1836 | 125 | 1475 | 25
868022 | ORIGINAL | 0.44875 | 0.00460938 | 36.1836 | 125 | 1475 | 25
868023 | ORIGINAL | 0.25675 | 0.00260937 | 20.4836 | 125 | 835 | 25
868040 | ORIGINAL | 0.44875 | 0.00460938 | 36.1836 | 125 | 1475 | 25
868041 | ORIGINAL | 0.44875 | 0.00460938 | 36.1836 | 125 | 1475 | 25
868042 | ORIGINAL | 0.44875 | 0.00460938 | 36.1836 | 125 | 1475 | 25
868043 | ORIGINAL | 0.44875 | 0.00460938 | 36.1836 | 125 | 1475 | 25
868044 | ORIGINAL | 0.44875 | 0.00460938 | 36.1836 | 125 | 1475 | 25
868045 | ORIGINAL | 0.44875 | 0.00460938 | 36.1836 | 125 | 1475 | 25
868046 | ORIGINAL | 0.44875 | 0.00460938 | 36.1836 | 125 | 1475 | 25
868047 | ORIGINAL | 0.25675 | 0.00260937 | 20.4836 | 125 | 835 | 25
868064 | ORIGINAL | 0.44875 | 0.00460938 | 36.1836 | 125 | 1475 | 25
868065 | ORIGINAL | 0.44875 | 0.00460938 | 36.1836 | 125 | 1475 | 25
868066 | ORIGINAL | 0.44875 | 0.00460938 | 36.1836 | 125 | 1475 | 25
868067 | ORIGINAL | 0.44875 | 0.00460938 | 36.1836 | 125 | 1475 | 25
868068 | ORIGINAL | 0.44875 | 0.00460938 | 36.1836 | 125 | 1475 | 25
868069 | ORIGINAL | 0.44875 | 0.00460938 | 36.1836 | 125 | 1475 | 25
868070 | ORIGINAL | 0.44875 | 0.00460938 | 36.1836 | 125 | 1475 | 25
868071 | ORIGINAL | 0.25675 | 0.00260937 | 20.4836 | 125 | 835 | 25
868088 | ORIGINAL | 0.44875 | 0.00460938 | 36.1836 | 125 | 1475 | 25
868089 | ORIGINAL | 0.44875 | 0.00460938 | 36.1836 | 125 | 1475 | 25
868090 | ORIGINAL | 0.44875 | 0.00460938 | 36.1836 | 125 | 1475 | 25
868091 | ORIGINAL | 0.44875 | 0.00460938 | 36.1836 | 125 | 1475 | 25
868092 | ORIGINAL | 0.44875 | 0.00460938 | 36.1836 | 125 | 1475 | 25
868093 | ORIGINAL | 0.44875 | 0.00460938 | 36.1836 | 125 | 1475 | 25
868094 | ORIGINAL | 0.44875 | 0.00460938 | 36.1836 | 125 | 1475 | 25
868095 | ORIGINAL | 0.25675 | 0.00260937 | 20.4836 | 125 | 835 | 25
868112 | ORIGINAL | 0.44875 | 0.00460938 | 36.1836 | 125 | 1475 | 25
868113 | ORIGINAL | 0.44875 | 0.00460938 | 36.1836 | 125 | 1475 | 25
868114 | ORIGINAL | 0.44875 | 0.00460938 | 36.1836 | 125 | 1475 | 25
868115 | ORIGINAL | 0.44875 | 0.00460938 | 36.1836 | 125 | 1475 | 25
868116 | ORIGINAL | 0.44875 | 0.00460938 | 36.1836 | 125 | 1475 | 25
868117 | ORIGINAL | 0.44875 | 0.00460938 | 36.1836 | 125 | 1475 | 25
868118 | ORIGINAL | 0.44875 | 0.00460938 | 36.1836 | 125 | 1475 | 25
868119 | ORIGINAL | 0.25675 | 0.00260937 | 20.4836 | 125 | 835 | 25
868136 | ORIGINAL | 0.44875 | 0.00460938 | 36.1836 | 125 | 1475 | 25
868137 | ORIGINAL | 0.44875 | 0.00460938 | 36.1836 | 125 | 1475 | 25
868138 | ORIGINAL | 0.44875 | 0.00460938 | 36.1836 | 125 | 1475 | 25
868139 | ORIGINAL | 0.44875 | 0.00460938 | 36.1836 | 125 | 1475 | 25
868140 | ORIGINAL | 0.44875 | 0.00460938 | 36.1836 | 125 | 1475 | 25
868141 | ORIGINAL | 0.44875 | 0.00460938 | 36.1836 | 125 | 1475 | 25
868142 | ORIGINAL | 0.44875 | 0.00460938 | 36.1836 | 125 | 1475 | 25
868143 | ORIGINAL | 0.25675 | 0.00260937 | 20.4836 | 125 | 835 | 25
868160 | ORIGINAL | 0.44875 | 0.00460938 | 36.1836 | 125 | 1475 | 25
868161 | ORIGINAL | 0.44875 | 0.00460938 | 36.1836 | 125 | 1475 | 25
868162 | ORIGINAL | 0.44875 | 0.00460938 | 36.1836 | 125 | 1475 | 25
868163 | ORIGINAL | 0.44875 | 0.00460938 | 36.1836 | 125 | 1475 | 25
868164 | ORIGINAL | 0.44875 | 0.00460938 | 36.1836 | 125 | 1475 | 25
868165 | ORIGINAL | 0.44875 | 0.00460938 | 36.1836 | 125 | 1475 | 25
868166 | ORIGINAL | 0.44875 | 0.00460938 | 36.1836 | 125 | 1475 | 25
868167 | ORIGINAL | 0.25675 | 0.00260937 | 20.4836 | 125 | 835 | 25
868374 | ORIGINAL | 0.21955 | 0.00222188 | 17.4417 | 25 | 125 | 711
868375 | ORIGINAL | 0.21955 | 0.00222188 | 17.4417 | 25 | 125 | 711
868376 | ORIGINAL | 0.21955 | 0.00222188 | 17.4417 | 25 | 125 | 711
868377 | ORIGINAL | 0.21955 | 0.00222188 | 17.4417 | 25 | 125 | 711
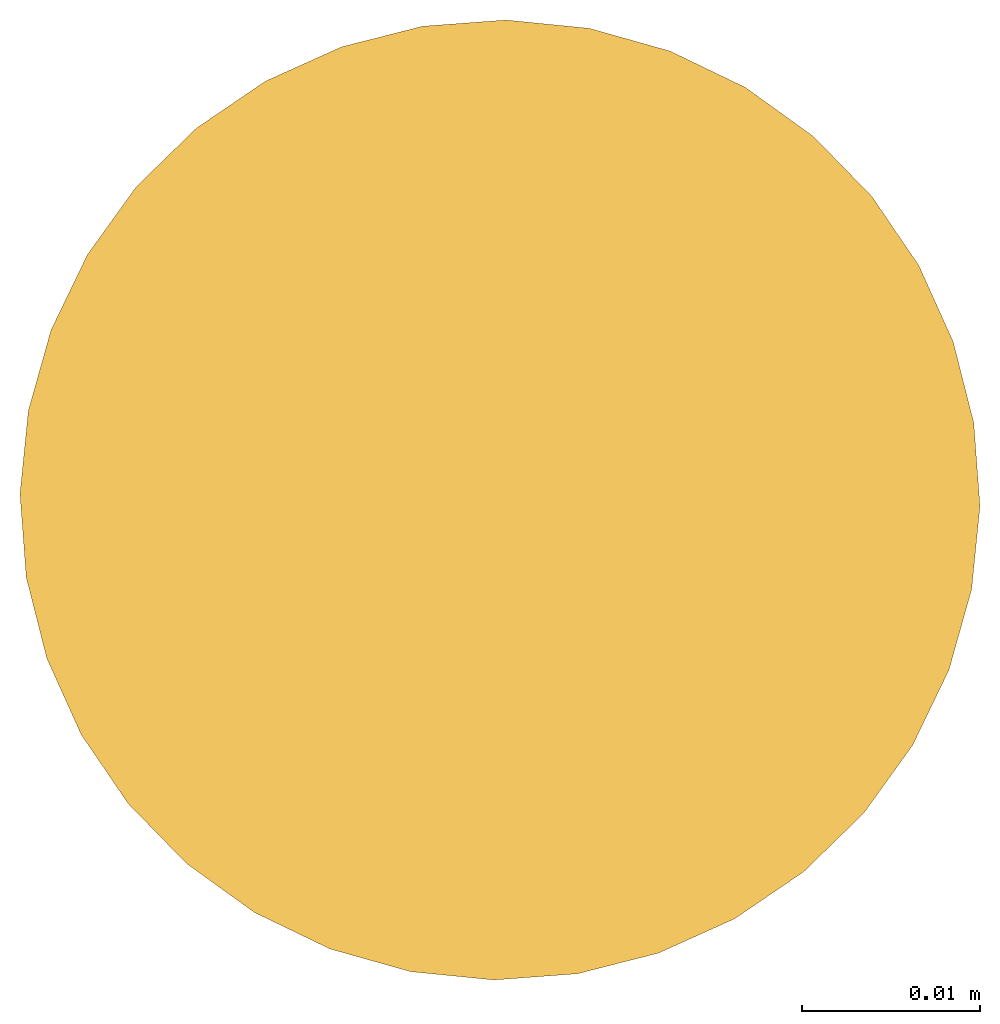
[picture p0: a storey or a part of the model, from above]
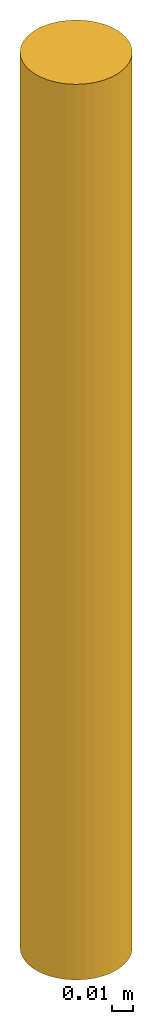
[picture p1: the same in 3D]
Properties of the parts of a building model (IFC2X3), part 3 of 3

# IfcMember: Rectangular Mullion:Flesland Int 25x125 (123)
Name (Rectangular Mullion:Flesland Int 25x125:...) | Splitting | Area, sides, net (Simplebim) (m2) | Volume, net (Simplebim) (m3) | Weight, as steel (Simplebim) (kg) | Width (Simplebim) (mm) | Length (Simplebim) (mm) | Height (Simplebim) (mm)
868378 | ORIGINAL | 0.21955 | 0.00222188 | 17.4417 | 25 | 125 | 711
868379 | ORIGINAL | 0.21955 | 0.00222188 | 17.4417 | 25 | 125 | 711
868380 | ORIGINAL | 0.21955 | 0.00222188 | 17.4417 | 25 | 125 | 711
868381 | ORIGINAL | 0.21955 | 0.00222188 | 17.4417 | 25 | 125 | 711
868397 | ORIGINAL | 0.21955 | 0.00222188 | 17.4417 | 25 | 125 | 711
868398 | ORIGINAL | 0.21955 | 0.00222188 | 17.4417 | 25 | 125 | 711
868399 | ORIGINAL | 0.21955 | 0.00222188 | 17.4417 | 25 | 125 | 711
868400 | ORIGINAL | 0.21955 | 0.00222188 | 17.4417 | 25 | 125 | 711
868401 | ORIGINAL | 0.21955 | 0.00222188 | 17.4417 | 25 | 125 | 711
868402 | ORIGINAL | 0.21955 | 0.00222188 | 17.4417 | 25 | 125 | 711
868403 | ORIGINAL | 0.21955 | 0.00222188 | 17.4417 | 25 | 125 | 711
868404 | ORIGINAL | 0.21955 | 0.00222188 | 17.4417 | 25 | 125 | 711
868420 | ORIGINAL | 0.21955 | 0.00222188 | 17.4417 | 25 | 125 | 711
868421 | ORIGINAL | 0.21955 | 0.00222188 | 17.4417 | 25 | 125 | 711
868422 | ORIGINAL | 0.21955 | 0.00222188 | 17.4417 | 25 | 125 | 711
868423 | ORIGINAL | 0.21955 | 0.00222188 | 17.4417 | 25 | 125 | 711
868424 | ORIGINAL | 0.21955 | 0.00222188 | 17.4417 | 25 | 125 | 711
868425 | ORIGINAL | 0.21955 | 0.00222188 | 17.4417 | 25 | 125 | 711
868426 | ORIGINAL | 0.21955 | 0.00222188 | 17.4417 | 25 | 125 | 711
868427 | ORIGINAL | 0.21955 | 0.00222188 | 17.4417 | 25 | 125 | 711
868443 | ORIGINAL | 0.21955 | 0.00222188 | 17.4417 | 25 | 125 | 711
868444 | ORIGINAL | 0.21955 | 0.00222188 | 17.4417 | 25 | 125 | 711
868445 | ORIGINAL | 0.21955 | 0.00222188 | 17.4417 | 25 | 125 | 711
868446 | ORIGINAL | 0.21955 | 0.00222188 | 17.4417 | 25 | 125 | 711
868447 | ORIGINAL | 0.21955 | 0.00222188 | 17.4417 | 25 | 125 | 711
868448 | ORIGINAL | 0.21955 | 0.00222188 | 17.4417 | 25 | 125 | 711
868449 | ORIGINAL | 0.21955 | 0.00222188 | 17.4417 | 25 | 125 | 711
868450 | ORIGINAL | 0.21955 | 0.00222188 | 17.4417 | 25 | 125 | 711
868466 | ORIGINAL | 0.21955 | 0.00222188 | 17.4417 | 25 | 125 | 711
868467 | ORIGINAL | 0.21955 | 0.00222188 | 17.4417 | 25 | 125 | 711
868468 | ORIGINAL | 0.21955 | 0.00222188 | 17.4417 | 25 | 125 | 711
868469 | ORIGINAL | 0.21955 | 0.00222188 | 17.4417 | 25 | 125 | 711
868470 | ORIGINAL | 0.21955 | 0.00222188 | 17.4417 | 25 | 125 | 711
868471 | ORIGINAL | 0.21955 | 0.00222188 | 17.4417 | 25 | 125 | 711
868472 | ORIGINAL | 0.21955 | 0.00222188 | 17.4417 | 25 | 125 | 711
868473 | ORIGINAL | 0.21955 | 0.00222188 | 17.4417 | 25 | 125 | 711
868489 | ORIGINAL | 0.21955 | 0.00222188 | 17.4417 | 25 | 125 | 711
868490 | ORIGINAL | 0.21955 | 0.00222188 | 17.4417 | 25 | 125 | 711
868491 | ORIGINAL | 0.21955 | 0.00222188 | 17.4417 | 25 | 125 | 711
868492 | ORIGINAL | 0.21955 | 0.00222188 | 17.4417 | 25 | 125 | 711
868493 | ORIGINAL | 0.21955 | 0.00222188 | 17.4417 | 25 | 125 | 711
868494 | ORIGINAL | 0.21955 | 0.00222188 | 17.4417 | 25 | 125 | 711
868495 | ORIGINAL | 0.21955 | 0.00222188 | 17.4417 | 25 | 125 | 711
868496 | ORIGINAL | 0.21955 | 0.00222188 | 17.4417 | 25 | 125 | 711
868787 | ORIGINAL | 0.21955 | 0.00222188 | 17.4417 | 25 | 125 | 711
868788 | ORIGINAL | 0.21955 | 0.00222188 | 17.4417 | 25 | 125 | 711
868789 | ORIGINAL | 0.21955 | 0.00222188 | 17.4417 | 25 | 125 | 711
868790 | ORIGINAL | 0.21955 | 0.00222188 | 17.4417 | 25 | 125 | 711
868791 | ORIGINAL | 0.21955 | 0.00222188 | 17.4417 | 25 | 125 | 711
868792 | ORIGINAL | 0.21955 | 0.00222188 | 17.4417 | 25 | 125 | 711
868159 | RESULT | 0.100307 | 0.000968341 | 7.60147 | 113 | 344 | 25
868111 | RESULT | 0.100307 | 0.000968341 | 7.60147 | 113 | 344 | 24
868135 | RESULT | 0.100307 | 0.000968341 | 7.60147 | 113 | 344 | 24
868087 | RESULT | 0.100307 | 0.000968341 | 7.60147 | 113 | 344 | 24
868063 | RESULT | 0.100307 | 0.000968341 | 7.60147 | 113 | 344 | 25
868039 | RESULT | 0.100307 | 0.000968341 | 7.60147 | 113 | 344 | 25
868015 | RESULT | 0.100307 | 0.000968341 | 7.60147 | 113 | 344 | 25

# IfcPlate: PL12*86 (2)
In: H01-Nivå D+0,36
Description: PL12*86
ePset_LocationTool - Splitting: ORIGINAL
ePset_Simplebim - Assembly Level: Leaf
ePset_SimplebimBasicQuantities - Weight, as steel (Simplebim): 2.97353 kg; Volume, net (Simplebim): 0.000378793 m3
Pset_PlateCommon - Reference: PL12*86
Name | Area, largest surface, net (Simplebim) (m2)
STÅLBJELKE | 0.0315731
STÅLBJELKE | 0.0315614

# IfcPlate: PL16*86 (2)
In: H01-Nivå D+0,36
Description: PL16*86
Pset_PlateCommon - Reference: PL16*86
ePset_LocationTool - Splitting: ORIGINAL
ePset_Simplebim - Assembly Level: Leaf
ePset_SimplebimBasicQuantities - Weight, as steel (Simplebim): 3.98668 kg; Volume, net (Simplebim): 0.000507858 m3
Name | Area, largest surface, net (Simplebim) (m2)
STÅLBJELKE | 0.0317364
STÅLBJELKE | 0.0317481

# IfcPlate: PL20*120 (2)
In: H01-Nivå D+0,36
Description: PL20*120
ePset_Simplebim - Assembly Level: Leaf
Pset_PlateCommon - Reference: PL20*120
ePset_LocationTool - Splitting: ORIGINAL
Name | Area, largest surface, net (Simplebim) (m2) | Weight, as steel (Simplebim) (kg) | Volume, net (Simplebim) (m3)
STÅLBJELKE | 0.096 | 15.072 | 0.00192
STÅLBJELKE | 0.04272 | 6.70704 | 0.0008544

# IfcPlate: PL20*180, STÅLBJELKE
In: H01-Nivå D+0,36
Description: PL20*180
ePset_Simplebim - Assembly Level: Leaf
ePset_SimplebimBasicQuantities - Volume, net (Simplebim): 0.001944 m3; Area, largest surface, net (Simplebim): 0.0972 m2; Weight, as steel (Simplebim): 15.2604 kg
Pset_PlateCommon - Reference: PL20*180
ePset_LocationTool - Splitting: ORIGINAL

# IfcPlate: System Panel:A234 - Systemglass (28)
In: H02-Nivå F-3,5 m
Type - PredefinedType: CURTAIN_PANEL; Material: _Flesland Glass
ePset_Simplebim - Assembly Level: Leaf
Pset_PlateCommon - Reference: System Panel:A234 - Systemglass
ePset_LocationTool - Splitting: ORIGINAL
Name (System Panel:A234 - Systemglass:...) | Volume, net (Simplebim) (m3) | Area, largest surface, net (Simplebim) (m2) | Weight, as steel (Simplebim) (kg)
12568171 | 0.0185308 | 0.741233 | 145.467
12568463 | 0.0192708 | 0.770833 | 151.276
12568432 | 0.0192708 | 0.770833 | 151.276
12568408 | 0.01924 | 0.7696 | 151.034
12568375 | 0.0191475 | 0.7659 | 150.308
12568345 | 0.0193325 | 0.7733 | 151.76
12568320 | 0.01924 | 0.7696 | 151.034
12568295 | 0.0193325 | 0.7733 | 151.76
12568256 | 0.01924 | 0.7696 | 151.034
12568744 | 0.0395658 | 1.58263 | 310.592
12568745 | 0.0411458 | 1.64583 | 322.995
12568746 | 0.0411458 | 1.64583 | 322.995
12568747 | 0.04108 | 1.6432 | 322.478
12568748 | 0.0408825 | 1.6353 | 320.928
12568749 | 0.0412775 | 1.6511 | 324.028
12568750 | 0.04108 | 1.6432 | 322.478
12568751 | 0.0412775 | 1.6511 | 324.028
12568752 | 0.04108 | 1.6432 | 322.478
12568782 | 0.0140233 | 0.560933 | 110.083
12568783 | 0.0145833 | 0.583333 | 114.479
12568784 | 0.0145833 | 0.583333 | 114.479
12568785 | 0.01456 | 0.5824 | 114.296
12568786 | 0.01449 | 0.5796 | 113.746
12568787 | 0.01463 | 0.5852 | 114.845
12568788 | 0.01456 | 0.5824 | 114.296
12568789 | 0.01463 | 0.5852 | 114.845
12568790 | 0.01456 | 0.5824 | 114.296
12568791 | 0.01484 | 0.5936 | 116.494

# IfcPlate: System Panel:Flesland int curt wall (21)
In: H02-Nivå F-3,5 m
Type - PredefinedType: CURTAIN_PANEL; Material: _NSW Glass
Pset_PlateCommon - Reference: System Panel:Flesland int curt wall
ePset_Simplebim - Assembly Level: Leaf
Name (System Panel:Flesland int curt wall:...) | Area, largest surface, net (Simplebim) (m2) | Volume, net (Simplebim) (m3) | Weight, as steel (Simplebim) (kg) | Splitting
867618 | 1.01185 | 0.0505925 | 397.151 | ORIGINAL
867619 | 1.01185 | 0.0505925 | 397.151 | ORIGINAL
867620 | 1.01185 | 0.0505925 | 397.151 | ORIGINAL
867643 | 1.01185 | 0.0505925 | 397.151 | ORIGINAL
867644 | 1.01185 | 0.0505925 | 397.151 | ORIGINAL
867645 | 1.01185 | 0.0505925 | 397.151 | ORIGINAL
867668 | 1.01185 | 0.0505925 | 397.151 | ORIGINAL
867669 | 1.01185 | 0.0505925 | 397.151 | ORIGINAL
867670 | 1.01185 | 0.0505925 | 397.151 | ORIGINAL
867671 | 1.01185 | 0.0505925 | 397.151 | ORIGINAL
867693 | 1.01185 | 0.0505925 | 397.151 | ORIGINAL
867694 | 1.01185 | 0.0505925 | 397.151 | ORIGINAL
867695 | 1.01185 | 0.0505925 | 397.151 | ORIGINAL
867696 | 1.01185 | 0.0505925 | 397.151 | ORIGINAL
867697 | 1.01185 | 0.0505925 | 397.151 | ORIGINAL
867698 | 1.01185 | 0.0505925 | 397.151 | ORIGINAL
867699 | 1.01185 | 0.0505925 | 397.151 | ORIGINAL
867667 | 0.236189 | 0.0118095 | 92.7042 | RESULT
867692 | 0.236189 | 0.0118095 | 92.7042 | RESULT
867642 | 0.236189 | 0.0118095 | 92.7042 | RESULT
867617 | 0.236189 | 0.0118095 | 92.7042 | RESULT

# IfcPlate: System Panel:Flesland int curt wall solid (33)
In: H02-Nivå F-3,5 m
Type - PredefinedType: CURTAIN_PANEL; Material: Flesland - Finishes - Interior - Metal Panel
Pset_PlateCommon - Reference: System Panel:Flesland int curt wall solid
ePset_Simplebim - Assembly Level: Leaf
Name (System Panel:Flesland int curt wall solid:...) | Splitting | Area, largest surface, net (Simplebim) (m2) | Volume, net (Simplebim) (m3) | Weight, as steel (Simplebim) (kg)
867593 | ORIGINAL | 1.01185 | 0.0505925 | 397.151
867594 | ORIGINAL | 1.01185 | 0.0505925 | 397.151
867595 | ORIGINAL | 1.01185 | 0.0505925 | 397.151
867596 | ORIGINAL | 1.01185 | 0.0505925 | 397.151
867597 | ORIGINAL | 1.01185 | 0.0505925 | 397.151
867598 | ORIGINAL | 1.01185 | 0.0505925 | 397.151
867599 | ORIGINAL | 1.01185 | 0.0505925 | 397.151
867600 | ORIGINAL | 0.57281 | 0.0286405 | 224.828
867621 | ORIGINAL | 1.01185 | 0.0505925 | 397.151
867622 | ORIGINAL | 1.01185 | 0.0505925 | 397.151
867623 | ORIGINAL | 1.01185 | 0.0505925 | 397.151
867624 | ORIGINAL | 1.01185 | 0.0505925 | 397.151
867625 | ORIGINAL | 0.57281 | 0.0286405 | 224.828
867646 | ORIGINAL | 1.01185 | 0.0505925 | 397.151
867647 | ORIGINAL | 1.01185 | 0.0505925 | 397.151
867648 | ORIGINAL | 1.01185 | 0.0505925 | 397.151
867649 | ORIGINAL | 1.01185 | 0.0505925 | 397.151
867650 | ORIGINAL | 0.57281 | 0.0286405 | 224.828
867672 | ORIGINAL | 1.01185 | 0.0505925 | 397.151
867673 | ORIGINAL | 1.01185 | 0.0505925 | 397.151
867674 | ORIGINAL | 1.01185 | 0.0505925 | 397.151
867675 | ORIGINAL | 0.57281 | 0.0286405 | 224.828
867700 | ORIGINAL | 0.57281 | 0.0286405 | 224.828
867718 | ORIGINAL | 1.01185 | 0.0505925 | 397.151
867719 | ORIGINAL | 1.01185 | 0.0505925 | 397.151
867720 | ORIGINAL | 1.01185 | 0.0505925 | 397.151
867721 | ORIGINAL | 1.01185 | 0.0505925 | 397.151
867722 | ORIGINAL | 1.01185 | 0.0505925 | 397.151
867723 | ORIGINAL | 1.01185 | 0.0505925 | 397.151
867724 | ORIGINAL | 1.01185 | 0.0505925 | 397.151
867725 | ORIGINAL | 0.57281 | 0.0286405 | 224.828
867717 | RESULT | 0.236189 | 0.00885709 | 69.5282
867592 | RESULT | 0.236189 | 0.00885709 | 69.5282

# IfcSlab: 200*565, PLASSTØPTDEKKE
In: H01-Nivå D+0,36
Type - PredefinedType: FLOOR
Description: 200*565
ePset_SimplebimBasicQuantities - Area, sides, net (Simplebim): 0.485979 m2; Volume, net (Simplebim): 0.07345 m3; Thickness (Simplebim): 200 mm; Area, top, net (Simplebim): 0.36726 m2; Area, largest surface, net (Simplebim): 0.36725 m2; Perimeter (Simplebim): 2429.89 mm
ePset_LocationTool - Splitting: ORIGINAL
ePset_Simplebim - Assembly Level: Leaf
Pset_SlabCommon - Reference: 200*565

# IfcSlab: 315*1300, PLASSTØPTDEKKE
In: H01-Nivå D+0,36
Type - PredefinedType: FLOOR
Description: 315*1300
ePset_LocationTool - Splitting: ORIGINAL
ePset_Simplebim - Assembly Level: Leaf
Pset_SlabCommon - Reference: 315*1300
ePset_SimplebimBasicQuantities - Volume, net (Simplebim): 0.266175 m3; Area, sides, net (Simplebim): 1.39805 m2; Area, top, net (Simplebim): 0.845033 m2; Thickness (Simplebim): 315 mm; Area, largest surface, net (Simplebim): 0.845 m2; Perimeter (Simplebim): 4438.26 mm

# IfcSlab: 90*250, PLASSTØPTDEKKE
In: H02-Nivå F-3,5 m
Type - PredefinedType: FLOOR
Description: 90*250
ePset_SimplebimBasicQuantities - Thickness (Simplebim): 90.0001 mm; Area, largest surface, net (Simplebim): 0.147172 m2; Volume, net (Simplebim): 0.0132461 m3; Area, top, net (Simplebim): 0.147168 m2; Area, sides, net (Simplebim): 0.150989 m2; Perimeter (Simplebim): 1677.66 mm
ePset_LocationTool - Splitting: RESULT
ePset_Simplebim - Assembly Level: Leaf
Pset_SlabCommon - Reference: 90*250

# IfcSlab: Floor:Generic 138mm, Floor:Generic 138mm:9242385
In: H02-Nivå F-3,5 m
Type - PredefinedType: FLOOR; Material: <Unnamed> 138 mm
ePset_SimplebimBasicQuantities - Area, top, net (Simplebim): 307.003 m2; Perimeter (Simplebim): 74262.1 mm; Area, sides, net (Simplebim): 10.2482 m2; Area, largest surface, net (Simplebim): 307.003 m2; Thickness (Simplebim): 138 mm; Volume, net (Simplebim): 42.3664 m3
ePset_Simplebim - Assembly Level: Leaf
ePset_LocationTool - Splitting: RESULT
Pset_SlabCommon - Reference: Floor:Generic 138mm

# IfcWall: Basic Wall:A242 - Standard 100, Basic Wall:A242 - Standard 100:11670776
In: H02-Nivå F-3,5 m
Type - PredefinedType: STANDARD; Material: _NSW Standard 100 mm
ePset_LocationTool - Splitting: RESULT
Pset_WallCommon - Reference: Basic Wall:A242 - Standard 100
ePset_SimplebimBasicQuantities - Volume, net (Simplebim): 0.300872 m3; Area, side, gross, AABB (Simplebim): 3.01 m2; Area, side, gross, smaller (Simplebim): 6.83073 m2; Area, side, gross, average (Simplebim): 6.83073 m2; Area, side, gross, larger (Simplebim): 6.83073 m2; Area, side, net, smaller (Simplebim): 3.00873 m2; Area, side, net, larger (Simplebim): 3.00873 m2; Area, largest surface, net (Simplebim): 3.00873 m2; Area, side, net, average (Simplebim): 3.00873 m2; Thickness (Simplebim): 100 mm; Length (Simplebim): 860 mm; Height (Simplebim): 3500 mm
ePset_Simplebim - Assembly Level: Leaf

# IfcWall: Basic Wall:A242 - Standard 136, Basic Wall:A242 - Standard 136:11658449
In: H02-Nivå F-3,5 m
Type - PredefinedType: STANDARD; Material: _NSW Standard 135 mm
ePset_SimplebimBasicQuantities - Volume, net (Simplebim): 0.166699 m3; Area, side, net, larger (Simplebim): 1.23481 m2; Area, side, net, average (Simplebim): 1.23481 m2; Area, largest surface, net (Simplebim): 1.23481 m2; Area, side, net, smaller (Simplebim): 1.23481 m2; Area, side, gross, AABB (Simplebim): 2.26135 m2; Thickness (Simplebim): 135 mm; Length (Simplebim): 637 mm; Height (Simplebim): 3550 mm; Area, side, gross, smaller (Simplebim): 3.14581 m2; Area, side, gross, larger (Simplebim): 3.14581 m2; Area, side, gross, average (Simplebim): 3.14581 m2
ePset_LocationTool - Splitting: RESULT
ePset_Simplebim - Assembly Level: Leaf
Pset_WallCommon - Reference: Basic Wall:A242 - Standard 136

# IfcWall: Basic Wall:A242 - Standard 225, Basic Wall:A242 - Standard 225:864982
In: H02-Nivå F-3,5 m
Type - PredefinedType: STANDARD; Material: _NSW Standard 225 mm
ePset_SimplebimBasicQuantities - Volume, net (Simplebim): 0.629776 m3; Area, largest surface, net (Simplebim): 2.79901 m2; Area, side, net, average (Simplebim): 2.79901 m2; Area, side, net, larger (Simplebim): 2.79901 m2; Area, side, net, smaller (Simplebim): 2.79901 m2; Area, side, gross, average (Simplebim): 4.71001 m2; Area, side, gross, larger (Simplebim): 4.71001 m2; Area, side, gross, smaller (Simplebim): 4.71001 m2; Area, side, gross, AABB (Simplebim): 3.0601 m2; Thickness (Simplebim): 226 mm; Length (Simplebim): 862 mm; Height (Simplebim): 3550 mm
ePset_Simplebim - Assembly Level: Leaf
ePset_LocationTool - Splitting: RESULT
Pset_WallCommon - Reference: Basic Wall:A242 - Standard 225

# IfcWall: Basic Wall:A242 - Standard 300, Basic Wall:A242 - Standard 300:11631420
In: H01-Nivå D+0,36
Type - PredefinedType: STANDARD; Material: _NSW Standard 300 mm
ePset_LocationTool - Splitting: RESULT
ePset_Simplebim - Assembly Level: Leaf
ePset_SimplebimBasicQuantities - Area, side, gross, average (Simplebim): 0.464637 m2; Area, side, gross, larger (Simplebim): 0.464637 m2; Area, side, net, average (Simplebim): 0.464637 m2; Area, largest surface, net (Simplebim): 0.464637 m2; Area, side, gross, smaller (Simplebim): 0.464637 m2; Area, side, net, larger (Simplebim): 0.464637 m2; Area, side, net, smaller (Simplebim): 0.464637 m2; Area, side, gross, AABB (Simplebim): 0.464618 m2; Thickness (Simplebim): 300 mm; Length (Simplebim): 539 mm; Height (Simplebim): 862 mm; Volume, net (Simplebim): 0.139391 m3
Pset_WallCommon - Reference: Basic Wall:A242 - Standard 300

# IfcWall: Basic Wall:NSW Utvendig - Standard 380 Panels, Basic Wall:NSW Utvendig - Standard 380 Panels:1103767
In: H03-Nivå G-5m
Type - PredefinedType: STANDARD; Material: Flesland - Finishes - Exterior - Metal Panel 20 mm, <Unnamed> 20 mm, A200 - Isolasjon - Trykkfast m skravur i snitt 340 mm
ePset_LocationTool - Splitting: RESULT
ePset_SimplebimBasicQuantities - Area, side, gross, AABB (Simplebim): 1.37816 m2; Area, side, gross, average (Simplebim): 1.27157 m2; Area, side, net, average (Simplebim): 1.27157 m2; Area, side, gross, larger (Simplebim): 1.37797 m2; Area, side, net, larger (Simplebim): 1.37797 m2; Thickness (Simplebim): 380 mm; Height (Simplebim): 280 mm; Length (Simplebim): 4922 mm; Area, largest surface, net (Simplebim): 1.7257 m2; Volume, net (Simplebim): 0.483197 m3; Area, side, net, smaller (Simplebim): 1.16517 m2; Area, side, gross, smaller (Simplebim): 1.16517 m2
ePset_Simplebim - Assembly Level: Leaf
Pset_WallCommon - Reference: Basic Wall:NSW Utvendig - Standard 380 Panels

# IfcWall: Basic Wall:NY IV120 (6)
In: H01-Nivå D+0,36
Type - PredefinedType: STANDARD; Material: _NSW Standard 120 mm
Pset_WallCommon - Reference: Basic Wall:NY IV120
ePset_SimplebimBasicQuantities - Thickness (Simplebim): 120 mm; Height (Simplebim): 760 mm
ePset_Simplebim - Assembly Level: Leaf
ePset_LocationTool - Splitting: RESULT
Name (Basic Wall:NY IV120:...) | Volume, net (Simplebim) (m3) | Area, side, gross, AABB (Simplebim) (m2) | Area, side, net, smaller (Simplebim) (m2) = Area, side, gross, smaller (Simplebim) (m2) = Area, side, net, larger (Simplebim) (m2) = Area, side, net, average (Simplebim) (m2) = Area, largest surface, net (Simplebim) (m2) = Area, side, gross, average (Simplebim) (m2) = Area, side, gross, larger (Simplebim) (m2) | Length (Simplebim) (mm)
12694200 | 0.119494 | 0.9956 | 0.995782 | 1310
12694203 | 0.298224 | 2.4852 | 2.4852 | 3270
13535286 | 0.188806 | 1.5732 | 1.57338 | 2070
13535287 | 0.152304 | 1.2692 | 1.2692 | 1670
12708504 | 1.56273 | 13.0226 | 13.0228 | 17135
13984910 | 0.119494 | 0.9956 | 0.995782 | 1310

# IfcWall: Basic Wall:NY IV120 EI60 (2)
In: H01-Nivå D+0,36
Type - PredefinedType: STANDARD; Material: _NSW Standard 120 mm
ePset_LocationTool - Splitting: RESULT
ePset_SimplebimBasicQuantities - Thickness (Simplebim): 120 mm
ePset_Simplebim - Assembly Level: Leaf
Pset_WallCommon - Reference: Basic Wall:NY IV120 EI60
Name (Basic Wall:NY IV120 EI60:...) | Area, side, net, larger (Simplebim) (m2) = Area, side, gross, smaller (Simplebim) (m2) = Area, largest surface, net (Simplebim) (m2) = Area, side, net, average (Simplebim) (m2) = Area, side, gross, larger (Simplebim) (m2) = Area, side, gross, average (Simplebim) (m2) = Area, side, net, smaller (Simplebim) (m2) | Area, side, gross, AABB (Simplebim) (m2) | Height (Simplebim) (mm) | Length (Simplebim) (mm) | Volume, net (Simplebim) (m3)
13958916 | 10.3339 | 10.3337 | 862 | 11988 | 1.24007
12702209 | 15.3216 | 15.3216 | 760 | 20160 | 1.83859

# IfcWall: Basic Wall:NY- lydabsorberende vegg passkontroll (3)
In: H01-Nivå D+0,36
Type - PredefinedType: STANDARD; Material: _NSW Standard 120 mm
ePset_Simplebim - Assembly Level: Leaf
Pset_WallCommon - Reference: Basic Wall:NY- lydabsorberende vegg passkontroll
ePset_SimplebimBasicQuantities - Thickness (Simplebim): 120 mm; Height (Simplebim): 760 mm
ePset_LocationTool - Splitting: RESULT
Name (Basic Wall:NY- lydabsorberende vegg passkontroll:...) | Volume, net (Simplebim) (m3) | Area, largest surface, net (Simplebim) (m2) = Area, side, net, average (Simplebim) (m2) = Area, side, gross, larger (Simplebim) (m2) = Area, side, gross, average (Simplebim) (m2) = Area, side, net, larger (Simplebim) (m2) = Area, side, gross, smaller (Simplebim) (m2) = Area, side, gross, AABB (Simplebim) (m2) = Area, side, net, smaller (Simplebim) (m2) | Length (Simplebim) (mm)
12694201 | 0.309168 | 2.5764 | 3390
12694202 | 0.16416 | 1.368 | 1800
13984893 | 0.175104 | 1.4592 | 1920

# IfcWallStandardCase: Basic Wall:A242 - Standard 100 (3)
In: H02-Nivå F-3,5 m
Type - PredefinedType: STANDARD; Material: _NSW Standard 100 mm
Pset_WallCommon - Reference: Basic Wall:A242 - Standard 100
ePset_Simplebim - Assembly Level: Leaf
ePset_LocationTool - Splitting: ORIGINAL
ePset_SimplebimBasicQuantities - Thickness (Simplebim): 100 mm
Name (Basic Wall:A242 - Standard 100:...) | Length (Simplebim) (mm) | Area, side, gross, smaller (Simplebim) (m2) = Area, side, net, smaller (Simplebim) (m2) | Area, side, net, larger (Simplebim) (m2) = Area, largest surface, net (Simplebim) (m2) = Area, side, gross, larger (Simplebim) (m2) | Area, side, net, average (Simplebim) (m2) = Area, side, gross, average (Simplebim) (m2) | Volume, net (Simplebim) (m3) | Height (Simplebim) (mm) | Area, side, gross, AABB (Simplebim) (m2)
12509476 | 16356.3 | 63.5904 | 63.5904 | 63.5904 | 6.35904 | 3900 | 63.7896
12569532 | 5910.54 | 18.9088 | 18.9137 | 18.9112 | 1.89112 | 3200 | 18.9137
12569601 | 5696.04 | 18.2224 | 18.2273 | 18.2248 | 1.82248 | 3200 | 18.2273

# IfcWallStandardCase: Basic Wall:A242 - Standard 120 (8)
In: H02-Nivå F-3,5 m
Type - PredefinedType: STANDARD; Material: _NSW Standard 120 mm
ePset_LocationTool - Splitting: ORIGINAL
Pset_WallCommon - Reference: Basic Wall:A242 - Standard 120
ePset_Simplebim - Assembly Level: Leaf
Name (Basic Wall:A242 - Standard 120:...) | Area, side, net, smaller (Simplebim) (m2) = Area, side, net, larger (Simplebim) (m2) = Area, side, net, average (Simplebim) (m2) | Area, side, gross, smaller (Simplebim) (m2) = Area, side, gross, larger (Simplebim) (m2) = Area, side, gross, average (Simplebim) (m2) = Area, side, gross, AABB (Simplebim) (m2) | Area, largest surface, net (Simplebim) (m2) | Volume, net (Simplebim) (m3) | Thickness (Simplebim) (mm) | Length (Simplebim) (mm) | Height (Simplebim) (mm)
864997 | 2.26313 | 2.26313 | 2.26313 | 0.271575 | 120 | 637.5 | 3550
864998 | 1.278 | 1.278 | 1.278 | 0.15336 | 120 | 360 | 3550
864999 | 3.48145 | 5.39245 | 3.48145 | 0.417774 | 120 | 1519 | 3550
865000 | 26.0641 | 26.0641 | 26.0641 | 3.12769 | 120 | 7342 | 3550
11671106 | 10.92 | 10.92 | 10.92 | 1.3104 | 120 | 3120 | 3500
11671107 | 23.8315 | 25.7425 | 23.8315 | 2.85978 | 120 | 7355 | 3500
12073276 | 9.02405 | 12.195 | 9.02405 | 1.08289 | 120 | 3484.3 | 3500
12575262 |  |  | 0.0165714 | 0.000085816

# IfcWallStandardCase: Basic Wall:A242 - Standard 150 (2)
In: H02-Nivå F-3,5 m
Type - PredefinedType: STANDARD; Material: _NSW Standard 150 mm
Pset_WallCommon - Reference: Basic Wall:A242 - Standard 150
ePset_LocationTool - Splitting: ORIGINAL
ePset_Simplebim - Assembly Level: Leaf
ePset_SimplebimBasicQuantities - Thickness (Simplebim): 150 mm; Height (Simplebim): 3900 mm
Name (Basic Wall:A242 - Standard 150:...) | Area, side, gross, AABB (Simplebim) (m2) | Length (Simplebim) (mm) | Volume, net (Simplebim) (m3) | Area, side, net, smaller (Simplebim) (m2) = Area, side, net, larger (Simplebim) (m2) = Area, side, gross, smaller (Simplebim) (m2) = Area, side, gross, larger (Simplebim) (m2) = Area, side, gross, average (Simplebim) (m2) = Area, largest surface, net (Simplebim) (m2) = Area, side, net, average (Simplebim) (m2)
11666190 | 19.6092 | 5028 | 2.93178 | 19.5452
12509474 | 8.8608 | 2272 | 1.32192 | 8.8128

# IfcWallStandardCase: Basic Wall:A242 - Standard 225, Basic Wall:A242 - Standard 225:864983
In: H02-Nivå F-3,5 m
Type - PredefinedType: STANDARD; Material: _NSW Standard 225 mm
ePset_LocationTool - Splitting: ORIGINAL
ePset_Simplebim - Assembly Level: Leaf
ePset_SimplebimBasicQuantities - Area, side, gross, AABB (Simplebim): 22.3277 m2; Volume, net (Simplebim): 5.02374 m3; Area, largest surface, net (Simplebim): 22.3277 m2; Area, side, net, average (Simplebim): 22.3277 m2; Area, side, gross, larger (Simplebim): 22.3277 m2; Area, side, gross, average (Simplebim): 22.3277 m2; Area, side, net, larger (Simplebim): 22.3277 m2; Area, side, gross, smaller (Simplebim): 22.3277 m2; Area, side, net, smaller (Simplebim): 22.3277 m2; Thickness (Simplebim): 225 mm; Height (Simplebim): 3550 mm; Length (Simplebim): 6289.5 mm
Pset_WallCommon - Reference: Basic Wall:A242 - Standard 225

# IfcWallStandardCase: Basic Wall:A242 - Standard 25 (2)
In: H02-Nivå F-3,5 m
Type - PredefinedType: STANDARD; Material: _NSW Standard 25 mm
Pset_WallCommon - Reference: Basic Wall:A242 - Standard 25
ePset_SimplebimBasicQuantities - Thickness (Simplebim): 25 mm; Height (Simplebim): 2100 mm
ePset_Simplebim - Assembly Level: Leaf
ePset_LocationTool - Splitting: ORIGINAL
Name (Basic Wall:A242 - Standard 25:...) | Length (Simplebim) (mm) | Volume, net (Simplebim) (m3) | Area, side, gross, AABB (Simplebim) (m2) = Area, side, net, smaller (Simplebim) (m2) = Area, side, gross, average (Simplebim) (m2) = Area, side, gross, larger (Simplebim) (m2) = Area, side, net, average (Simplebim) (m2) = Area, largest surface, net (Simplebim) (m2) = Area, side, gross, smaller (Simplebim) (m2) = Area, side, net, larger (Simplebim) (m2)
11671129 | 882.5 | 0.0463312 | 1.85325
11671130 | 2795 | 0.146738 | 5.8695
